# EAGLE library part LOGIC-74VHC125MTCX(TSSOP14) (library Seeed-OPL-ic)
310050042

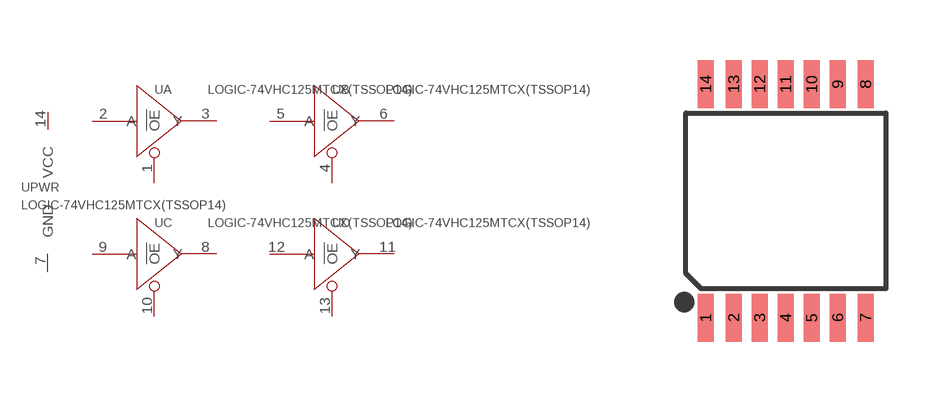
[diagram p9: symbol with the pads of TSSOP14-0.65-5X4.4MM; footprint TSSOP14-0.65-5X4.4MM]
Designator prefix U; gates A=BUFFER PWR=VCC-GND B=BUFFER C=BUFFER D=BUFFER

## LOGIC-74VHC125MTCX(TSSOP14) (MPN: 74VHC125MTCX; VALUE: 74VHC125MTCX-TSSOP14)  [TSSOP14-0.65-5X4.4MM]
1  A:!OE
2  A:A
3  A:Y
4  B:!OE
5  B:A
6  B:Y
7  PWR:GND  sup
8  C:Y
9  C:A
10  C:!OE
11  D:Y
12  D:A
13  D:!OE
14  PWR:VCC  sup

## Footprint TSSOP14-0.65-5X4.4MM (pad centres in mm)
smd 0.4 x 1.2: 1 -2,-2.925; 2 -1.3,-2.925; 3 -0.65,-2.925; 4 0,-2.925; 5 0.65,-2.925; 6 1.3,-2.925; 7 2,-2.925; 8 2,2.925; 9 1.3,2.925; 10 0.65,2.925; 11 0,2.925; 12 -0.65,2.925; 13 -1.3,2.925; 14 -2,2.925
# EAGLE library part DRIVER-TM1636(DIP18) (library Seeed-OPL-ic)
310040002

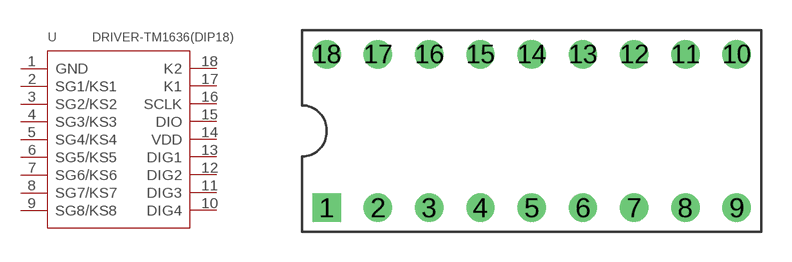
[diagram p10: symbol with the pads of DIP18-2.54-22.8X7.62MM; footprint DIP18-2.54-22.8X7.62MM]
Designator prefix U

## DRIVER-TM1636(DIP18) (MPN: TM1636; VALUE: TM1636-DIP18)  [DIP18-2.54-22.8X7.62MM]
1  GND
2  SG1/KS1
3  SG2/KS2
4  SG3/KS3
5  SG4/KS4
6  SG5/KS5
7  SG6/KS6
8  SG7/KS7
9  SG8/KS8
10  DIG4
11  DIG3
12  DIG2
13  DIG1
14  VDD
15  DIO
16  SCLK
17  K1
18  K2

## Footprint DIP18-2.54-22.8X7.62MM (pad centres in mm)
drill 0.9 pad 1.4 square: 1 -10.16,-3.81
drill 0.9 pad 1.4: 2 -7.62,-3.81; 3 -5.08,-3.81; 4 -2.54,-3.81; 5 0,-3.81; 6 2.54,-3.81; 7 5.08,-3.81; 8 7.62,-3.81; 9 10.16,-3.81; 10 10.16,3.81; 11 7.62,3.81; 12 5.08,3.81; 13 2.54,3.81; 14 0,3.81; 15 -2.54,3.81; 16 -5.08,3.81; 17 -7.62,3.81; 18 -10.16,3.81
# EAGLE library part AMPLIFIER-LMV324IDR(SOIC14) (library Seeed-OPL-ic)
310020019

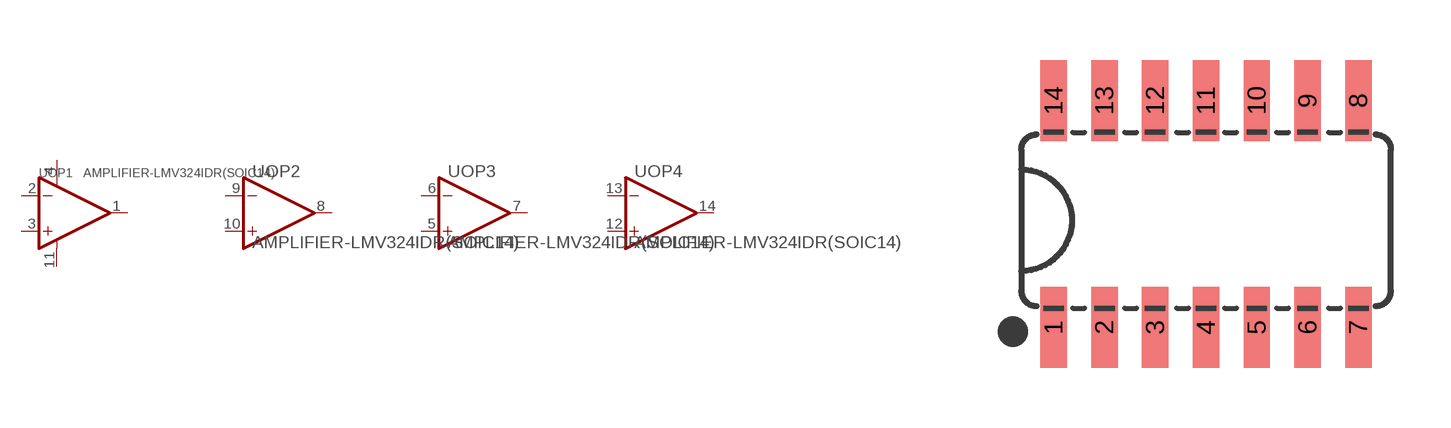
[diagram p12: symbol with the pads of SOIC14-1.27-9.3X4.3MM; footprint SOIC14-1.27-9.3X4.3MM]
Designator prefix U; gates OP1=AMPLIFIER-LM321MF OP2=OP-AMP OP3=OP-AMP OP4=OP-AMP

## AMPLIFIER-LMV324IDR(SOIC14) (MPN: LMV324IDR; VALUE: LMV324IDR-SOIC14)  [SOIC14-1.27-9.3X4.3MM]
1  OP1:OUT  out
2  OP1:IN-  in
3  OP1:IN+  in
4  OP1:V+  pwr
5  OP3:IN+  in
6  OP3:IN-  in
7  OP3:OUT  out
8  OP2:OUT  out
9  OP2:IN-  in
10  OP2:IN+  in
11  OP1:V-  pwr
12  OP4:IN+  in
13  OP4:IN-  in
14  OP4:OUT  out

## Footprint SOIC14-1.27-9.3X4.3MM (pad centres in mm)
smd 0.66 x 2.032: 1 -3.175,-2.68; 2 -1.905,-2.68; 3 -0.635,-2.68; 4 0.635,-2.68; 5 1.905,-2.68; 6 3.175,-2.68; 7 4.445,-2.68; 8 4.445,2.997; 9 3.175,2.997; 10 1.905,2.997; 11 0.635,2.997; 12 -0.635,2.997; 13 -1.905,2.997; 14 -3.175,2.997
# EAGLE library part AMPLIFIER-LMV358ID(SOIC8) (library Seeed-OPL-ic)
310020002

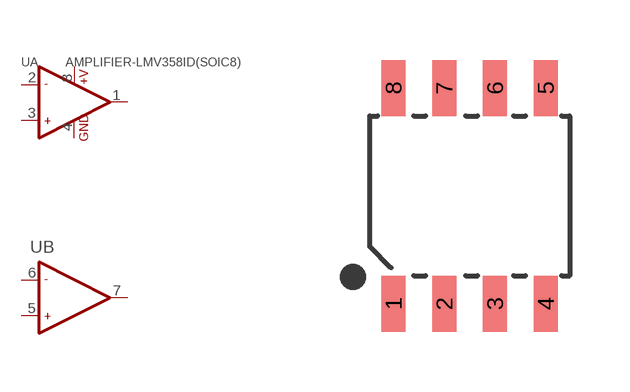
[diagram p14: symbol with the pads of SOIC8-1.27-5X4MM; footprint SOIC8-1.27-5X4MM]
Designator prefix U; gates A=OPAMP_2 B=OPAMP_2_1

## AMPLIFIER-LMV358ID(SOIC8) (MPN: LMV358ID; VALUE: LMV358ID-SOIC8)  [SOIC8-1.27-5X4MM]
1  A:OUT1  out
2  A:-IN1  in
3  A:+IN1  in
4  A:GND  pwr
5  B:+IN2  in
6  B:-IN2  in
7  B:OUT2  out
8  A:+V  pwr

## Footprint SOIC8-1.27-5X4MM (pad centres in mm)
smd 0.6 x 1.4: 1 -1.905,-2.7; 2 -0.635,-2.7; 3 0.635,-2.7; 4 1.905,-2.7; 5 1.905,2.7; 6 0.635,2.7; 7 -0.635,2.7; 8 -1.905,2.7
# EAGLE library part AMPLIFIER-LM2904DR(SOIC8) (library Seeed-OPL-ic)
310020015

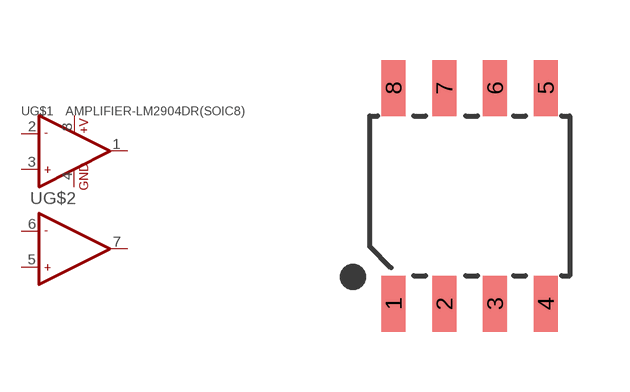
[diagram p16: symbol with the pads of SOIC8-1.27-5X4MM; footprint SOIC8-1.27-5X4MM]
Designator prefix U; gates G$1=OPAMP_2 G$2=OPAMP_2_1

## AMPLIFIER-LM2904DR(SOIC8) (MPN: LM2904DR; VALUE: LM2904DR-SOIC8)  [SOIC8-1.27-5X4MM]
1  G$1:OUT1  out
2  G$1:-IN1  in
3  G$1:+IN1  in
4  G$1:GND  pwr
5  G$2:+IN2  in
6  G$2:-IN2  in
7  G$2:OUT2  out
8  G$1:+V  pwr

## Footprint SOIC8-1.27-5X4MM (pad centres in mm)
smd 0.6 x 1.4: 1 -1.905,-2.7; 2 -0.635,-2.7; 3 0.635,-2.7; 4 1.905,-2.7; 5 1.905,2.7; 6 0.635,2.7; 7 -0.635,2.7; 8 -1.905,2.7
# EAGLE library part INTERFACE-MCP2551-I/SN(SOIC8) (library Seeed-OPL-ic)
310070024

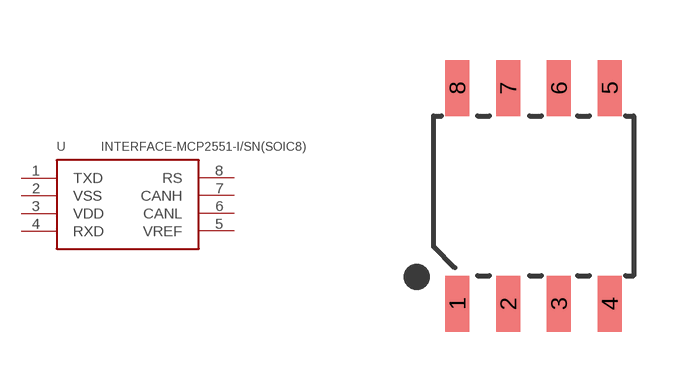
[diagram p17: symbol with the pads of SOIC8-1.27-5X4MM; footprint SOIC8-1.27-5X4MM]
Designator prefix U

## INTERFACE-MCP2551-I/SN(SOIC8) (MPN: MCP2551-I/SN; VALUE: MCP2551-I/SN-SOIC8)  [SOIC8-1.27-5X4MM]
1  TXD
2  VSS
3  VDD
4  RXD
5  VREF
6  CANL
7  CANH
8  RS

## Footprint SOIC8-1.27-5X4MM (pad centres in mm)
smd 0.6 x 1.4: 1 -1.905,-2.7; 2 -0.635,-2.7; 3 0.635,-2.7; 4 1.905,-2.7; 5 1.905,2.7; 6 0.635,2.7; 7 -0.635,2.7; 8 -1.905,2.7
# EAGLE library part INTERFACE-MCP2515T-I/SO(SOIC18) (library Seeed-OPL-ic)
310070025

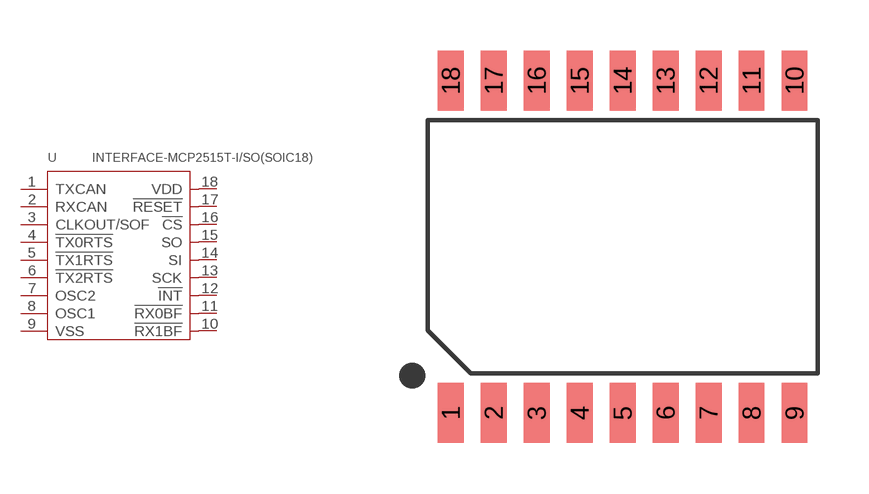
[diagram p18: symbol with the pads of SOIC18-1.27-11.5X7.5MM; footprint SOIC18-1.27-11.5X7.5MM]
Designator prefix U

## INTERFACE-MCP2515T-I/SO(SOIC18) (MPN: MCP2515T-I/SO; VALUE: MCP2515T-I/SO-SOIC18)  [SOIC18-1.27-11.5X7.5MM]
1  TXCAN  out
2  RXCAN  in
3  CLKOUT/SOF  out
4  !TX0RTS  in
5  !TX1RTS  in
6  !TX2RTS  in
7  OSC2  out
8  OSC1  in
9  VSS  sup
10  !RX1BF  out
11  !RX0BF  out
12  !INT  out
13  SCK  in
14  SI  in
15  SO  out
16  !CS  in
17  !RESET  in
18  VDD  sup

## Footprint SOIC18-1.27-11.5X7.5MM (pad centres in mm)
smd 0.762 x 1.778: 1 -5.08,-4.915; 2 -3.81,-4.915; 3 -2.54,-4.915; 4 -1.27,-4.915; 5 0,-4.915; 6 1.27,-4.915; 7 2.54,-4.915; 8 3.81,-4.915; 9 5.08,-4.915; 10 5.08,4.915; 11 3.81,4.915; 12 2.54,4.915; 13 1.27,4.915; 14 0,4.915; 15 -1.27,4.915; 16 -2.54,4.915; 17 -3.81,4.915; 18 -5.08,4.915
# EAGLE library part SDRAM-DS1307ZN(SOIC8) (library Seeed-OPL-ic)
310110010

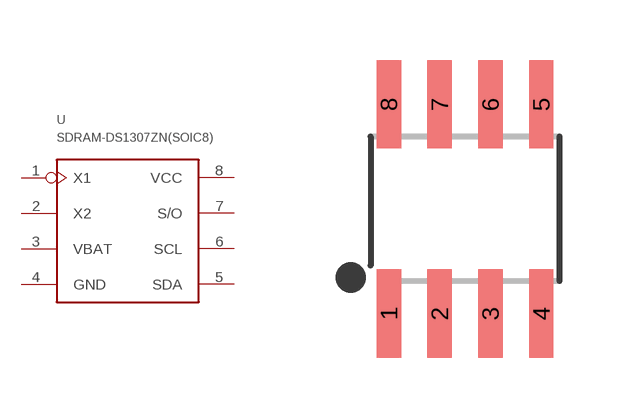
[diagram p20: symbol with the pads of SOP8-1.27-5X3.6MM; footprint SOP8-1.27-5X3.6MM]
Designator prefix U

## SDRAM-DS1307ZN(SOIC8) (MPN: DS1307ZN; VALUE: DS1307ZN-sop8)  [SOP8-1.27-5X3.6MM]
1  X1
2  X2
3  VBAT
4  GND
5  SDA
6  SCL
7  S/O
8  VCC

## Footprint SOP8-1.27-5X3.6MM (pad centres in mm)
Small Outline Package
smd 0.61 x 2.21: 1 -1.905,-2.616; 2 -0.635,-2.616; 3 0.635,-2.616; 4 1.905,-2.616; 5 1.905,2.616; 6 0.635,2.616; 7 -0.635,2.616; 8 -1.905,2.616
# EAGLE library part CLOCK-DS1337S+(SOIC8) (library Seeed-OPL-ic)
310110008

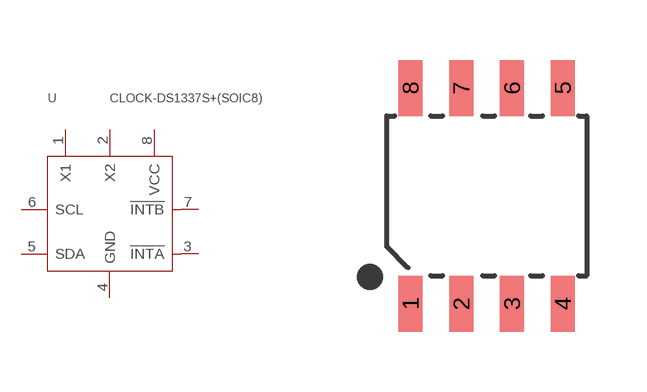
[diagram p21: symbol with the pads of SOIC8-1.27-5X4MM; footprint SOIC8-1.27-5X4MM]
Designator prefix U

## CLOCK-DS1337S+(SOIC8) (MPN: DS1337S+; VALUE: DS13337S+-SOIC8)  [SOIC8-1.27-5X4MM]
1  X1
2  X2
3  !INTA!
4  GND
5  SDA
6  SCL
7  !INTB!
8  VCC

## Footprint SOIC8-1.27-5X4MM (pad centres in mm)
smd 0.6 x 1.4: 1 -1.905,-2.7; 2 -0.635,-2.7; 3 0.635,-2.7; 4 1.905,-2.7; 5 1.905,2.7; 6 0.635,2.7; 7 -0.635,2.7; 8 -1.905,2.7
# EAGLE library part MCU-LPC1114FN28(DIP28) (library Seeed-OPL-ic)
310010024

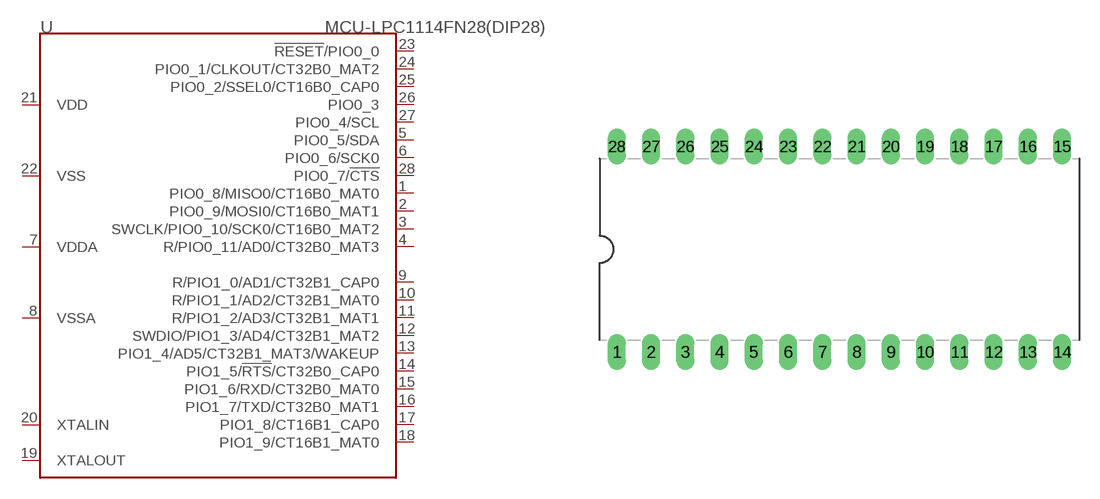
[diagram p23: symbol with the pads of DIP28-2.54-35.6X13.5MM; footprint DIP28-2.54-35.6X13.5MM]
Designator prefix U

## MCU-LPC1114FN28(DIP28) (MPN: LPC1114FN28; VALUE: LPC1114FN28-DIP28)  [DIP28-2.54-35.6X13.5MM]
1  PIO0_8/MISO0/CT16B0_MAT0
2  PIO0_9/MOSI0/CT16B0_MAT1
3  SWCLK/PIO0_10/SCK0/CT16B0_MAT2
4  R/PIO0_11/AD0/CT32B0_MAT3
5  PIO0_5/SDA
6  PIO0_6/SCK0
7  VDDA  pwr
8  VSSA  pwr
9  R/PIO1_0/AD1/CT32B1_CAP0
10  R/PIO1_1/AD2/CT32B1_MAT0
11  R/PIO1_2/AD3/CT32B1_MAT1
12  SWDIO/PIO1_3/AD4/CT32B1_MAT2
13  PIO1_4/AD5/CT32B1_MAT3/WAKEUP
14  PIO1_5/!RTS!/CT32B0_CAP0
15  PIO1_6/RXD/CT32B0_MAT0
16  PIO1_7/TXD/CT32B0_MAT1
17  PIO1_8/CT16B1_CAP0
18  PIO1_9/CT16B1_MAT0
19  XTALOUT  pas
20  XTALIN  pas
21  VDD  pwr
22  VSS  pwr
23  !RESET!/PIO0_0
24  PIO0_1/CLKOUT/CT32B0_MAT2
25  PIO0_2/SSEL0/CT16B0_CAP0
26  PIO0_3
27  PIO0_4/SCL
28  PIO0_7/!CTS!

## Footprint DIP28-2.54-35.6X13.5MM (pad centres in mm)
drill 0.813 long: 1 -16.51,-7.62; 2 -13.97,-7.62; 3 -11.43,-7.62; 4 -8.89,-7.62; 5 -6.35,-7.62; 6 -3.81,-7.62; 7 -1.27,-7.62; 8 1.27,-7.62; 9 3.81,-7.62; 10 6.35,-7.62; 11 8.89,-7.62; 12 11.43,-7.62; 13 13.97,-7.62; 14 16.51,-7.62; 15 16.51,7.62; 16 13.97,7.62; 17 11.43,7.62; 18 8.89,7.62; 19 6.35,7.62; 20 3.81,7.62; 21 1.27,7.62; 22 -1.27,7.62; 23 -3.81,7.62; 24 -6.35,7.62; 25 -8.89,7.62; 26 -11.43,7.62; 27 -13.97,7.62; 28 -16.51,7.62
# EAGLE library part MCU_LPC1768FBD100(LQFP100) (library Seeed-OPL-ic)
310010001

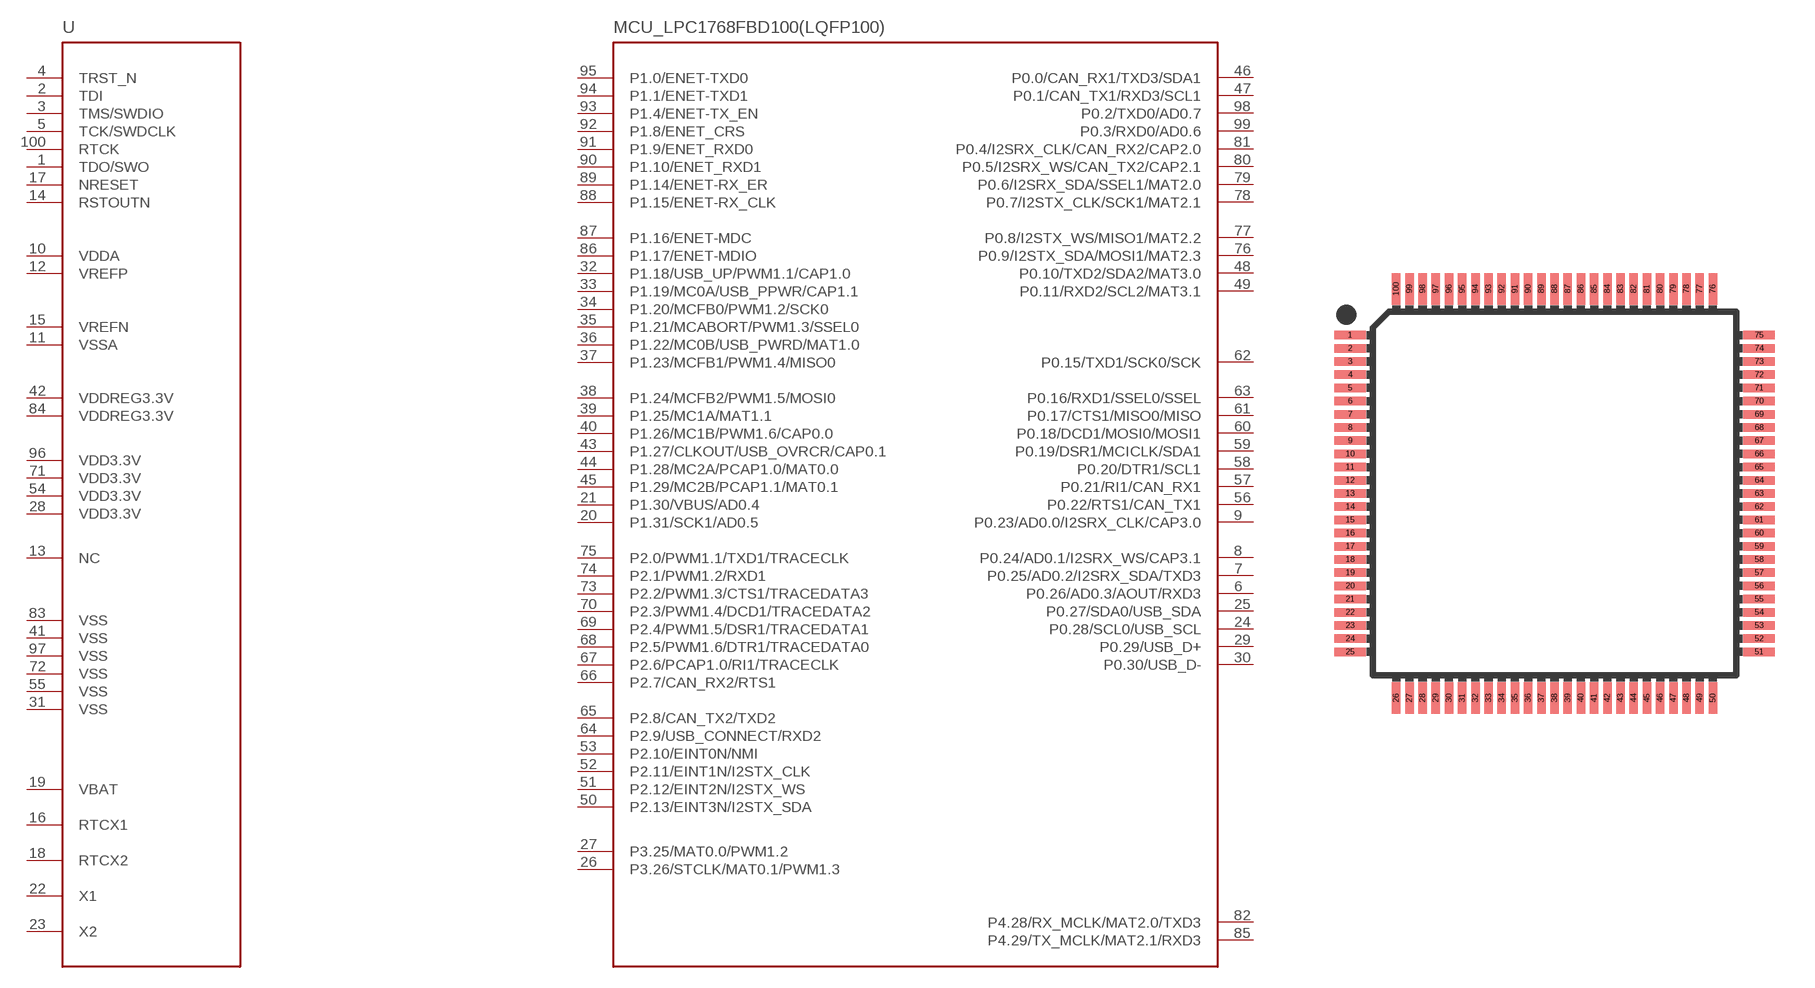
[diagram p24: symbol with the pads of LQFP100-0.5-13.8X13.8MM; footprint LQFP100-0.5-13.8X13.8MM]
Designator prefix U

## MCU_LPC1768FBD100(LQFP100) (MPN: LPC1768FBD100; VALUE: LPC1768FBD100-LQFP100)  [LQFP100-0.5-13.8X13.8MM]
1  TDO/SWO
2  TDI
3  TMS/SWDIO
4  TRST_N
5  TCK/SWDCLK
6  P0.26/AD0.3/AOUT/RXD3
7  P0.25/AD0.2/I2SRX_SDA/TXD3
8  P0.24/AD0.1/I2SRX_WS/CAP3.1
9  P0.23/AD0.0/I2SRX_CLK/CAP3.0
10  VDDA
11  VSSA
12  VREFP
13  NC
14  RSTOUTN
15  VREFN
16  RTCX1
17  NRESET
18  RTCX2
19  VBAT
20  P1.31/SCK1/AD0.5
21  P1.30/VBUS/AD0.4
22  X1
23  X2
24  P0.28/SCL0/USB_SCL
25  P0.27/SDA0/USB_SDA
26  P3.26/STCLK/MAT0.1/PWM1.3
27  P3.25/MAT0.0/PWM1.2
28  VDD3.3V
29  P0.29/USB_D+
30  P0.30/USB_D-
31  VSS
32  P1.18/USB_UP/PWM1.1/CAP1.0
33  P1.19/MC0A/USB_PPWR/CAP1.1
34  P1.20/MCFB0/PWM1.2/SCK0
35  P1.21/MCABORT/PWM1.3/SSEL0
36  P1.22/MC0B/USB_PWRD/MAT1.0
37  P1.23/MCFB1/PWM1.4/MISO0
38  P1.24/MCFB2/PWM1.5/MOSI0
39  P1.25/MC1A/MAT1.1
40  P1.26/MC1B/PWM1.6/CAP0.0
41  VSS
42  VDDREG3.3V
43  P1.27/CLKOUT/USB_OVRCR/CAP0.1
44  P1.28/MC2A/PCAP1.0/MAT0.0
45  P1.29/MC2B/PCAP1.1/MAT0.1
46  P0.0/CAN_RX1/TXD3/SDA1
47  P0.1/CAN_TX1/RXD3/SCL1
48  P0.10/TXD2/SDA2/MAT3.0
49  P0.11/RXD2/SCL2/MAT3.1
50  P2.13/EINT3N/I2STX_SDA
51  P2.12/EINT2N/I2STX_WS
52  P2.11/EINT1N/I2STX_CLK
53  P2.10/EINT0N/NMI
54  VDD3.3V
55  VSS
56  P0.22/RTS1/CAN_TX1
57  P0.21/RI1/CAN_RX1
58  P0.20/DTR1/SCL1
59  P0.19/DSR1/MCICLK/SDA1
60  P0.18/DCD1/MOSI0/MOSI1
61  P0.17/CTS1/MISO0/MISO
62  P0.15/TXD1/SCK0/SCK
63  P0.16/RXD1/SSEL0/SSEL
64  P2.9/USB_CONNECT/RXD2
65  P2.8/CAN_TX2/TXD2
66  P2.7/CAN_RX2/RTS1
67  P2.6/PCAP1.0/RI1/TRACECLK
68  P2.5/PWM1.6/DTR1/TRACEDATA0
69  P2.4/PWM1.5/DSR1/TRACEDATA1
70  P2.3/PWM1.4/DCD1/TRACEDATA2
71  VDD3.3V
72  VSS
73  P2.2/PWM1.3/CTS1/TRACEDATA3
74  P2.1/PWM1.2/RXD1
75  P2.0/PWM1.1/TXD1/TRACECLK
76  P0.9/I2STX_SDA/MOSI1/MAT2.3
77  P0.8/I2STX_WS/MISO1/MAT2.2
78  P0.7/I2STX_CLK/SCK1/MAT2.1
79  P0.6/I2SRX_SDA/SSEL1/MAT2.0
80  P0.5/I2SRX_WS/CAN_TX2/CAP2.1
81  P0.4/I2SRX_CLK/CAN_RX2/CAP2.0
82  P4.28/RX_MCLK/MAT2.0/TXD3
83  VSS
84  VDDREG3.3V
85  P4.29/TX_MCLK/MAT2.1/RXD3
86  P1.17/ENET-MDIO
87  P1.16/ENET-MDC
88  P1.15/ENET-RX_CLK
89  P1.14/ENET-RX_ER
90  P1.10/ENET_RXD1
91  P1.9/ENET_RXD0
92  P1.8/ENET_CRS
93  P1.4/ENET-TX_EN
94  P1.1/ENET-TXD1
95  P1.0/ENET-TXD0
96  VDD3.3V
97  VSS
98  P0.2/TXD0/AD0.7
99  P0.3/RXD0/AD0.6
100  RTCK

## Footprint LQFP100-0.5-13.8X13.8MM (pad centres in mm)
smd 1.2 x 0.32: 1 -7.75,6; 2 -7.75,5.5; 3 -7.75,5; 4 -7.75,4.5; 5 -7.75,4; 6 -7.75,3.5; 7 -7.75,3; 8 -7.75,2.5; 9 -7.75,2; 10 -7.75,1.5; 11 -7.75,1; 12 -7.75,0.5; 13 -7.75,0; 14 -7.75,-0.5; 15 -7.75,-1; 16 -7.75,-1.5; 17 -7.75,-2; 18 -7.75,-2.5; 19 -7.75,-3; 20 -7.75,-3.5; 21 -7.75,-4; 22 -7.75,-4.5; 23 -7.75,-5; 24 -7.75,-5.5; 25 -7.75,-6; 51 7.75,-6; 52 7.75,-5.5; 53 7.75,-5; 54 7.75,-4.5; 55 7.75,-4; 56 7.75,-3.5; 57 7.75,-3; 58 7.75,-2.5; 59 7.75,-2; 60 7.75,-1.5; 61 7.75,-1; 62 7.75,-0.5; 63 7.75,0; 64 7.75,0.5; 65 7.75,1; 66 7.75,1.5; 67 7.75,2; 68 7.75,2.5; 69 7.75,3; 70 7.75,3.5; 71 7.75,4; 72 7.75,4.5; 73 7.75,5; 74 7.75,5.5; 75 7.75,6
smd 0.32 x 1.2: 26 -6,-7.75; 27 -5.5,-7.75; 28 -5,-7.75; 29 -4.5,-7.75; 30 -4,-7.75; 31 -3.5,-7.75; 32 -3,-7.75; 33 -2.5,-7.75; 34 -2,-7.75; 35 -1.5,-7.75; 36 -1,-7.75; 37 -0.5,-7.75; 38 0,-7.75; 39 0.5,-7.75; 40 1,-7.75; 41 1.5,-7.75; 42 2,-7.75; 43 2.5,-7.75; 44 3,-7.75; 45 3.5,-7.75; 46 4,-7.75; 47 4.5,-7.75; 48 5,-7.75; 49 5.5,-7.75; 50 6,-7.75; 76 6,7.75; 77 5.5,7.75; 78 5,7.75; 79 4.5,7.75; 80 4,7.75; 81 3.5,7.75; 82 3,7.75; 83 2.5,7.75; 84 2,7.75; 85 1.5,7.75; 86 1,7.75; 87 0.5,7.75; 88 0,7.75; 89 -0.5,7.75; 90 -1,7.75; 91 -1.5,7.75; 92 -2,7.75; 93 -2.5,7.75; 94 -3,7.75; 95 -3.5,7.75; 96 -4,7.75; 97 -4.5,7.75; 98 -5,7.75; 99 -5.5,7.75; 100 -6,7.75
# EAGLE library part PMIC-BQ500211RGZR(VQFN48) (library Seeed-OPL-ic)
310030145

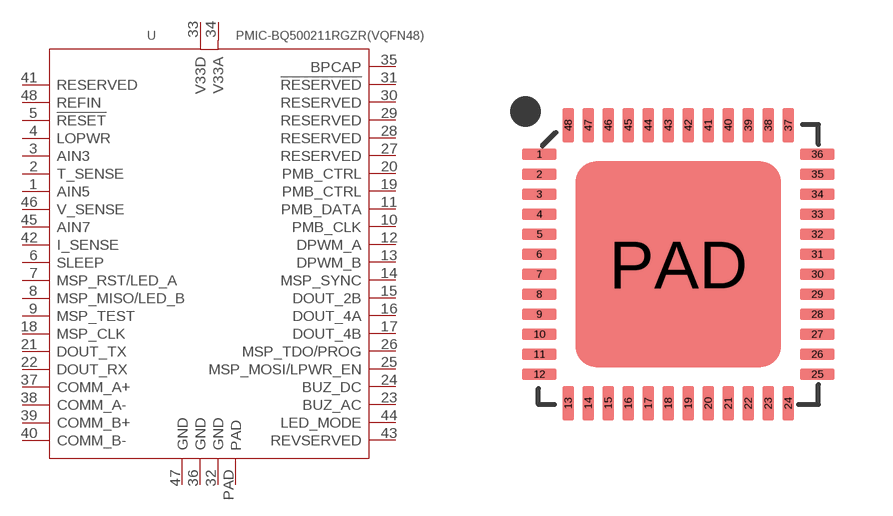
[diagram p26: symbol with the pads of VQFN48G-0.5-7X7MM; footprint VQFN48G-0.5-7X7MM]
Designator prefix U

## PMIC-BQ500211RGZR(VQFN48) (MPN: BQ500211RGZR; VALUE: BQ500211RGZR-VQFN48)  [VQFN48G-0.5-7X7MM]
1  AIN5
2  T_SENSE
3  AIN3
4  LOPWR
5  !RESET
6  SLEEP
7  MSP_RST/LED_A
8  MSP_MISO/LED_B
9  MSP_TEST
10  PMB_CLK
11  PMB_DATA
12  DPWM_A
13  DPWM_B
14  MSP_SYNC
15  DOUT_2B
16  DOUT_4A
17  DOUT_4B
18  MSP_CLK
19  PMB_CTRL
20  PMB_CTRL
21  DOUT_TX
22  DOUT_RX
23  BUZ_AC
24  BUZ_DC
25  MSP_MOSI/LPWR_EN
26  MSP_TDO/PROG
27  RESERVED
28  RESERVED
29  RESERVED
30  RESERVED
31  !RESERVED
32  GND
33  V33D
34  V33A
35  BPCAP
36  GND
37  COMM_A+
38  COMM_A-
39  COMM_B+
40  COMM_B-
41  RESERVED
42  I_SENSE
43  REVSERVED
44  LED_MODE
45  AIN7
46  V_SENSE
47  GND
48  REFIN
PAD  PAD

## Footprint VQFN48G-0.5-7X7MM (pad centres in mm)
smd 0.85 x 0.28: 1 -3.475,2.75; 2 -3.475,2.25; 3 -3.475,1.75; 4 -3.475,1.25; 5 -3.475,0.75; 6 -3.475,0.25; 7 -3.475,-0.25; 8 -3.475,-0.75; 9 -3.475,-1.25; 10 -3.475,-1.75; 11 -3.475,-2.25; 12 -3.475,-2.75; 25 3.475,-2.75; 26 3.475,-2.25; 27 3.475,-1.75; 28 3.475,-1.25; 29 3.475,-0.75; 30 3.475,-0.25; 31 3.475,0.25; 32 3.475,0.75; 33 3.475,1.25; 34 3.475,1.75; 35 3.475,2.25; 36 3.475,2.75
smd 0.28 x 0.85: 13 -2.75,-3.475; 14 -2.25,-3.475; 15 -1.75,-3.475; 16 -1.25,-3.475; 17 -0.75,-3.475; 18 -0.25,-3.475; 19 0.25,-3.475; 20 0.75,-3.475; 21 1.25,-3.475; 22 1.75,-3.475; 23 2.25,-3.475; 24 2.75,-3.475; 37 2.75,3.475; 38 2.25,3.475; 39 1.75,3.475; 40 1.25,3.475; 41 0.75,3.475; 42 0.25,3.475; 43 -0.25,3.475; 44 -0.75,3.475; 45 -1.25,3.475; 46 -1.75,3.475; 47 -2.25,3.475; 48 -2.75,3.475
smd 5.15 x 5.15: PAD 0,0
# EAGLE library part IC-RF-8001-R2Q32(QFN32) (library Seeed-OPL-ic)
310060013

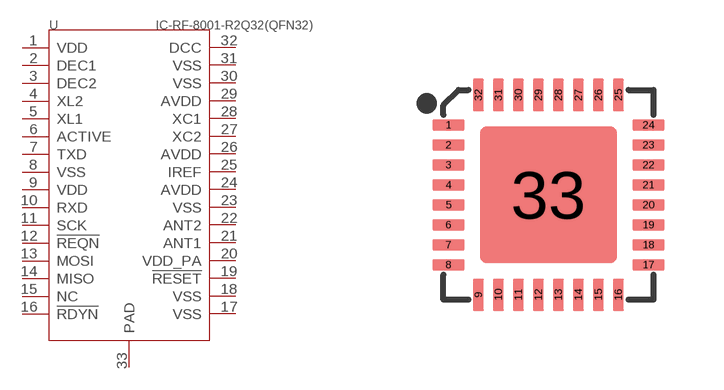
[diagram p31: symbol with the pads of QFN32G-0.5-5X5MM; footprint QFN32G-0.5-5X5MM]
Designator prefix U

## IC-RF-8001-R2Q32(QFN32) (MPN: 8001-R2Q32; VALUE: 8001-R2Q32-QFN32)  [QFN32G-0.5-5X5MM]
1  VDD
2  DEC1
3  DEC2
4  XL2
5  XL1
6  ACTIVE
7  TXD
8  VSS
9  VDD
10  RXD
11  SCK
12  !REQN
13  MOSI
14  MISO
15  NC
16  !RDYN
17  VSS
18  VSS
19  !RESET
20  VDD_PA
21  ANT1
22  ANT2
23  VSS
24  AVDD
25  IREF
26  AVDD
27  XC2
28  XC1
29  AVDD
30  VSS
31  VSS
32  DCC
33  PAD

## Footprint QFN32G-0.5-5X5MM (pad centres in mm)
smd 0.813 x 0.279: 1 -2.5,1.75; 2 -2.5,1.25; 3 -2.5,0.75; 4 -2.5,0.25; 5 -2.5,-0.25; 6 -2.5,-0.75; 7 -2.5,-1.25; 8 -2.5,-1.75; 17 2.5,-1.75; 18 2.5,-1.25; 19 2.5,-0.75; 20 2.5,-0.25; 21 2.5,0.25; 22 2.5,0.75; 23 2.5,1.25; 24 2.5,1.75
smd 0.279 x 0.813: 9 -1.75,-2.5; 10 -1.25,-2.5; 11 -0.75,-2.5; 12 -0.25,-2.5; 13 0.25,-2.5; 14 0.75,-2.5; 15 1.25,-2.5; 16 1.75,-2.5; 25 1.75,2.5; 26 1.25,2.5; 27 0.75,2.5; 28 0.25,2.5; 29 -0.25,2.5; 30 -0.75,2.5; 31 -1.25,2.5; 32 -1.75,2.5
smd 3.429 x 3.429: 33 0,0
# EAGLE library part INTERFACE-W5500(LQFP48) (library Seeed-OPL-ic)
310070032

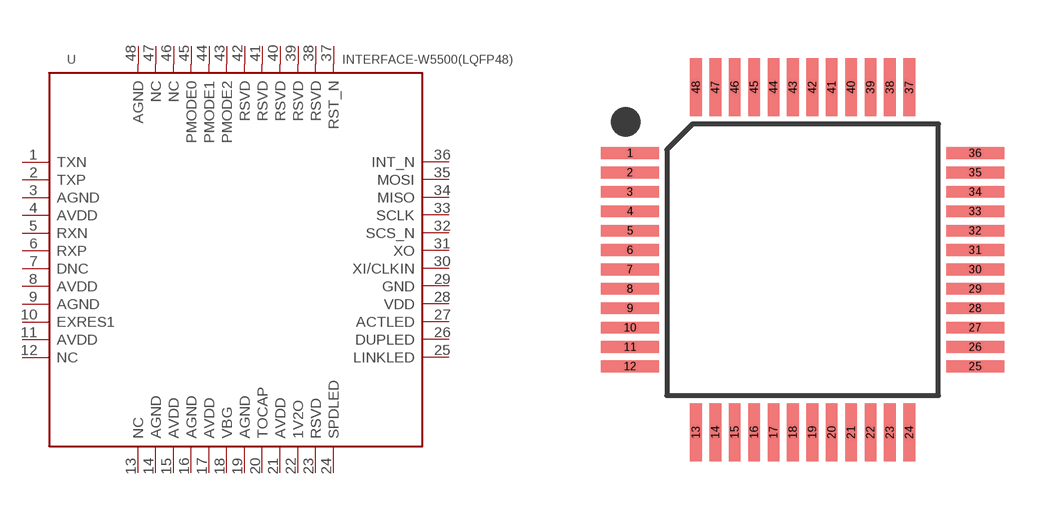
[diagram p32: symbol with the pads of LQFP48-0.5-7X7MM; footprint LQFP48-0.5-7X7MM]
Designator prefix U

## INTERFACE-W5500(LQFP48) (MPN: W5500; VALUE: W5500-LQFP48)  [LQFP48-0.5-7X7MM]
1  TXN  pas
2  TXP  pas
3  AGND  pas
4  AVDD  pas
5  RXN  pas
6  RXP  pas
7  DNC  pas
8  AVDD  pas
9  AGND  pas
10  EXRES1  pas
11  AVDD  pas
12  NC  pas
13  NC  pas
14  AGND  pas
15  AVDD  pas
16  AGND  pas
17  AVDD  pas
18  VBG  pas
19  AGND  pas
20  TOCAP  pas
21  AVDD  pas
22  1V2O  pas
23  RSVD  pas
24  SPDLED  pas
25  LINKLED  pas
26  DUPLED  pas
27  ACTLED  pas
28  VDD  pas
29  GND  pas
30  XI/CLKIN  pas
31  XO  pas
32  SCS_N  pas
33  SCLK  pas
34  MISO  pas
35  MOSI  pas
36  INT_N  pas
37  RST_N  pas
38  RSVD  pas
39  RSVD  pas
40  RSVD  pas
41  RSVD  pas
42  RSVD  pas
43  PMODE2  pas
44  PMODE1  pas
45  PMODE0  pas
46  NC  pas
47  NC  pas
48  AGND  pas

## Footprint LQFP48-0.5-7X7MM (pad centres in mm)
smd 1.5 x 0.3: 1 -4.45,2.75; 2 -4.45,2.25; 3 -4.45,1.75; 4 -4.45,1.25; 5 -4.45,0.75; 6 -4.45,0.25; 7 -4.45,-0.25; 8 -4.45,-0.75; 9 -4.45,-1.25; 10 -4.45,-1.75; 11 -4.45,-2.25; 12 -4.45,-2.75; 25 4.45,-2.75; 26 4.45,-2.25; 27 4.45,-1.75; 28 4.45,-1.25; 29 4.45,-0.75; 30 4.45,-0.25; 31 4.45,0.25; 32 4.45,0.75; 33 4.45,1.25; 34 4.45,1.75; 35 4.45,2.25; 36 4.45,2.75
smd 0.3 x 1.5: 13 -2.75,-4.45; 14 -2.25,-4.45; 15 -1.75,-4.45; 16 -1.25,-4.45; 17 -0.75,-4.45; 18 -0.25,-4.45; 19 0.25,-4.45; 20 0.75,-4.45; 21 1.25,-4.45; 22 1.75,-4.45; 23 2.25,-4.45; 24 2.75,-4.45; 37 2.75,4.45; 38 2.25,4.45; 39 1.75,4.45; 40 1.25,4.45; 41 0.75,4.45; 42 0.25,4.45; 43 -0.25,4.45; 44 -0.75,4.45; 45 -1.25,4.45; 46 -1.75,4.45; 47 -2.25,4.45; 48 -2.75,4.45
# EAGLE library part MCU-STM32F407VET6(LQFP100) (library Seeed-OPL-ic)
310010067

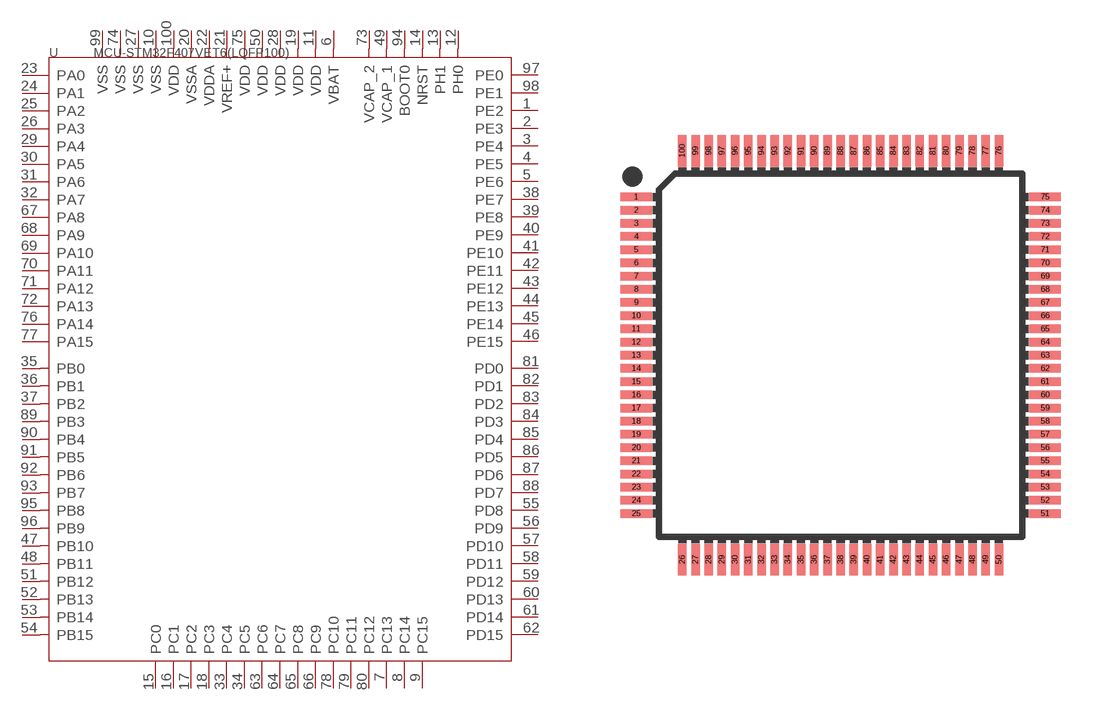
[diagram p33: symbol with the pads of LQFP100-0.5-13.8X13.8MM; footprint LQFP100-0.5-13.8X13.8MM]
Designator prefix U

## MCU-STM32F407VET6(LQFP100) (MPN: STM32F407VET6; VALUE: STM32F407VET6-LQFP100)  [LQFP100-0.5-13.8X13.8MM]
1  PE2
2  PE3
3  PE4
4  PE5
5  PE6
6  VBAT
7  PC13
8  PC14
9  PC15
10  VSS
11  VDD
12  PH0
13  PH1
14  NRST
15  PC0
16  PC1
17  PC2
18  PC3
19  VDD
20  VSSA
21  VREF+
22  VDDA
23  PA0
24  PA1
25  PA2
26  PA3
27  VSS
28  VDD
29  PA4
30  PA5
31  PA6
32  PA7
33  PC4
34  PC5
35  PB0
36  PB1
37  PB2
38  PE7
39  PE8
40  PE9
41  PE10
42  PE11
43  PE12
44  PE13
45  PE14
46  PE15
47  PB10
48  PB11
49  VCAP_1
50  VDD
51  PB12
52  PB13
53  PB14
54  PB15
55  PD8
56  PD9
57  PD10
58  PD11
59  PD12
60  PD13
61  PD14
62  PD15
63  PC6
64  PC7
65  PC8
66  PC9
67  PA8
68  PA9
69  PA10
70  PA11
71  PA12
72  PA13
73  VCAP_2
74  VSS
75  VDD
76  PA14
77  PA15
78  PC10
79  PC11
80  PC12
81  PD0
82  PD1
83  PD2
84  PD3
85  PD4
86  PD5
87  PD6
88  PD7
89  PB3
90  PB4
91  PB5
92  PB6
93  PB7
94  BOOT0
95  PB8
96  PB9
97  PE0
98  PE1
99  VSS
100  VDD

## Footprint LQFP100-0.5-13.8X13.8MM (pad centres in mm)
smd 1.2 x 0.32: 1 -7.75,6; 2 -7.75,5.5; 3 -7.75,5; 4 -7.75,4.5; 5 -7.75,4; 6 -7.75,3.5; 7 -7.75,3; 8 -7.75,2.5; 9 -7.75,2; 10 -7.75,1.5; 11 -7.75,1; 12 -7.75,0.5; 13 -7.75,0; 14 -7.75,-0.5; 15 -7.75,-1; 16 -7.75,-1.5; 17 -7.75,-2; 18 -7.75,-2.5; 19 -7.75,-3; 20 -7.75,-3.5; 21 -7.75,-4; 22 -7.75,-4.5; 23 -7.75,-5; 24 -7.75,-5.5; 25 -7.75,-6; 51 7.75,-6; 52 7.75,-5.5; 53 7.75,-5; 54 7.75,-4.5; 55 7.75,-4; 56 7.75,-3.5; 57 7.75,-3; 58 7.75,-2.5; 59 7.75,-2; 60 7.75,-1.5; 61 7.75,-1; 62 7.75,-0.5; 63 7.75,0; 64 7.75,0.5; 65 7.75,1; 66 7.75,1.5; 67 7.75,2; 68 7.75,2.5; 69 7.75,3; 70 7.75,3.5; 71 7.75,4; 72 7.75,4.5; 73 7.75,5; 74 7.75,5.5; 75 7.75,6
smd 0.32 x 1.2: 26 -6,-7.75; 27 -5.5,-7.75; 28 -5,-7.75; 29 -4.5,-7.75; 30 -4,-7.75; 31 -3.5,-7.75; 32 -3,-7.75; 33 -2.5,-7.75; 34 -2,-7.75; 35 -1.5,-7.75; 36 -1,-7.75; 37 -0.5,-7.75; 38 0,-7.75; 39 0.5,-7.75; 40 1,-7.75; 41 1.5,-7.75; 42 2,-7.75; 43 2.5,-7.75; 44 3,-7.75; 45 3.5,-7.75; 46 4,-7.75; 47 4.5,-7.75; 48 5,-7.75; 49 5.5,-7.75; 50 6,-7.75; 76 6,7.75; 77 5.5,7.75; 78 5,7.75; 79 4.5,7.75; 80 4,7.75; 81 3.5,7.75; 82 3,7.75; 83 2.5,7.75; 84 2,7.75; 85 1.5,7.75; 86 1,7.75; 87 0.5,7.75; 88 0,7.75; 89 -0.5,7.75; 90 -1,7.75; 91 -1.5,7.75; 92 -2,7.75; 93 -2.5,7.75; 94 -3,7.75; 95 -3.5,7.75; 96 -4,7.75; 97 -4.5,7.75; 98 -5,7.75; 99 -5.5,7.75; 100 -6,7.75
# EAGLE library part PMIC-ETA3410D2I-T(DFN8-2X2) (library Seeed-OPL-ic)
310030161

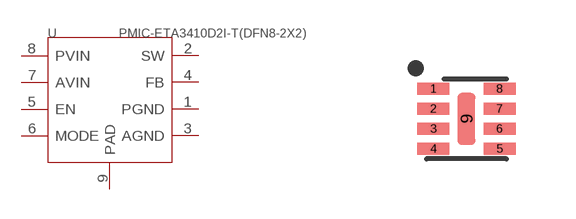
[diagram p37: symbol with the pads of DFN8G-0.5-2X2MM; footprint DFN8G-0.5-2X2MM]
Designator prefix U

## PMIC-ETA3410D2I-T(DFN8-2X2) (MPN: ETA3410D2I-T; VALUE: ETA3410D2I-T-DFN8)  [DFN8G-0.5-2X2MM]
1  PGND
2  SW
3  AGND
4  FB
5  EN
6  MODE
7  AVIN
8  PVIN
9  PAD

## Footprint DFN8G-0.5-2X2MM (pad centres in mm)
smd 0.8 x 0.3: 1 -0.827,0.75; 2 -0.827,0.25; 3 -0.827,-0.25; 4 -0.827,-0.75; 5 0.827,-0.75; 6 0.827,-0.25; 7 0.827,0.25; 8 0.827,0.75
smd 0.45 x 1.3: 9 0,0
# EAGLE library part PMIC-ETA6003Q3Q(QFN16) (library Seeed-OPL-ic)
310990023

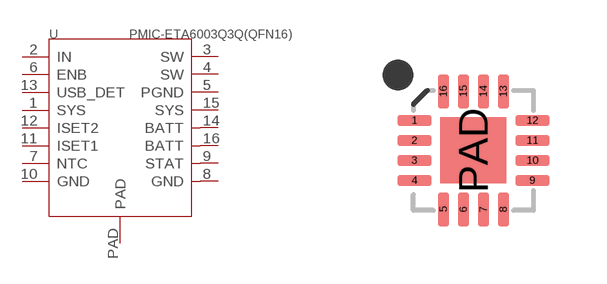
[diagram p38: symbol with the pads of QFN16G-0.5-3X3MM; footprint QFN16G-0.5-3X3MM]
Designator prefix U

## PMIC-ETA6003Q3Q(QFN16) (MPN: ETA6003Q3Q; VALUE: ETA6003Q3Q-QFN16)  [QFN16G-0.5-3X3MM]
1  SYS
2  IN
3  SW
4  SW
5  PGND
6  ENB
7  NTC
8  GND
9  STAT
10  GND
11  ISET1
12  ISET2
13  USB_DET
14  BATT
15  SYS
16  BATT
PAD  PAD

## Footprint QFN16G-0.5-3X3MM (pad centres in mm)
smd 0.85 x 0.28: 1 -1.475,0.75; 2 -1.475,0.25; 3 -1.475,-0.25; 4 -1.475,-0.75; 9 1.475,-0.75; 10 1.475,-0.25; 11 1.475,0.25; 12 1.475,0.75
smd 0.28 x 0.85: 5 -0.75,-1.475; 6 -0.25,-1.475; 7 0.25,-1.475; 8 0.75,-1.475; 13 0.75,1.475; 14 0.25,1.475; 15 -0.25,1.475; 16 -0.75,1.475
smd 1.65 x 1.65: PAD 0,0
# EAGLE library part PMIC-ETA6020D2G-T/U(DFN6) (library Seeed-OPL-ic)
310990024

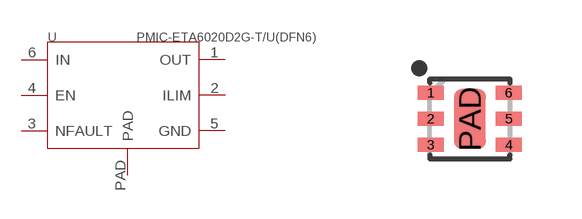
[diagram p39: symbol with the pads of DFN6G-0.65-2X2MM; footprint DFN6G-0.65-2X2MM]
Designator prefix U

## PMIC-ETA6020D2G-T/U(DFN6) (MPN: ETA6020D2G-T/U; VALUE: ETA6020D2G-T/U-DFN6)  [DFN6G-0.65-2X2MM]
1  OUT
2  ILIM
3  NFAULT
4  EN
5  GND
6  IN
PAD  PAD

## Footprint DFN6G-0.65-2X2MM (pad centres in mm)
smd 0.65 x 0.35: 1 -0.975,0.65; 2 -0.975,0; 3 -0.975,-0.65; 4 0.975,-0.65; 5 0.975,0; 6 0.975,0.65
smd 0.8 x 1.5: PAD 0,0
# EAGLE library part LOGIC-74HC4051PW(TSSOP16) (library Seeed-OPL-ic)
310070017

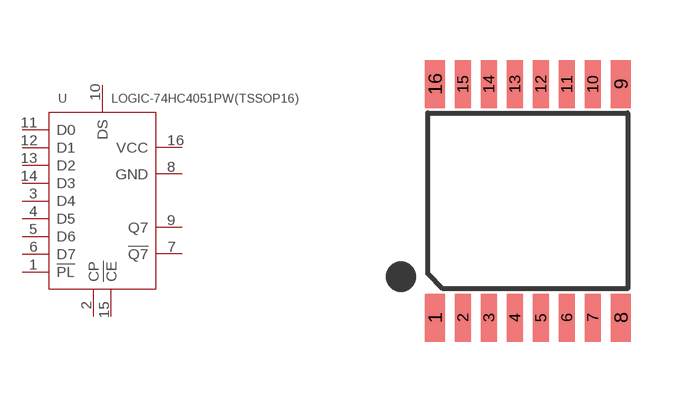
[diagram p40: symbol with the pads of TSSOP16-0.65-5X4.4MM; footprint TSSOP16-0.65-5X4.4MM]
Designator prefix U

## LOGIC-74HC4051PW(TSSOP16) (MPN: 74HC4051PW; VALUE: 74HC4051PW-TSSOP16)  [TSSOP16-0.65-5X4.4MM]
1  !PL  in
2  CP  in
3  D4
4  D5
5  D6
6  D7
7  !Q7
8  GND  sup
9  Q7
10  DS  in
11  D0
12  D1
13  D2
14  D3
15  !CE  in
16  VCC  sup

## Footprint TSSOP16-0.65-5X4.4MM (pad centres in mm)
TSOP16 thin small outline package
smd 0.5 x 1.2: 1 -2.325,-2.925; 8 2.325,-2.925; 9 2.325,2.925; 16 -2.325,2.925
smd 0.4 x 1.2: 2 -1.625,-2.925; 3 -0.975,-2.925; 4 -0.325,-2.925; 5 0.325,-2.925; 6 0.975,-2.925; 7 1.625,-2.925; 10 1.625,2.925; 11 0.975,2.925; 12 0.325,2.925; 13 -0.325,2.925; 14 -0.975,2.925; 15 -1.625,2.925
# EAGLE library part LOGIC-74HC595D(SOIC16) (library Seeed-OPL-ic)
310050009

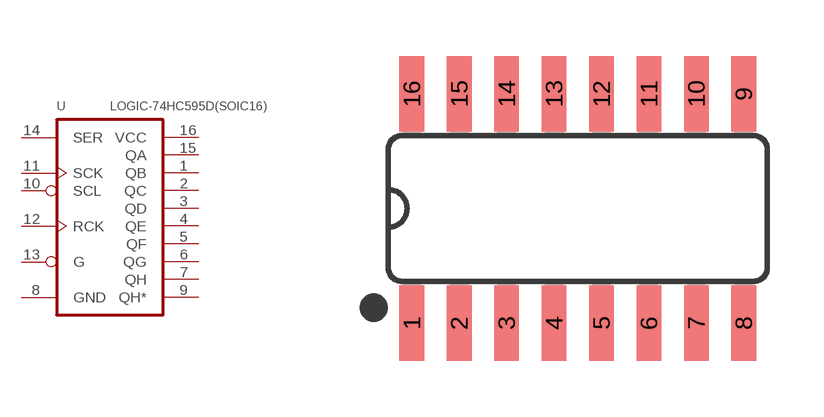
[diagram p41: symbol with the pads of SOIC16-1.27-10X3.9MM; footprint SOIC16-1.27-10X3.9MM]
Designator prefix U

## LOGIC-74HC595D(SOIC16) (MPN: 74HC595D; VALUE: 74HC595D-SOIC16)  [SOIC16-1.27-10X3.9MM]
1  QB  hiz
2  QC  hiz
3  QD  hiz
4  QE  hiz
5  QF  hiz
6  QG  hiz
7  QH  hiz
8  GND  pwr
9  QH*  hiz
10  SCL  in
11  SCK  in
12  RCK  in
13  G  in
14  SER  in
15  QA  hiz
16  VCC  pwr

## Footprint SOIC16-1.27-10X3.9MM (pad centres in mm)
Small Outline package 150 mil
smd 0.66 x 2.032: 1 -4.445,-3.073; 2 -3.175,-3.073; 3 -1.905,-3.073; 4 -0.635,-3.073; 5 0.635,-3.073; 6 1.905,-3.073; 7 3.175,-3.073; 8 4.445,-3.073; 9 4.445,3.073; 10 3.175,3.073; 11 1.905,3.073; 12 0.635,3.073; 13 -0.635,3.073; 14 -1.905,3.073; 15 -3.175,3.073; 16 -4.445,3.073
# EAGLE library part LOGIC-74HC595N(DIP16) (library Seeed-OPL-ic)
310050012

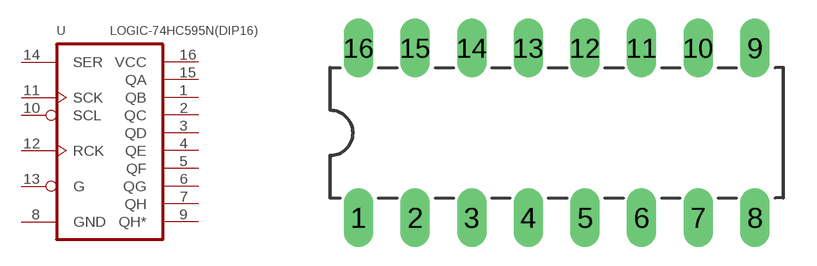
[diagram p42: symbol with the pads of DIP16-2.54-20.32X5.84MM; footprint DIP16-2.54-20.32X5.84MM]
Designator prefix U

## LOGIC-74HC595N(DIP16) (MPN: 74HC595N; VALUE: 74HC595N-DIP16)  [DIP16-2.54-20.32X5.84MM]
1  QB  hiz
2  QC  hiz
3  QD  hiz
4  QE  hiz
5  QF  hiz
6  QG  hiz
7  QH  hiz
8  GND  pwr
9  QH*  hiz
10  SCL  in
11  SCK  in
12  RCK  in
13  G  in
14  SER  in
15  QA  hiz
16  VCC  pwr

## Footprint DIP16-2.54-20.32X5.84MM (pad centres in mm)
Dual In Line Package
drill 0.813 long: 1 -8.89,-3.81; 2 -6.35,-3.81; 3 -3.81,-3.81; 4 -1.27,-3.81; 5 1.27,-3.81; 6 3.81,-3.81; 7 6.35,-3.81; 8 8.89,-3.81; 9 8.89,3.81; 10 6.35,3.81; 11 3.81,3.81; 12 1.27,3.81; 13 -1.27,3.81; 14 -3.81,3.81; 15 -6.35,3.81; 16 -8.89,3.81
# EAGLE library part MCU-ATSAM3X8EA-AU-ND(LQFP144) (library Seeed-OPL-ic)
310010111

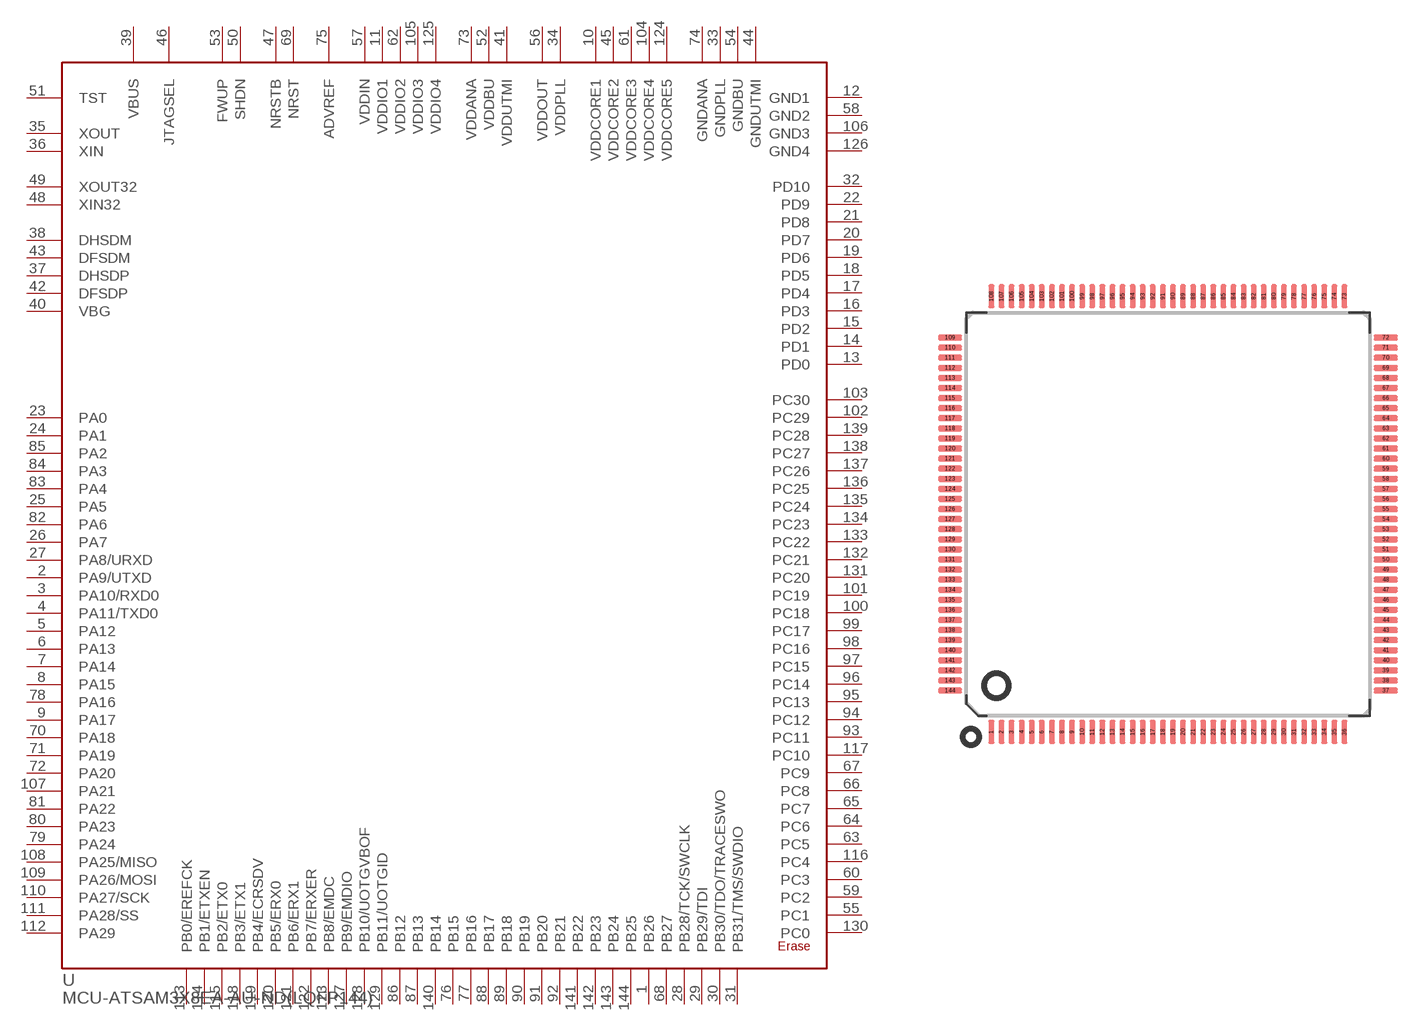
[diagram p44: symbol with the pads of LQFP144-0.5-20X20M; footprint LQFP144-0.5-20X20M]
Designator prefix U

## MCU-ATSAM3X8EA-AU-ND(LQFP144) (MPN: ATSAM3X8EA-AU-ND; VALUE: ATSAM3X8EA-AU-ND-LQFP144)  [LQFP144-0.5-20X20M]
1  PB26
2  PA9/UTXD
3  PA10/RXD0
4  PA11/TXD0
5  PA12
6  PA13
7  PA14
8  PA15
9  PA17
10  VDDCORE1  in
11  VDDIO1  pwr
12  GND1  pwr
13  PD0
14  PD1
15  PD2
16  PD3
17  PD4
18  PD5
19  PD6
20  PD7
21  PD8
22  PD9
23  PA0
24  PA1
25  PA5
26  PA7
27  PA8/URXD
28  PB28/TCK/SWCLK
29  PB29/TDI
30  PB30/TDO/TRACESWO
31  PB31/TMS/SWDIO
32  PD10
33  GNDPLL  pwr
34  VDDPLL  in
35  XOUT  out
36  XIN  in
37  DHSDP
38  DHSDM
39  VBUS  pwr
40  VBG  pas
41  VDDUTMI  in
42  DFSDP  in
43  DFSDM  in
44  GNDUTMI  pwr
45  VDDCORE2  in
46  JTAGSEL  in
47  NRSTB  in
48  XIN32  out
49  XOUT32  out
50  SHDN  out
51  TST  in
52  VDDBU  pwr
53  FWUP  in
54  GNDBU  pwr
55  PC1
56  VDDOUT  out
57  VDDIN  pwr
58  GND2  pwr
59  PC2
60  PC3
61  VDDCORE3  in
62  VDDIO2  pwr
63  PC5
64  PC6
65  PC7
66  PC8
67  PC9
68  PB27
69  NRST
70  PA18
71  PA19
72  PA20
73  VDDANA  pwr
74  GNDANA  pwr
75  ADVREF  pwr
76  PB15
77  PB16
78  PA16
79  PA24
80  PA23
81  PA22
82  PA6
83  PA4
84  PA3
85  PA2
86  PB12
87  PB13
88  PB17
89  PB18
90  PB19
91  PB20
92  PB21
93  PC11
94  PC12
95  PC13
96  PC14
97  PC15
98  PC16
99  PC17
100  PC18
101  PC19
102  PC29
103  PC30
104  VDDCORE4  in
105  VDDIO3  pwr
106  GND3  pwr
107  PA21
108  PA25/MISO
109  PA26/MOSI
110  PA27/SCK
111  PA28/SS
112  PA29
113  PB0/EREFCK
114  PB1/ETXEN
115  PB2/ETX0
116  PC4
117  PC10
118  PB3/ETX1
119  PB4/ECRSDV
120  PB5/ERX0
121  PB6/ERX1
122  PB7/ERXER
123  PB8/EMDC
124  VDDCORE5  in
125  VDDIO4  pwr
126  GND4  pwr
127  PB9/EMDIO
128  PB10/UOTGVBOF
129  PB11/UOTGID
130  PC0
131  PC20
132  PC21
133  PC22
134  PC23
135  PC24
136  PC25
137  PC26
138  PC27
139  PC28
140  PB14
141  PB22
142  PB23
143  PB24
144  PB25

## Footprint LQFP144-0.5-20X20M (pad centres in mm)
QFP144 shrink quad flat pack, square (smd-ipc)
smd 0.3 x 1.2: 1 -8.75,-10.8; 2 -8.25,-10.8; 3 -7.75,-10.8; 4 -7.25,-10.8; 5 -6.75,-10.8; 6 -6.25,-10.8; 7 -5.75,-10.8; 8 -5.25,-10.8; 9 -4.75,-10.8; 10 -4.25,-10.8; 11 -3.75,-10.8; 12 -3.25,-10.8; 13 -2.75,-10.8; 14 -2.25,-10.8; 15 -1.75,-10.8; 16 -1.25,-10.8; 17 -0.75,-10.8; 18 -0.25,-10.8; 19 0.25,-10.8; 20 0.75,-10.8; 21 1.25,-10.8; 22 1.75,-10.8; 23 2.25,-10.8; 24 2.75,-10.8; 25 3.25,-10.8; 26 3.75,-10.8; 27 4.25,-10.8; 28 4.75,-10.8; 29 5.25,-10.8; 30 5.75,-10.8; 31 6.25,-10.8; 32 6.75,-10.8; 33 7.25,-10.8; 34 7.75,-10.8; 35 8.25,-10.8; 36 8.75,-10.8; 73 8.75,10.8; 74 8.25,10.8; 75 7.75,10.8; 76 7.25,10.8; 77 6.75,10.8; 78 6.25,10.8; 79 5.75,10.8; 80 5.25,10.8; 81 4.75,10.8; 82 4.25,10.8; 83 3.75,10.8; 84 3.25,10.8; 85 2.75,10.8; 86 2.25,10.8; 87 1.75,10.8; 88 1.25,10.8; 89 0.75,10.8; 90 0.25,10.8; 91 -0.25,10.8; 92 -0.75,10.8; 93 -1.25,10.8; 94 -1.75,10.8; 95 -2.25,10.8; 96 -2.75,10.8; 97 -3.25,10.8; 98 -3.75,10.8; 99 -4.25,10.8; 100 -4.75,10.8; 101 -5.25,10.8; 102 -5.75,10.8; 103 -6.25,10.8; 104 -6.75,10.8; 105 -7.25,10.8; 106 -7.75,10.8; 107 -8.25,10.8; 108 -8.75,10.8
smd 1.2 x 0.3: 37 10.8,-8.75; 38 10.8,-8.25; 39 10.8,-7.75; 40 10.8,-7.25; 41 10.8,-6.75; 42 10.8,-6.25; 43 10.8,-5.75; 44 10.8,-5.25; 45 10.8,-4.75; 46 10.8,-4.25; 47 10.8,-3.75; 48 10.8,-3.25; 49 10.8,-2.75; 50 10.8,-2.25; 51 10.8,-1.75; 52 10.8,-1.25; 53 10.8,-0.75; 54 10.8,-0.25; 55 10.8,0.25; 56 10.8,0.75; 57 10.8,1.25; 58 10.8,1.75; 59 10.8,2.25; 60 10.8,2.75; 61 10.8,3.25; 62 10.8,3.75; 63 10.8,4.25; 64 10.8,4.75; 65 10.8,5.25; 66 10.8,5.75; 67 10.8,6.25; 68 10.8,6.75; 69 10.8,7.25; 70 10.8,7.75; 71 10.8,8.25; 72 10.8,8.75; 109 -10.8,8.75; 110 -10.8,8.25; 111 -10.8,7.75; 112 -10.8,7.25; 113 -10.8,6.75; 114 -10.8,6.25; 115 -10.8,5.75; 116 -10.8,5.25; 117 -10.8,4.75; 118 -10.8,4.25; 119 -10.8,3.75; 120 -10.8,3.25; 121 -10.8,2.75; 122 -10.8,2.25; 123 -10.8,1.75; 124 -10.8,1.25; 125 -10.8,0.75; 126 -10.8,0.25; 127 -10.8,-0.25; 128 -10.8,-0.75; 129 -10.8,-1.25; 130 -10.8,-1.75; 131 -10.8,-2.25; 132 -10.8,-2.75; 133 -10.8,-3.25; 134 -10.8,-3.75; 135 -10.8,-4.25; 136 -10.8,-4.75; 137 -10.8,-5.25; 138 -10.8,-5.75; 139 -10.8,-6.25; 140 -10.8,-6.75; 141 -10.8,-7.25; 142 -10.8,-7.75; 143 -10.8,-8.25; 144 -10.8,-8.75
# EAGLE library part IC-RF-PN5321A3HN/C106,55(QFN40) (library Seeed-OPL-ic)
310060004

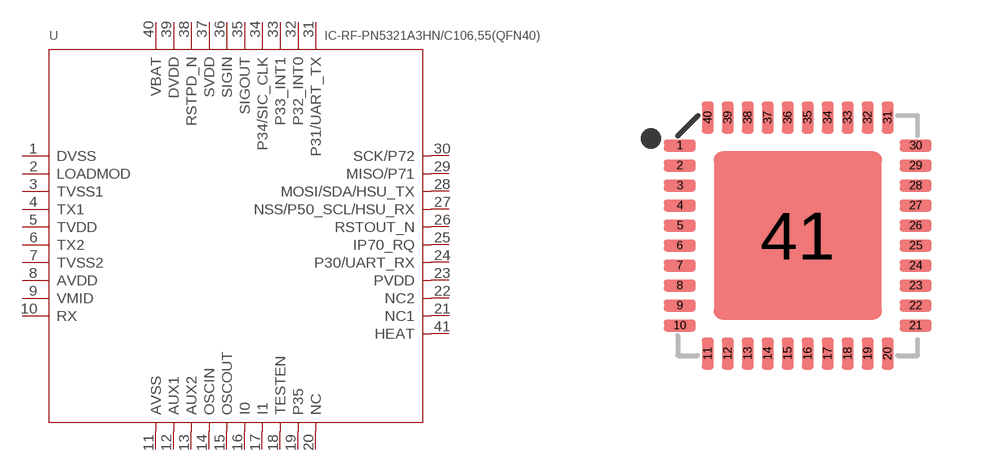
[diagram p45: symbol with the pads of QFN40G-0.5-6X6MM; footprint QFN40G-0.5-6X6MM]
Designator prefix U

## IC-RF-PN5321A3HN/C106,55(QFN40) (MPN: RF-PN5321A3HN/C106,55; VALUE: RF-PN5321A3HN/C106,55-QFN40)  [QFN40G-0.5-6X6MM]
1  DVSS  sup
2  LOADMOD  out
3  TVSS1  sup
4  TX1  out
5  TVDD  sup
6  TX2  out
7  TVSS2  sup
8  AVDD  sup
9  VMID  out
10  RX  in
11  AVSS  sup
12  AUX1  out
13  AUX2  out
14  OSCIN  in
15  OSCOUT  out
16  I0  in
17  I1  in
18  TESTEN  in
19  P35
20  NC  nc
21  NC1  nc
22  NC2  nc
23  PVDD  sup
24  P30/UART_RX
25  IP70_RQ  out
26  RSTOUT_N
27  NSS/P50_SCL/HSU_RX
28  MOSI/SDA/HSU_TX
29  MISO/P71
30  SCK/P72
31  P31/UART_TX
32  P32_INT0
33  P33_INT1
34  P34/SIC_CLK
35  SIGOUT  out
36  SIGIN  in
37  SVDD  sup
38  RSTPD_N  in
39  DVDD  sup
40  VBAT  sup
41  HEAT

## Footprint QFN40G-0.5-6X6MM (pad centres in mm)
smd 0.8 x 0.3: 1 -2.95,2.25; 2 -2.95,1.75; 3 -2.95,1.25; 4 -2.95,0.75; 5 -2.95,0.25; 6 -2.95,-0.25; 7 -2.95,-0.75; 8 -2.95,-1.25; 9 -2.95,-1.75; 10 -2.95,-2.25; 21 2.95,-2.25; 22 2.95,-1.75; 23 2.95,-1.25; 24 2.95,-0.75; 25 2.95,-0.25; 26 2.95,0.25; 27 2.95,0.75; 28 2.95,1.25; 29 2.95,1.75; 30 2.95,2.25
smd 0.3 x 0.8: 11 -2.25,-2.95; 12 -1.75,-2.95; 13 -1.25,-2.95; 14 -0.75,-2.95; 15 -0.25,-2.95; 16 0.25,-2.95; 17 0.75,-2.95; 18 1.25,-2.95; 19 1.75,-2.95; 20 2.25,-2.95; 31 2.25,2.95; 32 1.75,2.95; 33 1.25,2.95; 34 0.75,2.95; 35 0.25,2.95; 36 -0.25,2.95; 37 -0.75,2.95; 38 -1.25,2.95; 39 -1.75,2.95; 40 -2.25,2.95
smd 4.2 x 4.2: 41 0,0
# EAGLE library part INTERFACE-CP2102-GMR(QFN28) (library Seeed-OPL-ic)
310070003

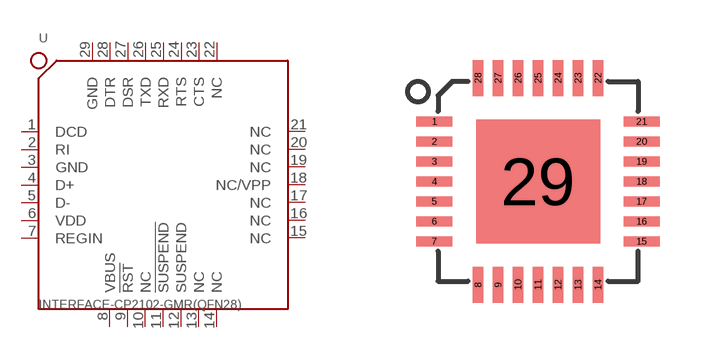
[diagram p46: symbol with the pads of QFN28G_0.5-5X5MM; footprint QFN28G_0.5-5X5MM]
Designator prefix U

## INTERFACE-CP2102-GMR(QFN28) (MPN: CP2102-GMR; VALUE: CP2102-GMR-QFN28)  [QFN28G_0.5-5X5MM]
1  DCD
2  RI
3  GND
4  D+
5  D-
6  VDD
7  REGIN
8  VBUS
9  !RST
10  NC
11  !SUSPEND
12  SUSPEND
13  NC
14  NC
15  NC
16  NC
17  NC
18  NC/VPP
19  NC
20  NC
21  NC
22  NC
23  CTS
24  RTS
25  RXD
26  TXD
27  DSR
28  DTR
29  GND

## Footprint QFN28G_0.5-5X5MM (pad centres in mm)
smd 0.9 x 0.254: 1 -2.59,1.5; 2 -2.59,1; 3 -2.59,0.5; 4 -2.59,0; 5 -2.59,-0.5; 6 -2.59,-1; 7 -2.59,-1.5; 15 2.59,-1.5; 16 2.59,-1; 17 2.59,-0.5; 18 2.59,0; 19 2.59,0.5; 20 2.59,1; 21 2.59,1.5
smd 0.254 x 0.9: 8 -1.5,-2.59; 9 -1,-2.59; 10 -0.5,-2.59; 11 0,-2.59; 12 0.5,-2.59; 13 1,-2.59; 14 1.5,-2.59; 22 1.5,2.59; 23 1,2.59; 24 0.5,2.59; 25 0,2.59; 26 -0.5,2.59; 27 -1,2.59; 28 -1.5,2.59
smd 3.1 x 3.1: 29 0,0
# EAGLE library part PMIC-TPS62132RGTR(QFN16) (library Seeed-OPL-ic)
310030129

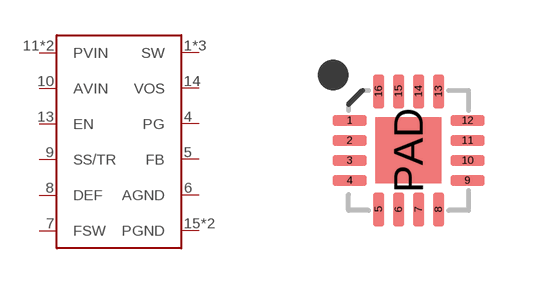
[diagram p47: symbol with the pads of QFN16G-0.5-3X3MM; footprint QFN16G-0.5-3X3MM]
Designator prefix U

## PMIC-TPS62132RGTR(QFN16) (MPN: TPS62132RGTR; VALUE: TPS62132RGTR-QFN16)  [QFN16G-0.5-3X3MM]
1  SW
2  SW
3  SW
4  PG
5  FB
6  AGND
7  FSW
8  DEF
9  SS/TR
10  AVIN
11  PVIN
12  PVIN
13  EN
14  VOS
15  PGND
16  PGND

## Footprint QFN16G-0.5-3X3MM (pad centres in mm)
smd 0.85 x 0.28: 1 -1.475,0.75; 2 -1.475,0.25; 3 -1.475,-0.25; 4 -1.475,-0.75; 9 1.475,-0.75; 10 1.475,-0.25; 11 1.475,0.25; 12 1.475,0.75
smd 0.28 x 0.85: 5 -0.75,-1.475; 6 -0.25,-1.475; 7 0.25,-1.475; 8 0.75,-1.475; 13 0.75,1.475; 14 0.25,1.475; 15 -0.25,1.475; 16 -0.75,1.475
smd 1.65 x 1.65: PAD 0,0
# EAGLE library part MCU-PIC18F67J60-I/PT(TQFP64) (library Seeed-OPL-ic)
310010030

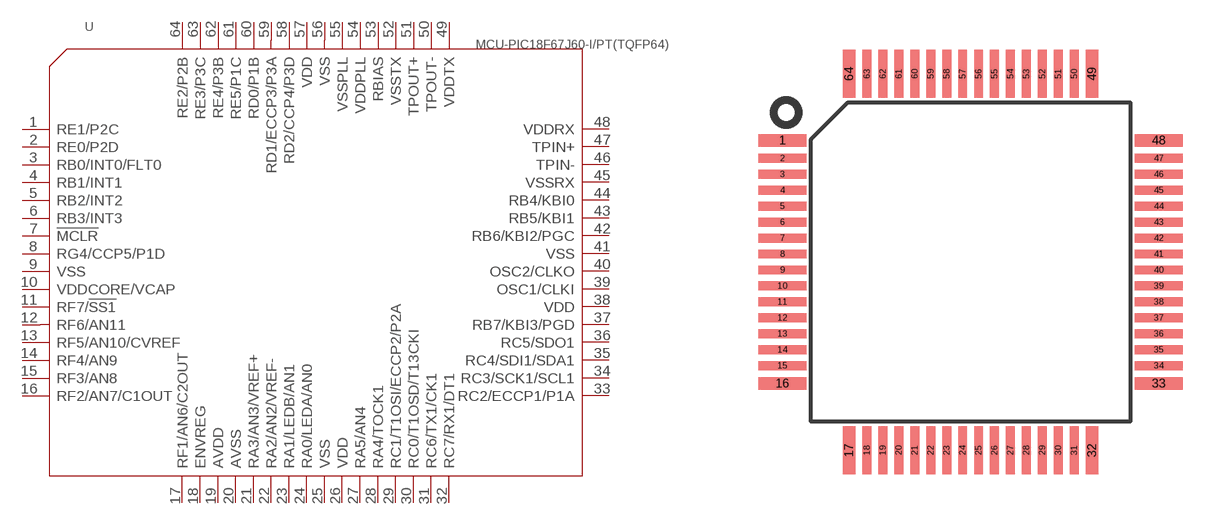
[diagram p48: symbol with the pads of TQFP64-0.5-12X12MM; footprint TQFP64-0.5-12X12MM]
Designator prefix U

## MCU-PIC18F67J60-I/PT(TQFP64) (MPN: PIC18F67J60-I/PT; VALUE: PIC18F67J60-I/PT-TQFP64)  [TQFP64-0.5-12X12MM]
1  RE1/P2C
2  RE0/P2D
3  RB0/INT0/FLT0
4  RB1/INT1
5  RB2/INT2
6  RB3/INT3
7  !MCLR
8  RG4/CCP5/P1D
9  VSS
10  VDDCORE/VCAP
11  RF7/!SS1
12  RF6/AN11
13  RF5/AN10/CVREF
14  RF4/AN9
15  RF3/AN8
16  RF2/AN7/C1OUT
17  RF1/AN6/C2OUT
18  ENVREG
19  AVDD
20  AVSS
21  RA3/AN3/VREF+
22  RA2/AN2/VREF-
23  RA1/LEDB/AN1
24  RA0/LEDA/AN0
25  VSS
26  VDD
27  RA5/AN4
28  RA4/TOCK1
29  RC1/T1OSI/ECCP2/P2A
30  RC0/T1OSD/T13CKI
31  RC6/TX1/CK1
32  RC7/RX1/DT1
33  RC2/ECCP1/P1A
34  RC3/SCK1/SCL1
35  RC4/SDI1/SDA1
36  RC5/SDO1
37  RB7/KBI3/PGD
38  VDD
39  OSC1/CLKI
40  OSC2/CLKO
41  VSS
42  RB6/KBI2/PGC
43  RB5/KBI1
44  RB4/KBI0
45  VSSRX
46  TPIN-
47  TPIN+
48  VDDRX
49  VDDTX
50  TPOUT-
51  TPOUT+
52  VSSTX
53  RBIAS
54  VDDPLL
55  VSSPLL
56  VSS
57  VDD
58  RD2/CCP4/P3D
59  RD1/ECCP3/P3A
60  RD0/P1B
61  RE5/P1C
62  RE4/P3B
63  RE3/P3C
64  RE2/P2B

## Footprint TQFP64-0.5-12X12MM (pad centres in mm)
smd 1.5 x 0.4: 1 -5.9,3.81; 16 -5.9,-3.81; 33 5.9,-3.81; 48 5.9,3.81
smd 1.5 x 0.28: 2 -5.9,3.25; 3 -5.9,2.75; 4 -5.9,2.25; 5 -5.9,1.75; 6 -5.9,1.25; 7 -5.9,0.75; 8 -5.9,0.25; 9 -5.9,-0.25; 10 -5.9,-0.75; 11 -5.9,-1.25; 12 -5.9,-1.75; 13 -5.9,-2.25; 14 -5.9,-2.75; 15 -5.9,-3.25; 34 5.9,-3.25; 35 5.9,-2.75; 36 5.9,-2.25; 37 5.9,-1.75; 38 5.9,-1.25; 39 5.9,-0.75; 40 5.9,-0.25; 41 5.9,0.25; 42 5.9,0.75; 43 5.9,1.25; 44 5.9,1.75; 45 5.9,2.25; 46 5.9,2.75; 47 5.9,3.25
smd 0.4 x 1.5: 17 -3.81,-5.9; 32 3.81,-5.9; 49 3.81,5.9; 64 -3.81,5.9
smd 0.28 x 1.5: 18 -3.25,-5.9; 19 -2.75,-5.9; 20 -2.25,-5.9; 21 -1.75,-5.9; 22 -1.25,-5.9; 23 -0.75,-5.9; 24 -0.25,-5.9; 25 0.25,-5.9; 26 0.75,-5.9; 27 1.25,-5.9; 28 1.75,-5.9; 29 2.25,-5.9; 30 2.75,-5.9; 31 3.25,-5.9; 50 3.25,5.9; 51 2.75,5.9; 52 2.25,5.9; 53 1.75,5.9; 54 1.25,5.9; 55 0.75,5.9; 56 0.25,5.9; 57 -0.25,5.9; 58 -0.75,5.9; 59 -1.25,5.9; 60 -1.75,5.9; 61 -2.25,5.9; 62 -2.75,5.9; 63 -3.25,5.9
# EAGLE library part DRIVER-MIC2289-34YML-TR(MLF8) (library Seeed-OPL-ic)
310040006

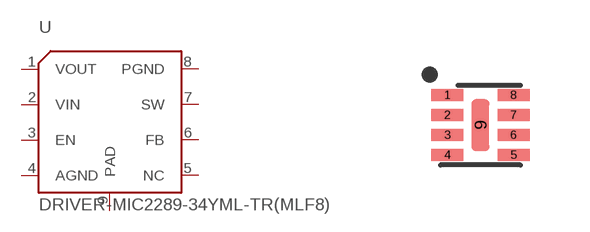
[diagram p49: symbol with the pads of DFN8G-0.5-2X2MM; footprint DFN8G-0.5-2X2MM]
Designator prefix U

## DRIVER-MIC2289-34YML-TR(MLF8) (MPN: MIC2289-34YML-TR; VALUE: MIC2289-34YML-TR-MLF8)  [DFN8G-0.5-2X2MM]
1  VOUT
2  VIN
3  EN
4  AGND
5  NC
6  FB
7  SW
8  PGND
9  PAD

## Footprint DFN8G-0.5-2X2MM (pad centres in mm)
smd 0.8 x 0.3: 1 -0.827,0.75; 2 -0.827,0.25; 3 -0.827,-0.25; 4 -0.827,-0.75; 5 0.827,-0.75; 6 0.827,-0.25; 7 0.827,0.25; 8 0.827,0.75
smd 0.45 x 1.3: 9 0,0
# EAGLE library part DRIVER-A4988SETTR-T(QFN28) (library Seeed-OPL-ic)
310040028

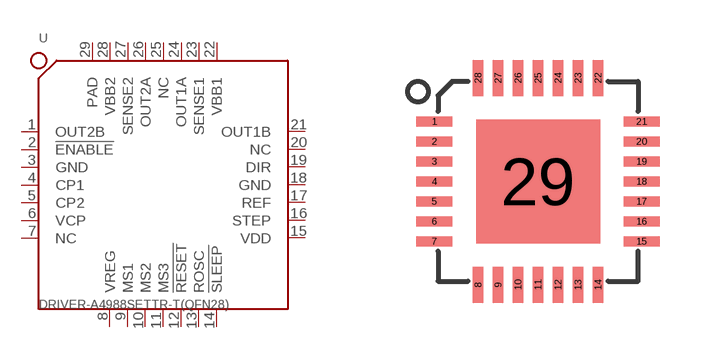
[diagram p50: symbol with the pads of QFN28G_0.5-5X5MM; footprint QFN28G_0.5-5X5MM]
Designator prefix U

## DRIVER-A4988SETTR-T(QFN28) (MPN: A4988SETTR-T; VALUE: A4988SETTR-QFN28)  [QFN28G_0.5-5X5MM]
1  OUT2B
2  !ENABLE
3  GND
4  CP1
5  CP2
6  VCP
7  NC
8  VREG
9  MS1
10  MS2
11  MS3
12  !RESET
13  ROSC
14  !SLEEP
15  VDD
16  STEP
17  REF
18  GND
19  DIR
20  NC
21  OUT1B
22  VBB1
23  SENSE1
24  OUT1A
25  NC
26  OUT2A
27  SENSE2
28  VBB2
29  PAD

## Footprint QFN28G_0.5-5X5MM (pad centres in mm)
smd 0.9 x 0.254: 1 -2.59,1.5; 2 -2.59,1; 3 -2.59,0.5; 4 -2.59,0; 5 -2.59,-0.5; 6 -2.59,-1; 7 -2.59,-1.5; 15 2.59,-1.5; 16 2.59,-1; 17 2.59,-0.5; 18 2.59,0; 19 2.59,0.5; 20 2.59,1; 21 2.59,1.5
smd 0.254 x 0.9: 8 -1.5,-2.59; 9 -1,-2.59; 10 -0.5,-2.59; 11 0,-2.59; 12 0.5,-2.59; 13 1,-2.59; 14 1.5,-2.59; 22 1.5,2.59; 23 1,2.59; 24 0.5,2.59; 25 0,2.59; 26 -0.5,2.59; 27 -1,2.59; 28 -1.5,2.59
smd 3.1 x 3.1: 29 0,0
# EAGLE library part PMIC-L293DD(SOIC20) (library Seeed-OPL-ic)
310030087

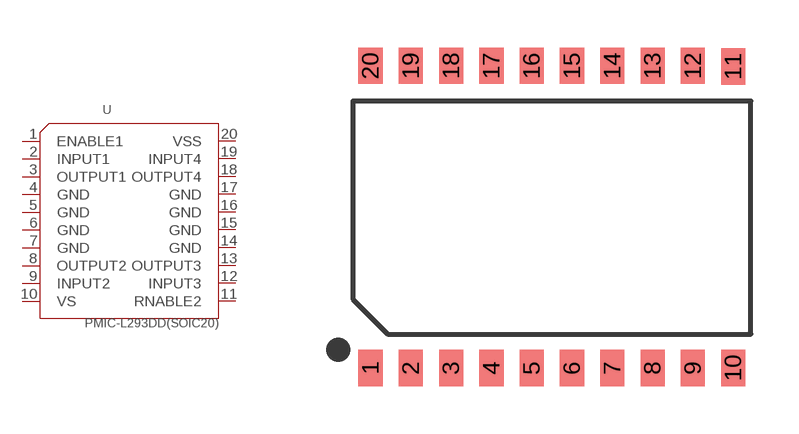
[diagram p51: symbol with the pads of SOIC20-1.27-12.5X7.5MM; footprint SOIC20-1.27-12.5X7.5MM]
Designator prefix U

## PMIC-L293DD(SOIC20) (MPN: L293DD; VALUE: L293D-SOIC20)  [SOIC20-1.27-12.5X7.5MM]
1  ENABLE1
2  INPUT1
3  OUTPUT1
4  GND
5  GND
6  GND
7  GND
8  OUTPUT2
9  INPUT2
10  VS
11  RNABLE2
12  INPUT3
13  OUTPUT3
14  GND
15  GND
16  GND
17  GND
18  OUTPUT4
19  INPUT4
20  VSS

## Footprint SOIC20-1.27-12.5X7.5MM (pad centres in mm)
Small Outline Package
smd 0.762 x 1.143: 1 -5.715,-4.75; 2 -4.445,-4.75; 3 -3.175,-4.75; 4 -1.905,-4.75; 5 -0.635,-4.75; 6 0.635,-4.75; 7 1.905,-4.75; 8 3.175,-4.75; 9 4.445,-4.75; 10 5.715,-4.75; 11 5.715,4.75; 12 4.445,4.775; 13 3.175,4.775; 14 1.905,4.775; 15 0.635,4.775; 16 -0.635,4.775; 17 -1.905,4.775; 18 -3.175,4.775; 19 -4.445,4.775; 20 -5.715,4.775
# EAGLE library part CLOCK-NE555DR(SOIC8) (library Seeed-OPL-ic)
310110013

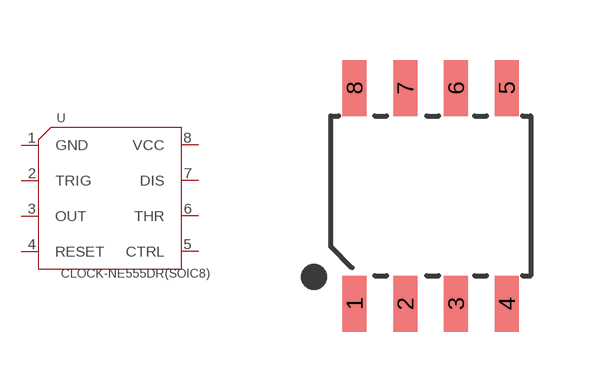
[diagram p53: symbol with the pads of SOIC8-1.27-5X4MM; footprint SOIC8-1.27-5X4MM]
Designator prefix U

## CLOCK-NE555DR(SOIC8) (MPN: NE555DR; VALUE: NE555DR-SOIC8)  [SOIC8-1.27-5X4MM]
1  GND
2  TRIG
3  OUT
4  RESET
5  CTRL
6  THR
7  DIS
8  VCC

## Footprint SOIC8-1.27-5X4MM (pad centres in mm)
smd 0.6 x 1.4: 1 -1.905,-2.7; 2 -0.635,-2.7; 3 0.635,-2.7; 4 1.905,-2.7; 5 1.905,2.7; 6 0.635,2.7; 7 -0.635,2.7; 8 -1.905,2.7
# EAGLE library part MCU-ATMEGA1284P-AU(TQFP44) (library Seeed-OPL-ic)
310010020

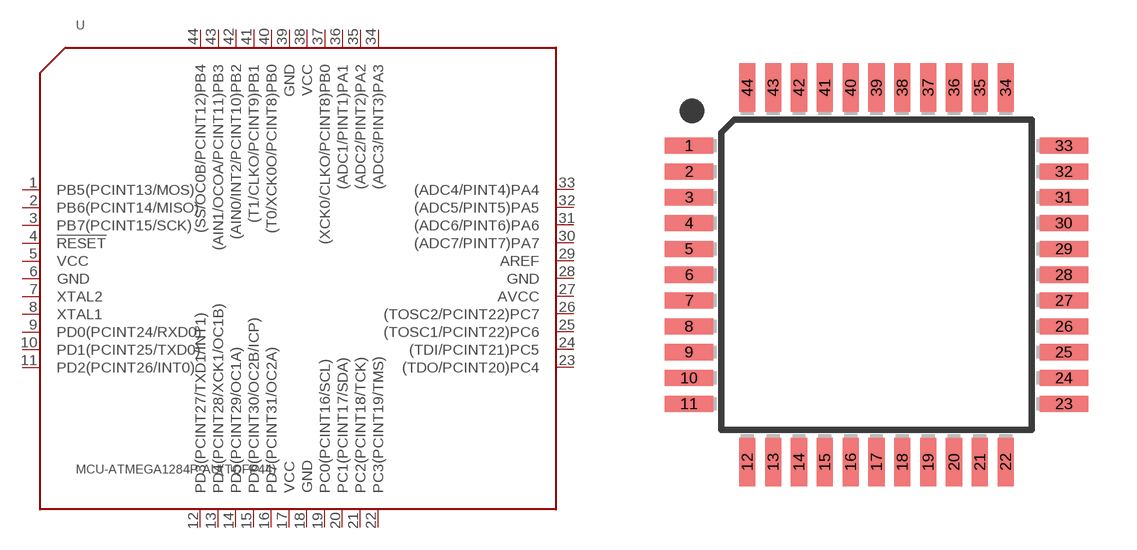
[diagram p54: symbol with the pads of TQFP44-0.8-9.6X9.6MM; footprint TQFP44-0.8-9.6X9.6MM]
Designator prefix U

## MCU-ATMEGA1284P-AU(TQFP44) (MPN: ATMEGA1284P-AU; VALUE: ATMEGA1284P-AU-TQFP44)  [TQFP44-0.8-9.6X9.6MM]
1  PB5(PCINT13/MOS)
2  PB6(PCINT14/MISO)
3  PB7(PCINT15/SCK)
4  !RESET
5  VCC
6  GND
7  XTAL2
8  XTAL1
9  PD0(PCINT24/RXD0)
10  PD1(PCINT25/TXD0)
11  PD2(PCINT26/INT0)
12  PD3(PCINT27/TXD1/INT1)
13  PD4(PCINT28/XCK1/OC1B)
14  PD5(PCINT29/OC1A)
15  PD6(PCINT30/OC2B/ICP)
16  PD7(PCINT31/OC2A)
17  VCC
18  GND
19  PC0(PCINT16/SCL)
20  PC1(PCINT17/SDA)
21  PC2(PCINT18/TCK)
22  PC3(PCINT19/TMS)
23  (TDO/PCINT20)PC4
24  (TDI/PCINT21)PC5
25  (TOSC1/PCINT22)PC6
26  (TOSC2/PCINT22)PC7
27  AVCC
28  GND
29  AREF
30  (ADC7/PINT7)PA7
31  (ADC6/PINT6)PA6
32  (ADC5/PINT5)PA5
33  (ADC4/PINT4)PA4
34  (ADC3/PINT3)PA3
35  (ADC2/PINT2)PA2
36  (ADC1/PINT1)PA1
37  (XCK0/CLKO/PCINT8)PB0
38  VCC
39  GND
40  (T0/XCK0O/PCINT8)PB0
41  (T1/CLKO/PCINT9)PB1
42  (AIN0/INT2/PCINT10)PB2
43  (AIN1/OCOA/PCINT11)PB3
44  (SS/OC0B/PCINT12)PB4

## Footprint TQFP44-0.8-9.6X9.6MM (pad centres in mm)
Thin Plasic Quad Flat Package
smd 1.5 x 0.5: 1 -5.8,4; 2 -5.8,3.2; 3 -5.8,2.4; 4 -5.8,1.6; 5 -5.8,0.8; 6 -5.8,0; 7 -5.8,-0.8; 8 -5.8,-1.6; 9 -5.8,-2.4; 10 -5.8,-3.2; 11 -5.8,-4; 23 5.8,-4; 24 5.8,-3.2; 25 5.8,-2.4; 26 5.8,-1.6; 27 5.8,-0.8; 28 5.8,0; 29 5.8,0.8; 30 5.8,1.6; 31 5.8,2.4; 32 5.8,3.2; 33 5.8,4
smd 0.5 x 1.5: 12 -4,-5.8; 13 -3.2,-5.8; 14 -2.4,-5.8; 15 -1.6,-5.8; 16 -0.8,-5.8; 17 0,-5.8; 18 0.8,-5.8; 19 1.6,-5.8; 20 2.4,-5.8; 21 3.2,-5.8; 22 4,-5.8; 34 4,5.8; 35 3.2,5.8; 36 2.4,5.8; 37 1.6,5.8; 38 0.8,5.8; 39 0,5.8; 40 -0.8,5.8; 41 -1.6,5.8; 42 -2.4,5.8; 43 -3.2,5.8; 44 -4,5.8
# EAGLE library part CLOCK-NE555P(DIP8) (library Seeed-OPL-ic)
310110001

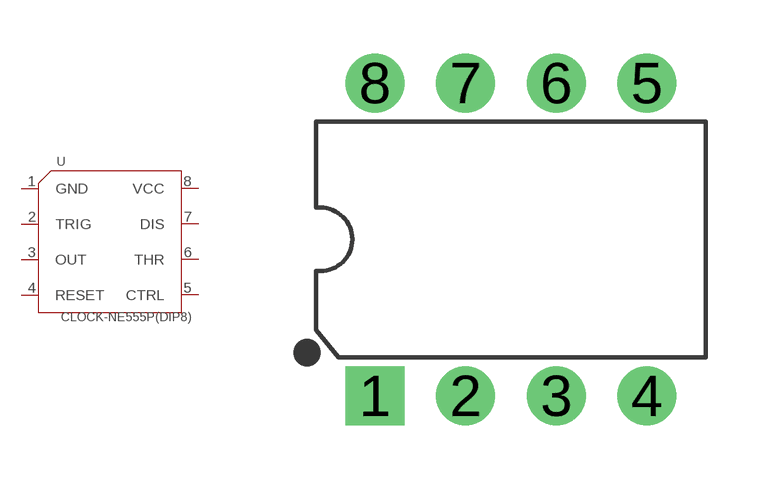
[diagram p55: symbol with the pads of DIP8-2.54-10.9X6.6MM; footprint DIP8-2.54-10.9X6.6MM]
Designator prefix U

## CLOCK-NE555P(DIP8) (MPN: NE555P; VALUE: NE555P-DIP8)  [DIP8-2.54-10.9X6.6MM]
1  GND
2  TRIG
3  OUT
4  RESET
5  CTRL
6  THR
7  DIS
8  VCC

## Footprint DIP8-2.54-10.9X6.6MM (pad centres in mm)
drill 0.889 pad 1.651 square: 1 -3.81,-4.381
drill 0.889 pad 1.651: 2 -1.27,-4.381; 3 1.27,-4.381; 4 3.81,-4.381; 5 3.81,4.381; 6 1.27,4.381; 7 -1.27,4.381; 8 -3.81,4.381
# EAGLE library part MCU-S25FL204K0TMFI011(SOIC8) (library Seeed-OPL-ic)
310090064

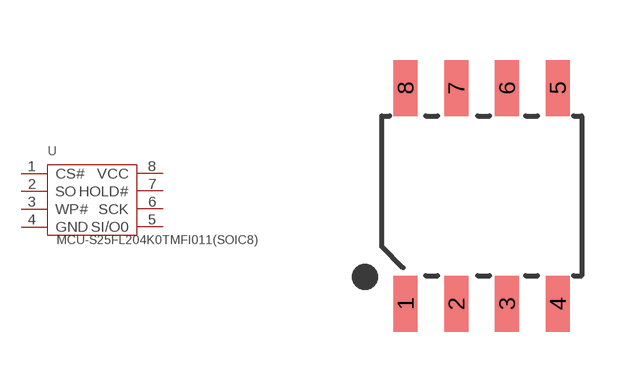
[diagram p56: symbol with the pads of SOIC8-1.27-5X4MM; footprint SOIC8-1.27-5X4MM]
Designator prefix U

## MCU-S25FL204K0TMFI011(SOIC8) (MPN: S25FL204K0TMFI011; VALUE: S25FL204K0TMFI011-SOIC8)  [SOIC8-1.27-5X4MM]
1  CS#
2  SO
3  WP#
4  GND
5  SI/O0
6  SCK
7  HOLD#
8  VCC

## Footprint SOIC8-1.27-5X4MM (pad centres in mm)
smd 0.6 x 1.4: 1 -1.905,-2.7; 2 -0.635,-2.7; 3 0.635,-2.7; 4 1.905,-2.7; 5 1.905,2.7; 6 0.635,2.7; 7 -0.635,2.7; 8 -1.905,2.7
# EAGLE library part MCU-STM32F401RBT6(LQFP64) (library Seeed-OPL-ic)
310010113

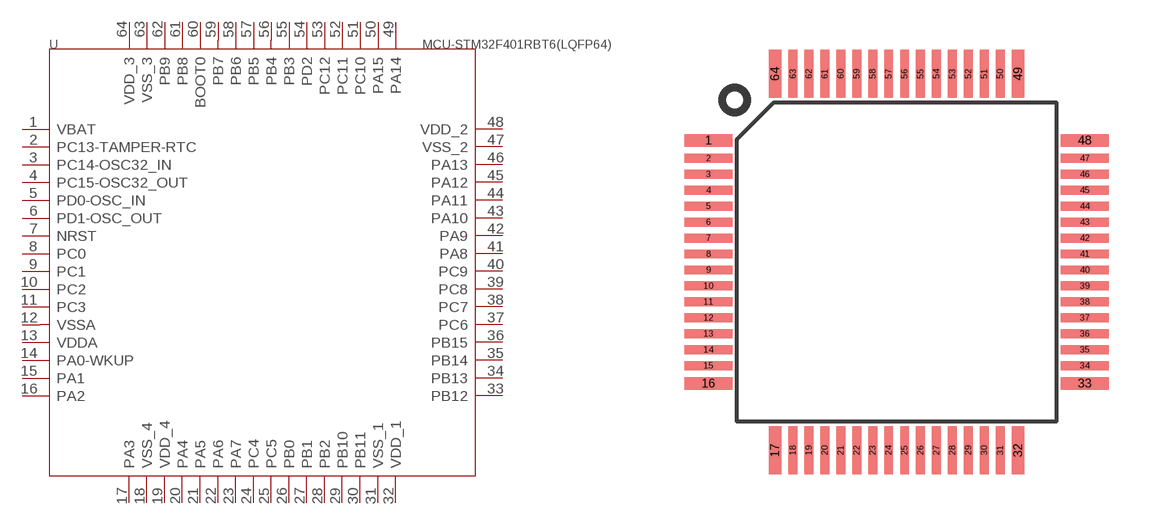
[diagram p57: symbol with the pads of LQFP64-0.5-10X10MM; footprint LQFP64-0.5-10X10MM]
Designator prefix -

## MCU-STM32F401RBT6(LQFP64) (MPN: STM32F401RBT6; VALUE: STM32F401RBT6-LQFP64)  [LQFP64-0.5-10X10MM]
1  VBAT
2  PC13-TAMPER-RTC
3  PC14-OSC32_IN
4  PC15-OSC32_OUT
5  PD0-OSC_IN
6  PD1-OSC_OUT
7  NRST
8  PC0
9  PC1
10  PC2
11  PC3
12  VSSA
13  VDDA
14  PA0-WKUP
15  PA1
16  PA2
17  PA3
18  VSS_4
19  VDD_4
20  PA4
21  PA5
22  PA6
23  PA7
24  PC4
25  PC5
26  PB0
27  PB1
28  PB2
29  PB10
30  PB11
31  VSS_1
32  VDD_1
33  PB12
34  PB13
35  PB14
36  PB15
37  PC6
38  PC7
39  PC8
40  PC9
41  PA8
42  PA9
43  PA10
44  PA11
45  PA12
46  PA13
47  VSS_2
48  VDD_2
49  PA14
50  PA15
51  PC10
52  PC11
53  PC12
54  PD2
55  PB3
56  PB4
57  PB5
58  PB6
59  PB7
60  BOOT0
61  PB8
62  PB9
63  VSS_3
64  VDD_3

## Footprint LQFP64-0.5-10X10MM (pad centres in mm)
smd 1.5 x 0.4: 1 -5.9,3.81; 16 -5.9,-3.81; 33 5.9,-3.81; 48 5.9,3.81
smd 1.5 x 0.28: 2 -5.9,3.25; 3 -5.9,2.75; 4 -5.9,2.25; 5 -5.9,1.75; 6 -5.9,1.25; 7 -5.9,0.75; 8 -5.9,0.25; 9 -5.9,-0.25; 10 -5.9,-0.75; 11 -5.9,-1.25; 12 -5.9,-1.75; 13 -5.9,-2.25; 14 -5.9,-2.75; 15 -5.9,-3.25; 34 5.9,-3.25; 35 5.9,-2.75; 36 5.9,-2.25; 37 5.9,-1.75; 38 5.9,-1.25; 39 5.9,-0.75; 40 5.9,-0.25; 41 5.9,0.25; 42 5.9,0.75; 43 5.9,1.25; 44 5.9,1.75; 45 5.9,2.25; 46 5.9,2.75; 47 5.9,3.25
smd 0.4 x 1.5: 17 -3.81,-5.9; 32 3.81,-5.9; 49 3.81,5.9; 64 -3.81,5.9
smd 0.28 x 1.5: 18 -3.25,-5.9; 19 -2.75,-5.9; 20 -2.25,-5.9; 21 -1.75,-5.9; 22 -1.25,-5.9; 23 -0.75,-5.9; 24 -0.25,-5.9; 25 0.25,-5.9; 26 0.75,-5.9; 27 1.25,-5.9; 28 1.75,-5.9; 29 2.25,-5.9; 30 2.75,-5.9; 31 3.25,-5.9; 50 3.25,5.9; 51 2.75,5.9; 52 2.25,5.9; 53 1.75,5.9; 54 1.25,5.9; 55 0.75,5.9; 56 0.25,5.9; 57 -0.25,5.9; 58 -0.75,5.9; 59 -1.25,5.9; 60 -1.75,5.9; 61 -2.25,5.9; 62 -2.75,5.9; 63 -3.25,5.9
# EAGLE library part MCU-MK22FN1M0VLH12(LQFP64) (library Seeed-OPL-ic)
310010114

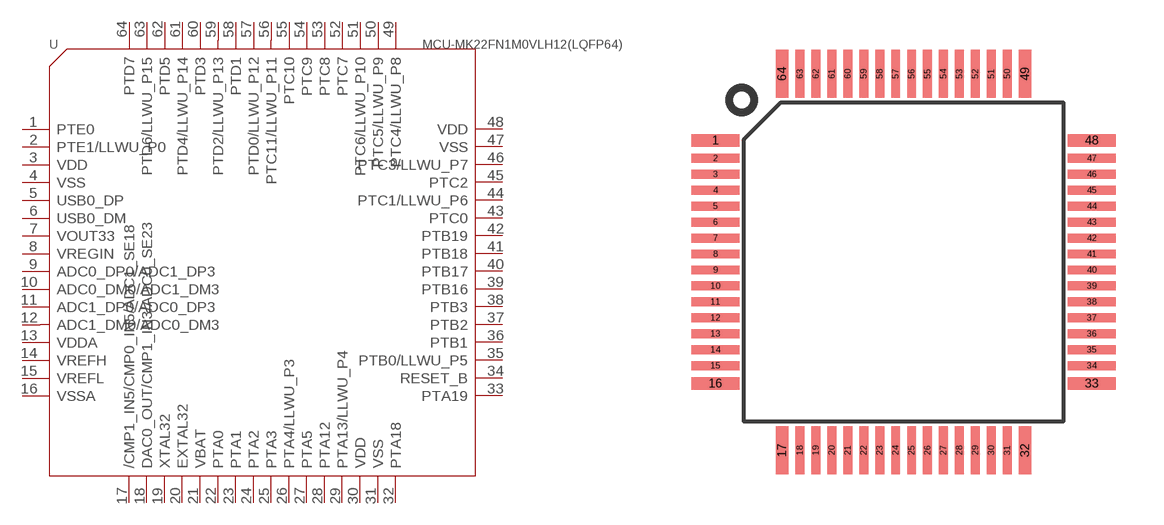
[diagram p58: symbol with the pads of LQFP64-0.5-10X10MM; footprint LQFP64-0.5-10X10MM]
Designator prefix U

## MCU-MK22FN1M0VLH12(LQFP64) (MPN: MK22FN1M0VLH12; VALUE: MK22FN1M0VLH12-LQFP64)  [LQFP64-0.5-10X10MM]
1  PTE0
2  PTE1/LLWU_P0
3  VDD
4  VSS
5  USB0_DP
6  USB0_DM
7  VOUT33
8  VREGIN
9  ADC0_DP0/ADC1_DP3
10  ADC0_DM0/ADC1_DM3
11  ADC1_DP0/ADC0_DP3
12  ADC1_DM0/ADC0_DM3
13  VDDA
14  VREFH
15  VREFL
16  VSSA
17  /CMP1_IN5/CMP0_IN5/ADC1_SE18
18  DAC0_OUT/CMP1_IN3/ADC0_SE23
19  XTAL32
20  EXTAL32
21  VBAT
22  PTA0
23  PTA1
24  PTA2
25  PTA3
26  PTA4/LLWU_P3
27  PTA5
28  PTA12
29  PTA13/LLWU_P4
30  VDD
31  VSS
32  PTA18
33  PTA19
34  RESET_B
35  PTB0/LLWU_P5
36  PTB1
37  PTB2
38  PTB3
39  PTB16
40  PTB17
41  PTB18
42  PTB19
43  PTC0
44  PTC1/LLWU_P6
45  PTC2
46  PTC3/LLWU_P7
47  VSS
48  VDD
49  PTC4/LLWU_P8
50  PTC5/LLWU_P9
51  PTC6/LLWU_P10
52  PTC7
53  PTC8
54  PTC9
55  PTC10
56  PTC11/LLWU_P11
57  PTD0/LLWU_P12
58  PTD1
59  PTD2/LLWU_P13
60  PTD3
61  PTD4/LLWU_P14
62  PTD5
63  PTD6/LLWU_P15
64  PTD7

## Footprint LQFP64-0.5-10X10MM (pad centres in mm)
smd 1.5 x 0.4: 1 -5.9,3.81; 16 -5.9,-3.81; 33 5.9,-3.81; 48 5.9,3.81
smd 1.5 x 0.28: 2 -5.9,3.25; 3 -5.9,2.75; 4 -5.9,2.25; 5 -5.9,1.75; 6 -5.9,1.25; 7 -5.9,0.75; 8 -5.9,0.25; 9 -5.9,-0.25; 10 -5.9,-0.75; 11 -5.9,-1.25; 12 -5.9,-1.75; 13 -5.9,-2.25; 14 -5.9,-2.75; 15 -5.9,-3.25; 34 5.9,-3.25; 35 5.9,-2.75; 36 5.9,-2.25; 37 5.9,-1.75; 38 5.9,-1.25; 39 5.9,-0.75; 40 5.9,-0.25; 41 5.9,0.25; 42 5.9,0.75; 43 5.9,1.25; 44 5.9,1.75; 45 5.9,2.25; 46 5.9,2.75; 47 5.9,3.25
smd 0.4 x 1.5: 17 -3.81,-5.9; 32 3.81,-5.9; 49 3.81,5.9; 64 -3.81,5.9
smd 0.28 x 1.5: 18 -3.25,-5.9; 19 -2.75,-5.9; 20 -2.25,-5.9; 21 -1.75,-5.9; 22 -1.25,-5.9; 23 -0.75,-5.9; 24 -0.25,-5.9; 25 0.25,-5.9; 26 0.75,-5.9; 27 1.25,-5.9; 28 1.75,-5.9; 29 2.25,-5.9; 30 2.75,-5.9; 31 3.25,-5.9; 50 3.25,5.9; 51 2.75,5.9; 52 2.25,5.9; 53 1.75,5.9; 54 1.25,5.9; 55 0.75,5.9; 56 0.25,5.9; 57 -0.25,5.9; 58 -0.75,5.9; 59 -1.25,5.9; 60 -1.75,5.9; 61 -2.25,5.9; 62 -2.75,5.9; 63 -3.25,5.9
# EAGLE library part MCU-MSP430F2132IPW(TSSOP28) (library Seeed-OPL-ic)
310010115

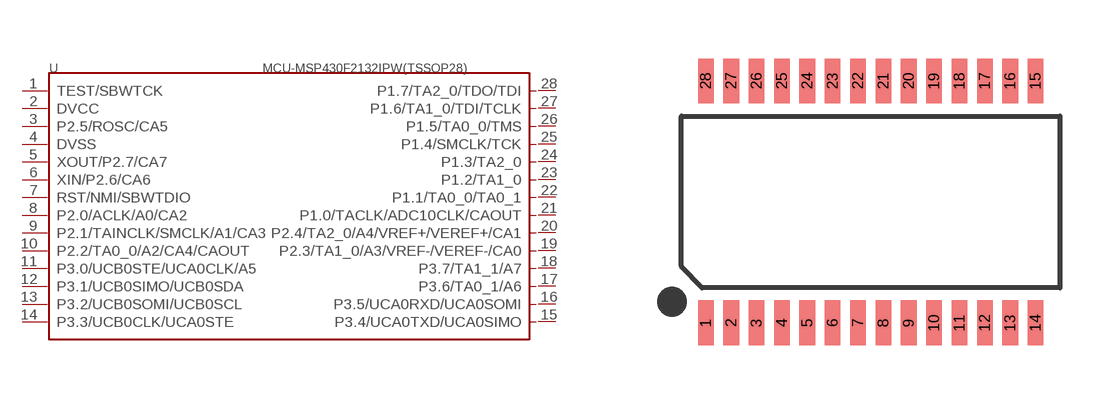
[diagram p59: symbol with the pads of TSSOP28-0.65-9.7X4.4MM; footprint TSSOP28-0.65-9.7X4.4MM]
Designator prefix U

## MCU-MSP430F2132IPW(TSSOP28) (MPN: MSP430F2132IPW; VALUE: MSP430F2132IPW-TSSOP28)  [TSSOP28-0.65-9.7X4.4MM]
1  TEST/SBWTCK
2  DVCC
3  P2.5/ROSC/CA5
4  DVSS
5  XOUT/P2.7/CA7
6  XIN/P2.6/CA6
7  RST/NMI/SBWTDIO
8  P2.0/ACLK/A0/CA2
9  P2.1/TAINCLK/SMCLK/A1/CA3
10  P2.2/TA0_0/A2/CA4/CAOUT
11  P3.0/UCB0STE/UCA0CLK/A5
12  P3.1/UCB0SIMO/UCB0SDA
13  P3.2/UCB0SOMI/UCB0SCL
14  P3.3/UCB0CLK/UCA0STE
15  P3.4/UCA0TXD/UCA0SIMO
16  P3.5/UCA0RXD/UCA0SOMI
17  P3.6/TA0_1/A6
18  P3.7/TA1_1/A7
19  P2.3/TA1_0/A3/VREF-/VEREF-/CA0
20  P2.4/TA2_0/A4/VREF+/VEREF+/CA1
21  P1.0/TACLK/ADC10CLK/CAOUT
22  P1.1/TA0_0/TA0_1
23  P1.2/TA1_0
24  P1.3/TA2_0
25  P1.4/SMCLK/TCK
26  P1.5/TA0_0/TMS
27  P1.6/TA1_0/TDI/TCLK
28  P1.7/TA2_0/TDO/TDI

## Footprint TSSOP28-0.65-9.7X4.4MM (pad centres in mm)
smd 0.4 x 1.15: 1 -4.225,-3.1; 2 -3.575,-3.1; 3 -2.925,-3.1; 4 -2.275,-3.1; 5 -1.625,-3.1; 6 -0.975,-3.1; 7 -0.325,-3.1; 8 0.325,-3.1; 9 0.975,-3.1; 10 1.625,-3.1; 11 2.275,-3.1; 12 2.925,-3.1; 13 3.575,-3.1; 14 4.225,-3.1; 15 4.225,3.1; 16 3.575,3.1; 17 2.925,3.1; 18 2.275,3.1; 19 1.625,3.1; 20 0.975,3.1; 21 0.325,3.1; 22 -0.325,3.1; 23 -0.975,3.1; 24 -1.625,3.1; 25 -2.275,3.1; 26 -2.925,3.1; 27 -3.575,3.1; 28 -4.225,3.1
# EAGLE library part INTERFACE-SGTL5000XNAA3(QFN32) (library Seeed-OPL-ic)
310080005

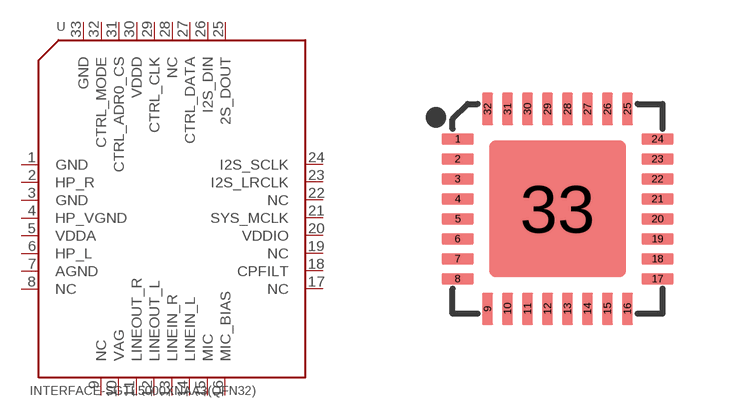
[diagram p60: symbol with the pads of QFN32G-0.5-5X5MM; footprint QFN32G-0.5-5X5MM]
Designator prefix U

## INTERFACE-SGTL5000XNAA3(QFN32) (MPN: SGTL5000XNAA3; VALUE: SGTL5000XNAA3-QFN32)  [QFN32G-0.5-5X5MM]
1  GND
2  HP_R
3  GND
4  HP_VGND
5  VDDA
6  HP_L
7  AGND
8  NC
9  NC
10  VAG
11  LINEOUT_R
12  LINEOUT_L
13  LINEIN_R
14  LINEIN_L
15  MIC
16  MIC_BIAS
17  NC
18  CPFILT
19  NC
20  VDDIO
21  SYS_MCLK
22  NC
23  I2S_LRCLK
24  I2S_SCLK
25  2S_DOUT
26  I2S_DIN
27  CTRL_DATA
28  NC
29  CTRL_CLK
30  VDDD
31  CTRL_ADR0_CS
32  CTRL_MODE
33  GND

## Footprint QFN32G-0.5-5X5MM (pad centres in mm)
smd 0.813 x 0.279: 1 -2.5,1.75; 2 -2.5,1.25; 3 -2.5,0.75; 4 -2.5,0.25; 5 -2.5,-0.25; 6 -2.5,-0.75; 7 -2.5,-1.25; 8 -2.5,-1.75; 17 2.5,-1.75; 18 2.5,-1.25; 19 2.5,-0.75; 20 2.5,-0.25; 21 2.5,0.25; 22 2.5,0.75; 23 2.5,1.25; 24 2.5,1.75
smd 0.279 x 0.813: 9 -1.75,-2.5; 10 -1.25,-2.5; 11 -0.75,-2.5; 12 -0.25,-2.5; 13 0.25,-2.5; 14 0.75,-2.5; 15 1.25,-2.5; 16 1.75,-2.5; 25 1.75,2.5; 26 1.25,2.5; 27 0.75,2.5; 28 0.25,2.5; 29 -0.25,2.5; 30 -0.75,2.5; 31 -1.25,2.5; 32 -1.75,2.5
smd 3.429 x 3.429: 33 0,0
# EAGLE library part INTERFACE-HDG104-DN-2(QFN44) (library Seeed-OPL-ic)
317070014

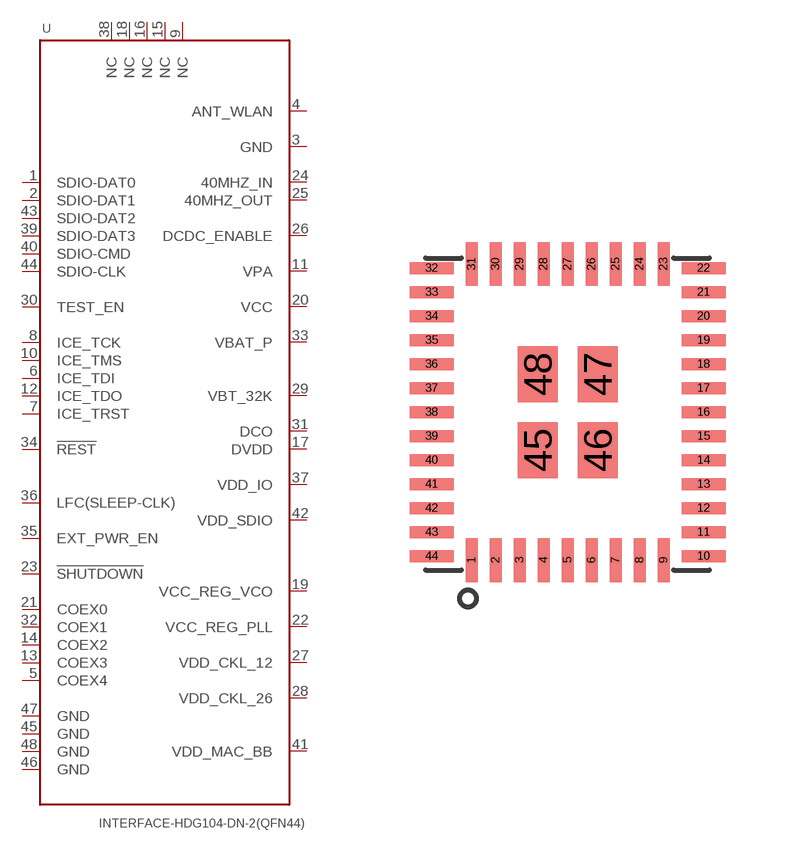
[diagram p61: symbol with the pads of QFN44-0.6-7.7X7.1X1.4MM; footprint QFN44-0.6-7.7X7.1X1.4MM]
Designator prefix U

## INTERFACE-HDG104-DN-2(QFN44) (MPN: HDG104-DN-2; VALUE: HDG104-DN-2-QFN44)  [QFN44-0.6-7.7X7.1X1.4MM]
1  SDIO-DAT0
2  SDIO-DAT1
3  GND
4  ANT_WLAN
5  COEX4
6  ICE_TDI
7  ICE_TRST
8  ICE_TCK
9  NC
10  ICE_TMS
11  VPA
12  ICE_TDO
13  COEX3
14  COEX2
15  NC
16  NC
17  DVDD
18  NC
19  VCC_REG_VCO
20  VCC
21  COEX0
22  VCC_REG_PLL
23  !SHUTDOWN
24  40MHZ_IN
25  40MHZ_OUT
26  DCDC_ENABLE
27  VDD_CKL_12
28  VDD_CKL_26
29  VBT_32K
30  TEST_EN
31  DCO
32  COEX1
33  VBAT_P
34  !REST
35  EXT_PWR_EN
36  LFC(SLEEP-CLK)
37  VDD_IO
38  NC
39  SDIO-DAT3
40  SDIO-CMD
41  VDD_MAC_BB
42  VDD_SDIO
43  SDIO-DAT2
44  SDIO-CLK
45  GND
46  GND
47  GND
48  GND

## Footprint QFN44-0.6-7.7X7.1X1.4MM (pad centres in mm)
smd 0.3 x 1.1: 1 -2.4,-3.7; 2 -1.8,-3.7; 3 -1.2,-3.7; 4 -0.6,-3.7; 5 0,-3.7; 6 0.6,-3.7; 7 1.2,-3.7; 8 1.8,-3.7; 9 2.4,-3.7; 23 2.4,3.7; 24 1.8,3.7; 25 1.2,3.7; 26 0.6,3.7; 27 0,3.7; 28 -0.6,3.7; 29 -1.2,3.7; 30 -1.8,3.7; 31 -2.4,3.7
smd 1.1 x 0.3: 10 3.4,-3.6; 11 3.4,-3; 12 3.4,-2.4; 13 3.4,-1.8; 14 3.4,-1.2; 15 3.4,-0.6; 16 3.4,0; 17 3.4,0.6; 18 3.4,1.2; 19 3.4,1.8; 20 3.4,2.4; 21 3.4,3; 22 3.4,3.6; 32 -3.4,3.6; 33 -3.4,3; 34 -3.4,2.4; 35 -3.4,1.8; 36 -3.4,1.2; 37 -3.4,0.6; 38 -3.4,0; 39 -3.4,-0.6; 40 -3.4,-1.2; 41 -3.4,-1.8; 42 -3.4,-2.4; 43 -3.4,-3; 44 -3.4,-3.6
smd 1 x 1.4: 45 -0.75,-0.95; 46 0.75,-0.95; 47 0.75,0.95; 48 -0.75,0.95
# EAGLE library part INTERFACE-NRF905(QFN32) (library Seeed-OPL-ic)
317070016

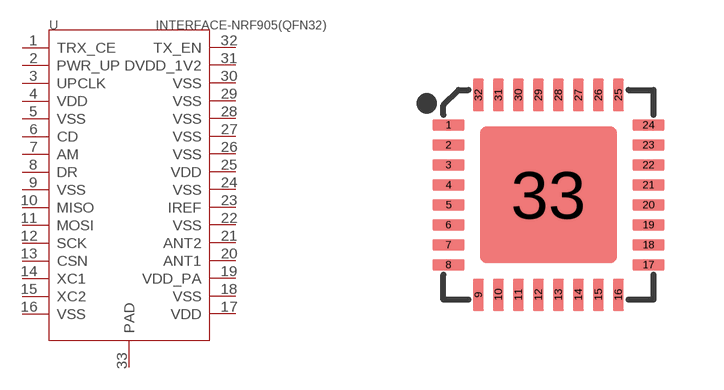
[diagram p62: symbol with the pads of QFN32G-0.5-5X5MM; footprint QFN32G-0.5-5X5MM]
Designator prefix U

## INTERFACE-NRF905(QFN32) (MPN: NRF905; VALUE: NRF905-QFN32)  [QFN32G-0.5-5X5MM]
1  TRX_CE
2  PWR_UP
3  UPCLK
4  VDD
5  VSS
6  CD
7  AM
8  DR
9  VSS
10  MISO
11  MOSI
12  SCK
13  CSN
14  XC1
15  XC2
16  VSS
17  VDD
18  VSS
19  VDD_PA
20  ANT1
21  ANT2
22  VSS
23  IREF
24  VSS
25  VDD
26  VSS
27  VSS
28  VSS
29  VSS
30  VSS
31  DVDD_1V2
32  TX_EN
33  PAD

## Footprint QFN32G-0.5-5X5MM (pad centres in mm)
smd 0.813 x 0.279: 1 -2.5,1.75; 2 -2.5,1.25; 3 -2.5,0.75; 4 -2.5,0.25; 5 -2.5,-0.25; 6 -2.5,-0.75; 7 -2.5,-1.25; 8 -2.5,-1.75; 17 2.5,-1.75; 18 2.5,-1.25; 19 2.5,-0.75; 20 2.5,-0.25; 21 2.5,0.25; 22 2.5,0.75; 23 2.5,1.25; 24 2.5,1.75
smd 0.279 x 0.813: 9 -1.75,-2.5; 10 -1.25,-2.5; 11 -0.75,-2.5; 12 -0.25,-2.5; 13 0.25,-2.5; 14 0.75,-2.5; 15 1.25,-2.5; 16 1.75,-2.5; 25 1.75,2.5; 26 1.25,2.5; 27 0.75,2.5; 28 0.25,2.5; 29 -0.25,2.5; 30 -0.75,2.5; 31 -1.25,2.5; 32 -1.75,2.5
smd 3.429 x 3.429: 33 0,0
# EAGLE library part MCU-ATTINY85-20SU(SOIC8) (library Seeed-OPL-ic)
310010108

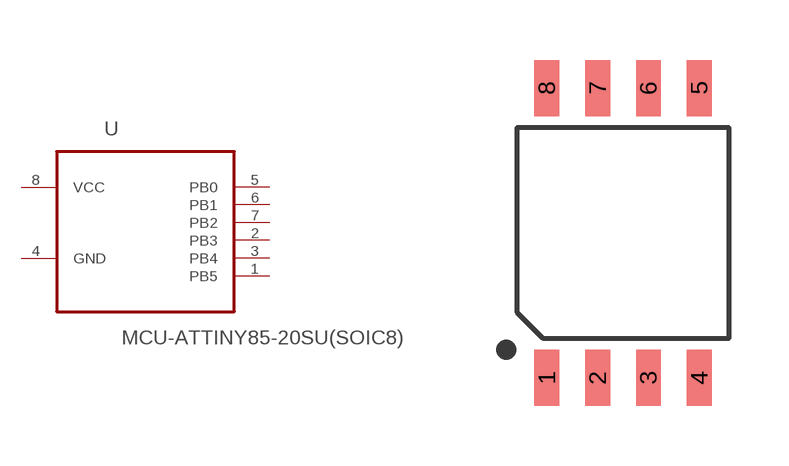
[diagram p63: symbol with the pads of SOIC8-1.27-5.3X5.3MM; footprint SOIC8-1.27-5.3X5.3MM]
Designator prefix U

## MCU-ATTINY85-20SU(SOIC8) (MPN: ATTINY85-20SU; VALUE: ATTINY85-20SU-SOIC8)  [SOIC8-1.27-5.3X5.3MM]
1  PB5
2  PB3
3  PB4
4  GND  pas
5  PB0
6  PB1
7  PB2
8  VCC  pwr

## Footprint SOIC8-1.27-5.3X5.3MM (pad centres in mm)
smd 0.62 x 1.4: 1 -1.905,-3.623; 2 -0.635,-3.623; 3 0.635,-3.623; 4 1.905,-3.623; 5 1.905,3.623; 6 0.635,3.623; 7 -0.635,3.623; 8 -1.905,3.623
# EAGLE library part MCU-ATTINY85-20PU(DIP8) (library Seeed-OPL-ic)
310010112

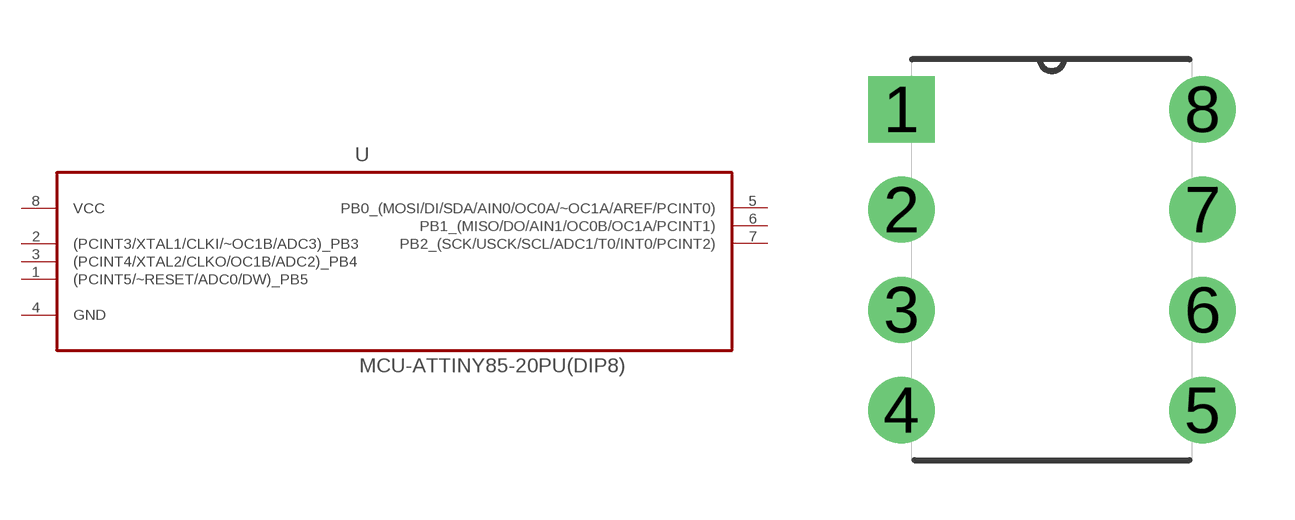
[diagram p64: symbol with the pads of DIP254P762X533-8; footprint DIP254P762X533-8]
Designator prefix U

## MCU-ATTINY85-20PU(DIP8)1 (MPN: ATTINY85-20PU; VALUE: ATTINY85-20PU-DIP8)  [DIP254P762X533-8]
1  (PCINT5/~RESET/ADC0/DW)_PB5
2  (PCINT3/XTAL1/CLKI/~OC1B/ADC3)_PB3
3  (PCINT4/XTAL2/CLKO/OC1B/ADC2)_PB4
4  GND  pas
5  PB0_(MOSI/DI/SDA/AIN0/OC0A/~OC1A/AREF/PCINT0)
6  PB1_(MISO/DO/AIN1/OC0B/OC1A/PCINT1)
7  PB2_(SCK/USCK/SCL/ADC1/T0/INT0/PCINT2)
8  VCC  pwr

## Footprint DIP254P762X533-8 (pad centres in mm)
drill 1.118 square: 1 -7.62,7.62
drill 1.118: 2 -7.62,5.08; 3 -7.62,2.54; 4 -7.62,0; 5 0,0; 6 0,2.54; 7 0,5.08; 8 0,7.62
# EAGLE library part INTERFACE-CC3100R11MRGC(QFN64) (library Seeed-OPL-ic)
317070015

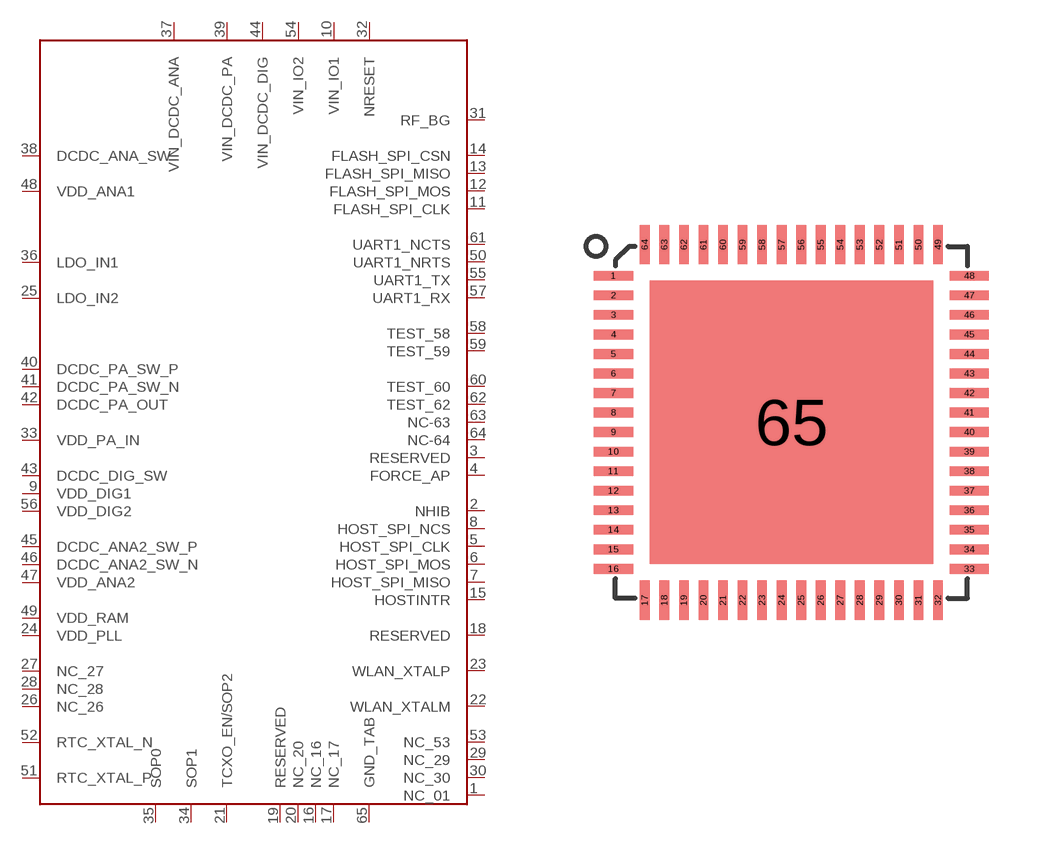
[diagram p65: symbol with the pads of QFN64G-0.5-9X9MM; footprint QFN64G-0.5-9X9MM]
Designator prefix U

## INTERFACE-CC3100R11MRGC(QFN64) (MPN: CC3100R11MRGC; VALUE: CC3100R11MRGC-QFN64)  [QFN64G-0.5-9X9MM]
1  NC_01
2  NHIB
3  RESERVED
4  FORCE_AP
5  HOST_SPI_CLK
6  HOST_SPI_MOS
7  HOST_SPI_MISO
8  HOST_SPI_NCS
9  VDD_DIG1
10  VIN_IO1
11  FLASH_SPI_CLK
12  FLASH_SPI_MOS
13  FLASH_SPI_MISO
14  FLASH_SPI_CSN
15  HOSTINTR
16  NC_16
17  NC_17
18  RESERVED
19  RESERVED
20  NC_20
21  TCXO_EN/SOP2
22  WLAN_XTALM
23  WLAN_XTALP
24  VDD_PLL
25  LDO_IN2
26  NC_26
27  NC_27
28  NC_28
29  NC_29
30  NC_30
31  RF_BG
32  NRESET
33  VDD_PA_IN
34  SOP1
35  SOP0
36  LDO_IN1
37  VIN_DCDC_ANA
38  DCDC_ANA_SW
39  VIN_DCDC_PA
40  DCDC_PA_SW_P
41  DCDC_PA_SW_N
42  DCDC_PA_OUT
43  DCDC_DIG_SW
44  VIN_DCDC_DIG
45  DCDC_ANA2_SW_P
46  DCDC_ANA2_SW_N
47  VDD_ANA2
48  VDD_ANA1
49  VDD_RAM
50  UART1_NRTS
51  RTC_XTAL_P
52  RTC_XTAL_N
53  NC_53
54  VIN_IO2
55  UART1_TX
56  VDD_DIG2
57  UART1_RX
58  TEST_58
59  TEST_59
60  TEST_60
61  UART1_NCTS
62  TEST_62
63  NC-63
64  NC-64
65  GND_TAB

## Footprint QFN64G-0.5-9X9MM (pad centres in mm)
smd 1 x 0.25: 1 -4.55,3.75; 2 -4.55,3.25; 3 -4.55,2.75; 4 -4.55,2.25; 5 -4.55,1.75; 6 -4.55,1.25; 7 -4.55,0.75; 8 -4.55,0.25; 9 -4.55,-0.25; 10 -4.55,-0.75; 11 -4.55,-1.25; 12 -4.55,-1.75; 13 -4.55,-2.25; 14 -4.55,-2.75; 15 -4.55,-3.25; 16 -4.55,-3.75; 33 4.55,-3.75; 34 4.55,-3.25; 35 4.55,-2.75; 36 4.55,-2.25; 37 4.55,-1.75; 38 4.55,-1.25; 39 4.55,-0.75; 40 4.55,-0.25; 41 4.55,0.25; 42 4.55,0.75; 43 4.55,1.25; 44 4.55,1.75; 45 4.55,2.25; 46 4.55,2.75; 47 4.55,3.25; 48 4.55,3.75
smd 0.25 x 1: 17 -3.75,-4.55; 18 -3.25,-4.55; 19 -2.75,-4.55; 20 -2.25,-4.55; 21 -1.75,-4.55; 22 -1.25,-4.55; 23 -0.75,-4.55; 24 -0.25,-4.55; 25 0.25,-4.55; 26 0.75,-4.55; 27 1.25,-4.55; 28 1.75,-4.55; 29 2.25,-4.55; 30 2.75,-4.55; 31 3.25,-4.55; 32 3.75,-4.55; 49 3.75,4.55; 50 3.25,4.55; 51 2.75,4.55; 52 2.25,4.55; 53 1.75,4.55; 54 1.25,4.55; 55 0.75,4.55; 56 0.25,4.55; 57 -0.25,4.55; 58 -0.75,4.55; 59 -1.25,4.55; 60 -1.75,4.55; 61 -2.25,4.55; 62 -2.75,4.55; 63 -3.25,4.55; 64 -3.75,4.55
smd 7.25 x 7.25: 65 0,0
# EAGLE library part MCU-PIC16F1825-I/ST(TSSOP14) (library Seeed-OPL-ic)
310010120

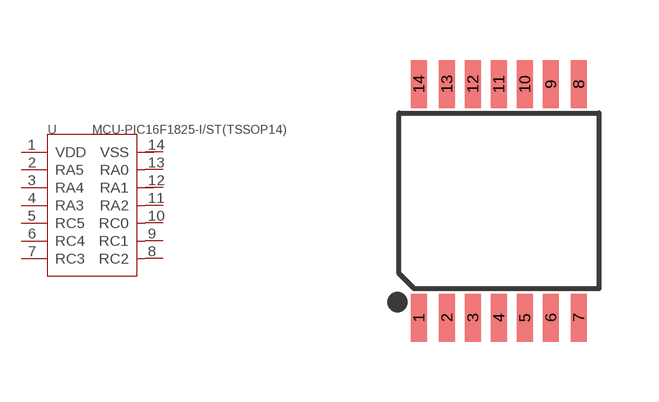
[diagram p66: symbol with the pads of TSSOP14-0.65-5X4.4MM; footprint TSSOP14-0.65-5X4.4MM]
Designator prefix U

## MCU-PIC16F1825-I/ST(TSSOP14) (MPN: PIC16F1825-I/ST; VALUE: PIC16F1825-I/ST-TSSOP14)  [TSSOP14-0.65-5X4.4MM]
1  VDD
2  RA5
3  RA4
4  RA3
5  RC5
6  RC4
7  RC3
8  RC2
9  RC1
10  RC0
11  RA2
12  RA1
13  RA0
14  VSS

## Footprint TSSOP14-0.65-5X4.4MM (pad centres in mm)
smd 0.4 x 1.2: 1 -2,-2.925; 2 -1.3,-2.925; 3 -0.65,-2.925; 4 0,-2.925; 5 0.65,-2.925; 6 1.3,-2.925; 7 2,-2.925; 8 2,2.925; 9 1.3,2.925; 10 0.65,2.925; 11 0,2.925; 12 -0.65,2.925; 13 -1.3,2.925; 14 -2,2.925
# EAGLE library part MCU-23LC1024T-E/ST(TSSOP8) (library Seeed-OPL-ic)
310090068

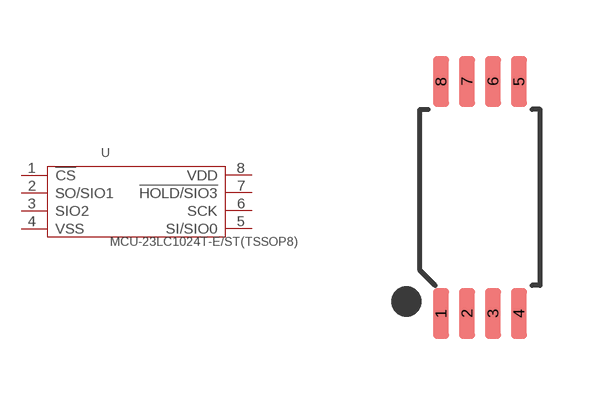
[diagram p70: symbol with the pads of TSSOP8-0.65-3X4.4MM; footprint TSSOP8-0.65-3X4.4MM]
Designator prefix U

## MCU-23LC1024T-E/ST(TSSOP8) (MPN: 23LC1024T-E/ST; VALUE: 23LC1024T-E/ST-TSSOP8)  [TSSOP8-0.65-3X4.4MM]
1  !CS
2  SO/SIO1
3  SIO2
4  VSS
5  SI/SIO0
6  SCK
7  !HOLD/SIO3
8  VDD

## Footprint TSSOP8-0.65-3X4.4MM (pad centres in mm)
smd 0.4 x 1.27: 1 -0.975,-2.9; 2 -0.325,-2.9; 3 0.325,-2.9; 4 0.975,-2.9; 5 0.975,2.9; 6 0.325,2.9; 7 -0.325,2.9; 8 -0.975,2.9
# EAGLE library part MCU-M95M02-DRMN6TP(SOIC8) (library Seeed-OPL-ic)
310090069

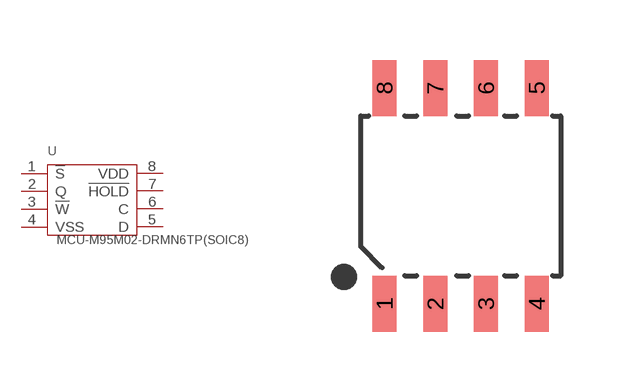
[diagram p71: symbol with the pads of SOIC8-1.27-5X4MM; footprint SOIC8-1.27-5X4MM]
Designator prefix U

## MCU-M95M02-DRMN6TP(SOIC8) (MPN: M95M02-DRMN6TP; VALUE: M95M02-DRMN6TP-SOIC8)  [SOIC8-1.27-5X4MM]
1  !S
2  Q
3  !W
4  VSS
5  D
6  C
7  !HOLD
8  VDD

## Footprint SOIC8-1.27-5X4MM (pad centres in mm)
smd 0.6 x 1.4: 1 -1.905,-2.7; 2 -0.635,-2.7; 3 0.635,-2.7; 4 1.905,-2.7; 5 1.905,2.7; 6 0.635,2.7; 7 -0.635,2.7; 8 -1.905,2.7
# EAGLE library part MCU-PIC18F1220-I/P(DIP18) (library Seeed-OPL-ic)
310010118

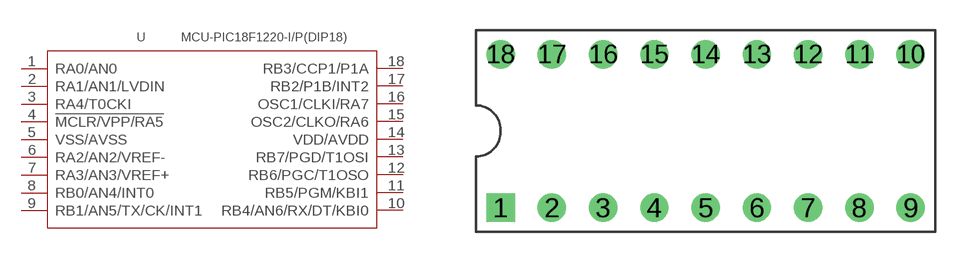
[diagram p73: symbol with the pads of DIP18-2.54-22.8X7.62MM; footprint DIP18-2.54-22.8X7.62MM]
Designator prefix U

## MCU-PIC18F1220-I/P(DIP18) (MPN: PIC18F1220-I/P; VALUE: PIC18F1220-I/P-DIP18)  [DIP18-2.54-22.8X7.62MM]
1  RA0/AN0
2  RA1/AN1/LVDIN
3  RA4/T0CKI
4  !MCLR/VPP/RA5
5  VSS/AVSS
6  RA2/AN2/VREF-
7  RA3/AN3/VREF+
8  RB0/AN4/INT0
9  RB1/AN5/TX/CK/INT1
10  RB4/AN6/RX/DT/KBI0
11  RB5/PGM/KBI1
12  RB6/PGC/T1OSO
13  RB7/PGD/T1OSI
14  VDD/AVDD
15  OSC2/CLKO/RA6
16  OSC1/CLKI/RA7
17  RB2/P1B/INT2
18  RB3/CCP1/P1A

## Footprint DIP18-2.54-22.8X7.62MM (pad centres in mm)
drill 0.9 pad 1.4 square: 1 -10.16,-3.81
drill 0.9 pad 1.4: 2 -7.62,-3.81; 3 -5.08,-3.81; 4 -2.54,-3.81; 5 0,-3.81; 6 2.54,-3.81; 7 5.08,-3.81; 8 7.62,-3.81; 9 10.16,-3.81; 10 10.16,3.81; 11 7.62,3.81; 12 5.08,3.81; 13 2.54,3.81; 14 0,3.81; 15 -2.54,3.81; 16 -5.08,3.81; 17 -7.62,3.81; 18 -10.16,3.81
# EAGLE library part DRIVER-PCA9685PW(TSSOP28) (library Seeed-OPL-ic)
310030252

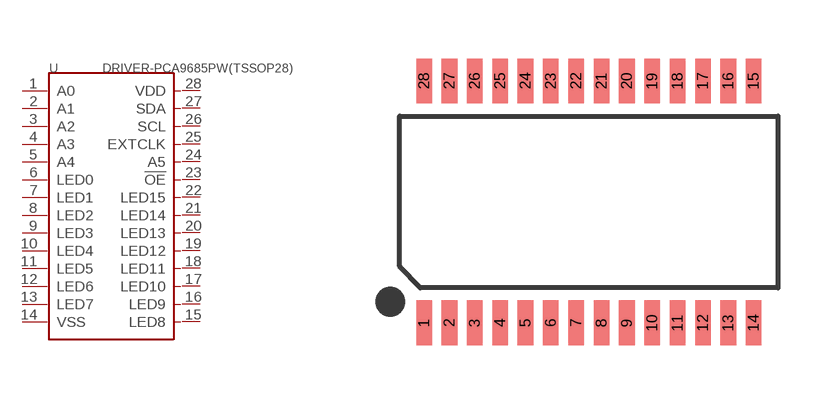
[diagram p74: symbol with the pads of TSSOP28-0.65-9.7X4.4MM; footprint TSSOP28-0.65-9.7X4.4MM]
Designator prefix U

## DRIVER-PCA9685PW(TSSOP28) (MPN: PCA9685PW; VALUE: PCA9685PW-TSSOP28)  [TSSOP28-0.65-9.7X4.4MM]
1  A0
2  A1
3  A2
4  A3
5  A4
6  LED0
7  LED1
8  LED2
9  LED3
10  LED4
11  LED5
12  LED6
13  LED7
14  VSS
15  LED8
16  LED9
17  LED10
18  LED11
19  LED12
20  LED13
21  LED14
22  LED15
23  !OE
24  A5
25  EXTCLK
26  SCL
27  SDA
28  VDD

## Footprint TSSOP28-0.65-9.7X4.4MM (pad centres in mm)
smd 0.4 x 1.15: 1 -4.225,-3.1; 2 -3.575,-3.1; 3 -2.925,-3.1; 4 -2.275,-3.1; 5 -1.625,-3.1; 6 -0.975,-3.1; 7 -0.325,-3.1; 8 0.325,-3.1; 9 0.975,-3.1; 10 1.625,-3.1; 11 2.275,-3.1; 12 2.925,-3.1; 13 3.575,-3.1; 14 4.225,-3.1; 15 4.225,3.1; 16 3.575,3.1; 17 2.925,3.1; 18 2.275,3.1; 19 1.625,3.1; 20 0.975,3.1; 21 0.325,3.1; 22 -0.325,3.1; 23 -0.975,3.1; 24 -1.625,3.1; 25 -2.275,3.1; 26 -2.925,3.1; 27 -3.575,3.1; 28 -4.225,3.1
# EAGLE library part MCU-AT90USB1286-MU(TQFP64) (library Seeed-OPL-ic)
310010119

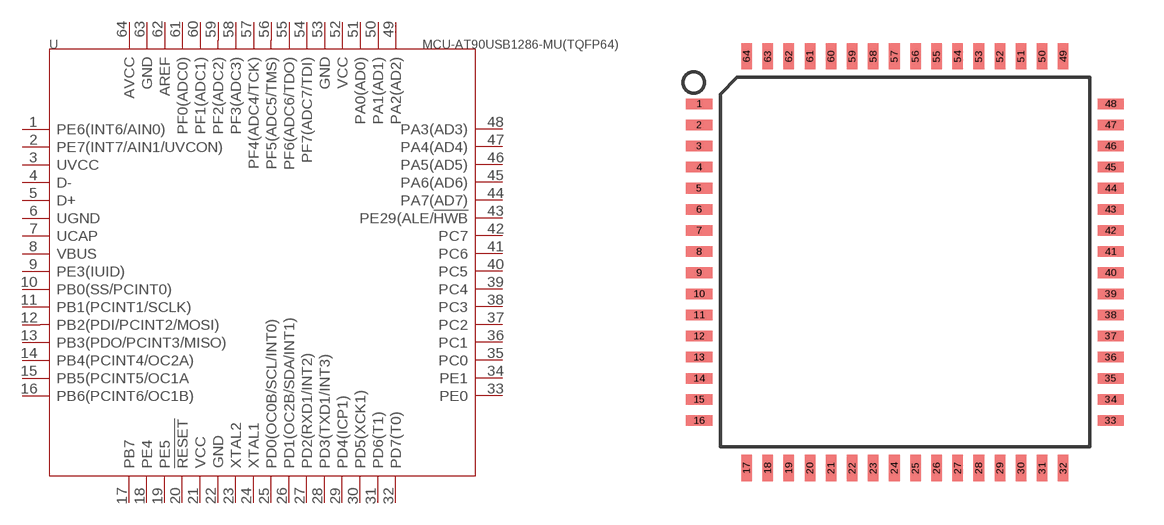
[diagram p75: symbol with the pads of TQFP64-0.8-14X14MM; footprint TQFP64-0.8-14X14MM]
Designator prefix U

## MCU-AT90USB1286-MU(TQFP64) (MPN: AT90USB1286-MU; VALUE: AT90USB1286-MU-TQFP64)  [TQFP64-0.8-14X14MM]
1  PE6(INT6/AIN0)
2  PE7(INT7/AIN1/UVCON)
3  UVCC
4  D-
5  D+
6  UGND
7  UCAP
8  VBUS
9  PE3(IUID)
10  PB0(SS/PCINT0)
11  PB1(PCINT1/SCLK)
12  PB2(PDI/PCINT2/MOSI)
13  PB3(PDO/PCINT3/MISO)
14  PB4(PCINT4/OC2A)
15  PB5(PCINT5/OC1A
16  PB6(PCINT6/OC1B)
17  PB7
18  PE4
19  PE5
20  !RESET
21  VCC
22  GND
23  XTAL2
24  XTAL1
25  PD0(OC0B/SCL/INT0)
26  PD1(OC2B/SDA/INT1)
27  PD2(RXD1/INT2)
28  PD3(TXD1/INT3)
29  PD4(ICP1)
30  PD5(XCK1)
31  PD6(T1)
32  PD7(T0)
33  PE0
34  PE1
35  PC0
36  PC1
37  PC2
38  PC3
39  PC4
40  PC5
41  PC6
42  PC7
43  PE29(ALE/!HWB
44  PA7(AD7)
45  PA6(AD6)
46  PA5(AD5)
47  PA4(AD4)
48  PA3(AD3)
49  PA2(AD2)
50  PA1(AD1)
51  PA0(AD0)
52  VCC
53  GND
54  PF7(ADC7/TDI)
55  PF6(ADC6/TDO)
56  PF5(ADC5/TMS)
57  PF4(ADC4/TCK)
58  PF3(ADC3)
59  PF2(ADC2)
60  PF1(ADC1)
61  PF0(ADC0)
62  AREF
63  GND
64  AVCC

## Footprint TQFP64-0.8-14X14MM (pad centres in mm)
smd 1 x 0.4: 1 -7.8,6; 2 -7.8,5.2; 3 -7.8,4.4; 4 -7.8,3.6; 5 -7.8,2.8; 6 -7.8,2; 7 -7.8,1.2; 8 -7.8,0.4; 9 -7.8,-0.4; 10 -7.8,-1.2; 11 -7.8,-2; 12 -7.8,-2.8; 13 -7.8,-3.6; 14 -7.8,-4.4; 15 -7.8,-5.2; 16 -7.8,-6; 33 7.8,-6; 34 7.8,-5.2; 35 7.8,-4.4; 36 7.8,-3.6; 37 7.8,-2.8; 38 7.8,-2; 39 7.8,-1.2; 40 7.8,-0.4; 41 7.8,0.4; 42 7.8,1.2; 43 7.8,2; 44 7.8,2.8; 45 7.8,3.6; 46 7.8,4.4; 47 7.8,5.2; 48 7.8,6
smd 0.4 x 1: 17 -6,-7.8; 18 -5.2,-7.8; 19 -4.4,-7.8; 20 -3.6,-7.8; 21 -2.8,-7.8; 22 -2,-7.8; 23 -1.2,-7.8; 24 -0.4,-7.8; 25 0.4,-7.8; 26 1.2,-7.8; 27 2,-7.8; 28 2.8,-7.8; 29 3.6,-7.8; 30 4.4,-7.8; 31 5.2,-7.8; 32 6,-7.8; 49 6,7.8; 50 5.2,7.8; 51 4.4,7.8; 52 3.6,7.8; 53 2.8,7.8; 54 2,7.8; 55 1.2,7.8; 56 0.4,7.8; 57 -0.4,7.8; 58 -1.2,7.8; 59 -2,7.8; 60 -2.8,7.8; 61 -3.6,7.8; 62 -4.4,7.8; 63 -5.2,7.8; 64 -6,7.8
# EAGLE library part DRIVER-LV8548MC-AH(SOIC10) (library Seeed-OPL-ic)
310030259

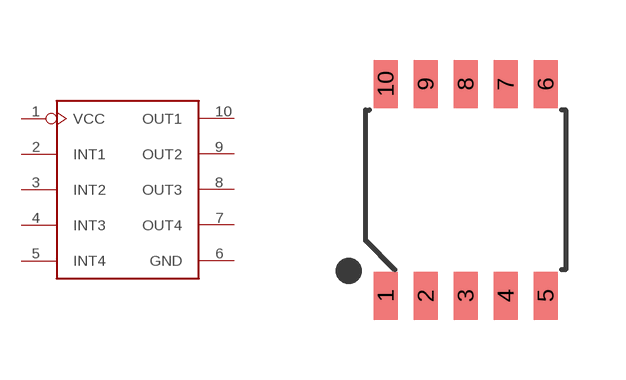
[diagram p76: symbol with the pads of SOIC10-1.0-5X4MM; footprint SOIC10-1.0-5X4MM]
Designator prefix U

## DRIVER-LV8548MC-AH(SOIC10) (MPN: LV8548MC-AH; VALUE: LV8548MC-AH)  [SOIC10-1.0-5X4MM]
1  VCC
2  INT1
3  INT2
4  INT3
5  INT4
6  GND
7  OUT4
8  OUT3
9  OUT2
10  OUT1

## Footprint SOIC10-1.0-5X4MM (pad centres in mm)
smd 0.6 x 1.2: 1 -2,-2.65; 2 -1,-2.65; 3 0,-2.65; 4 1,-2.65; 5 2,-2.65; 6 2,2.65; 7 1,2.65; 8 0,2.65; 9 -1,2.65; 10 -2,2.65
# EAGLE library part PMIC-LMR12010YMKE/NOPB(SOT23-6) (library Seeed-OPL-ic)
310030255

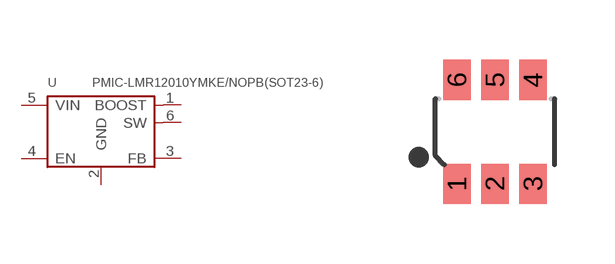
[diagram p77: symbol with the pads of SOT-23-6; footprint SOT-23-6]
Designator prefix U

## PMIC-LMR12010YMKE/NOPB(SOT23-6) (MPN: LMR12010YMKE/NOPB; VALUE: LMR12010YMKE/NOPB-SOT23-6)  [SOT-23-6]
1  BOOST  out
2  GND  pwr
3  FB  in
4  EN  in
5  VIN  in
6  SW  in

## Footprint SOT-23-6 (pad centres in mm)
smd 0.69 x 1: 1 -0.95,-1.3; 2 0,-1.3; 3 0.95,-1.3; 4 0.95,1.3; 5 0,1.3; 6 -0.95,1.3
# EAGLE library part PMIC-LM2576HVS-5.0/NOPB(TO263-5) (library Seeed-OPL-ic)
310030257

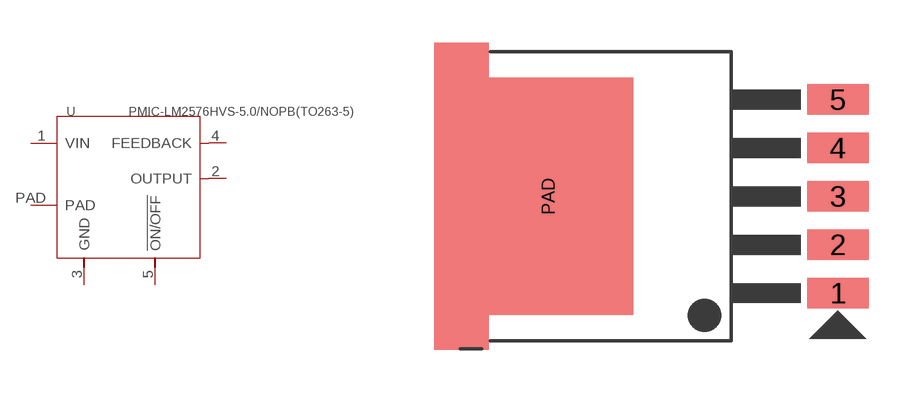
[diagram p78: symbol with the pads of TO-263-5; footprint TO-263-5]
Designator prefix U

## PMIC-LM2576HVS-5.0/NOPB(TO263-5) (MPN: LM2576HVS-5.0/NOPB; VALUE: LM2576HVS-5.0/NOPB-TO263-5)  [TO-263-5]
1  VIN
2  OUTPUT
3  GND
4  FEEDBACK
5  !ON/OFF
PAD  PAD

## Footprint TO-263-5 (pad centres in mm)
smd 2.16 x 1.07: 1 0,-3.4; 2 0,-1.7; 3 0,0; 4 0,1.7; 5 0,3.4
smd 0.635 x 1.27: PAD -10.16,0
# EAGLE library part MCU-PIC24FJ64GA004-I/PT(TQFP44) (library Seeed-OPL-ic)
310010050

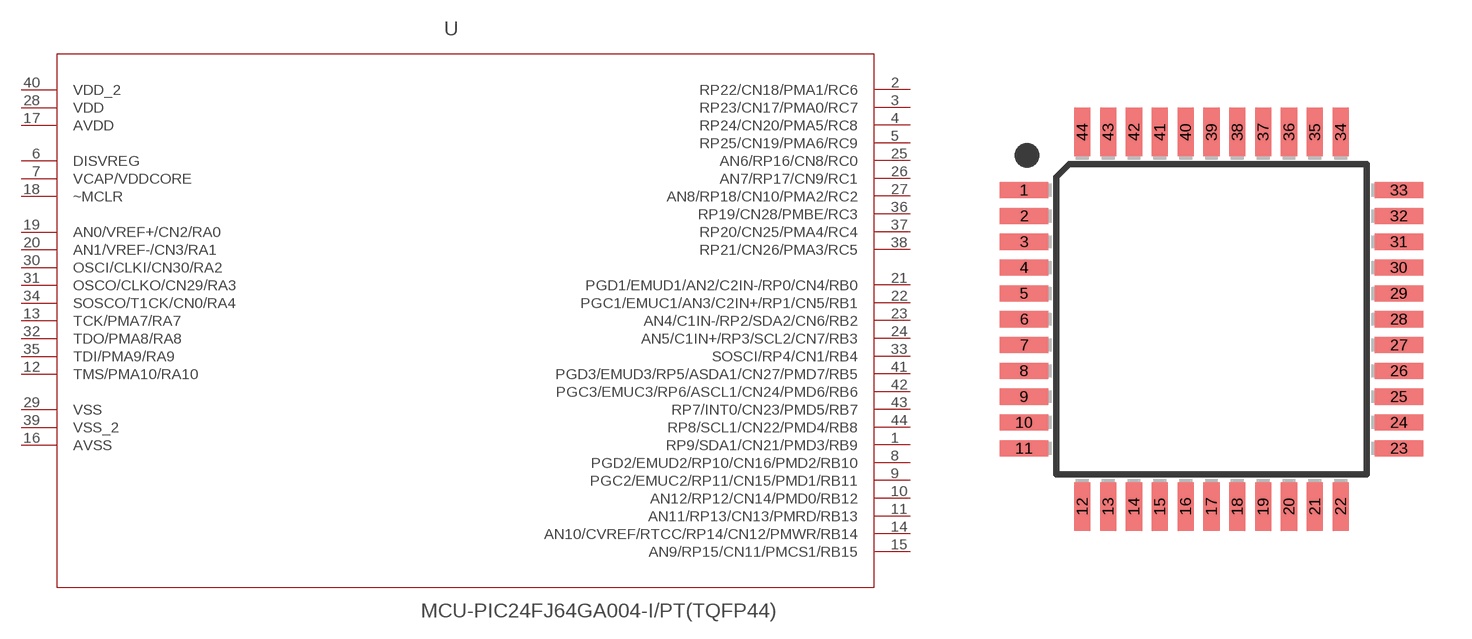
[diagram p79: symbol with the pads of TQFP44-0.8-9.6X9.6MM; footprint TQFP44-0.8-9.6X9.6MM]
Designator prefix U

## MCU-PIC24FJ64GA004-I/PT(TQFP44) (MPN: PIC24FJ64GA004-I/PT; VALUE: PIC24FJ64GA004-I/P-TQFP44)  [TQFP44-0.8-9.6X9.6MM]
1  RP9/SDA1/CN21/PMD3/RB9
2  RP22/CN18/PMA1/RC6
3  RP23/CN17/PMA0/RC7
4  RP24/CN20/PMA5/RC8
5  RP25/CN19/PMA6/RC9
6  DISVREG  pas
7  VCAP/VDDCORE  pwr
8  PGD2/EMUD2/RP10/CN16/PMD2/RB10
9  PGC2/EMUC2/RP11/CN15/PMD1/RB11
10  AN12/RP12/CN14/PMD0/RB12
11  AN11/RP13/CN13/PMRD/RB13
12  TMS/PMA10/RA10
13  TCK/PMA7/RA7
14  AN10/CVREF/RTCC/RP14/CN12/PMWR/RB14
15  AN9/RP15/CN11/PMCS1/RB15
16  AVSS  pwr
17  AVDD  pwr
18  ~MCLR
19  AN0/VREF+/CN2/RA0
20  AN1/VREF-/CN3/RA1
21  PGD1/EMUD1/AN2/C2IN-/RP0/CN4/RB0
22  PGC1/EMUC1/AN3/C2IN+/RP1/CN5/RB1
23  AN4/C1IN-/RP2/SDA2/CN6/RB2
24  AN5/C1IN+/RP3/SCL2/CN7/RB3
25  AN6/RP16/CN8/RC0
26  AN7/RP17/CN9/RC1
27  AN8/RP18/CN10/PMA2/RC2
28  VDD  pwr
29  VSS  pwr
30  OSCI/CLKI/CN30/RA2
31  OSCO/CLKO/CN29/RA3
32  TDO/PMA8/RA8
33  SOSCI/RP4/CN1/RB4
34  SOSCO/T1CK/CN0/RA4
35  TDI/PMA9/RA9
36  RP19/CN28/PMBE/RC3
37  RP20/CN25/PMA4/RC4
38  RP21/CN26/PMA3/RC5
39  VSS_2  pwr
40  VDD_2  pwr
41  PGD3/EMUD3/RP5/ASDA1/CN27/PMD7/RB5
42  PGC3/EMUC3/RP6/ASCL1/CN24/PMD6/RB6
43  RP7/INT0/CN23/PMD5/RB7
44  RP8/SCL1/CN22/PMD4/RB8

## Footprint TQFP44-0.8-9.6X9.6MM (pad centres in mm)
Thin Plasic Quad Flat Package
smd 1.5 x 0.5: 1 -5.8,4; 2 -5.8,3.2; 3 -5.8,2.4; 4 -5.8,1.6; 5 -5.8,0.8; 6 -5.8,0; 7 -5.8,-0.8; 8 -5.8,-1.6; 9 -5.8,-2.4; 10 -5.8,-3.2; 11 -5.8,-4; 23 5.8,-4; 24 5.8,-3.2; 25 5.8,-2.4; 26 5.8,-1.6; 27 5.8,-0.8; 28 5.8,0; 29 5.8,0.8; 30 5.8,1.6; 31 5.8,2.4; 32 5.8,3.2; 33 5.8,4
smd 0.5 x 1.5: 12 -4,-5.8; 13 -3.2,-5.8; 14 -2.4,-5.8; 15 -1.6,-5.8; 16 -0.8,-5.8; 17 0,-5.8; 18 0.8,-5.8; 19 1.6,-5.8; 20 2.4,-5.8; 21 3.2,-5.8; 22 4,-5.8; 34 4,5.8; 35 3.2,5.8; 36 2.4,5.8; 37 1.6,5.8; 38 0.8,5.8; 39 0,5.8; 40 -0.8,5.8; 41 -1.6,5.8; 42 -2.4,5.8; 43 -3.2,5.8; 44 -4,5.8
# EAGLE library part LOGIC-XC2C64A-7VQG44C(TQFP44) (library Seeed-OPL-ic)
310050000

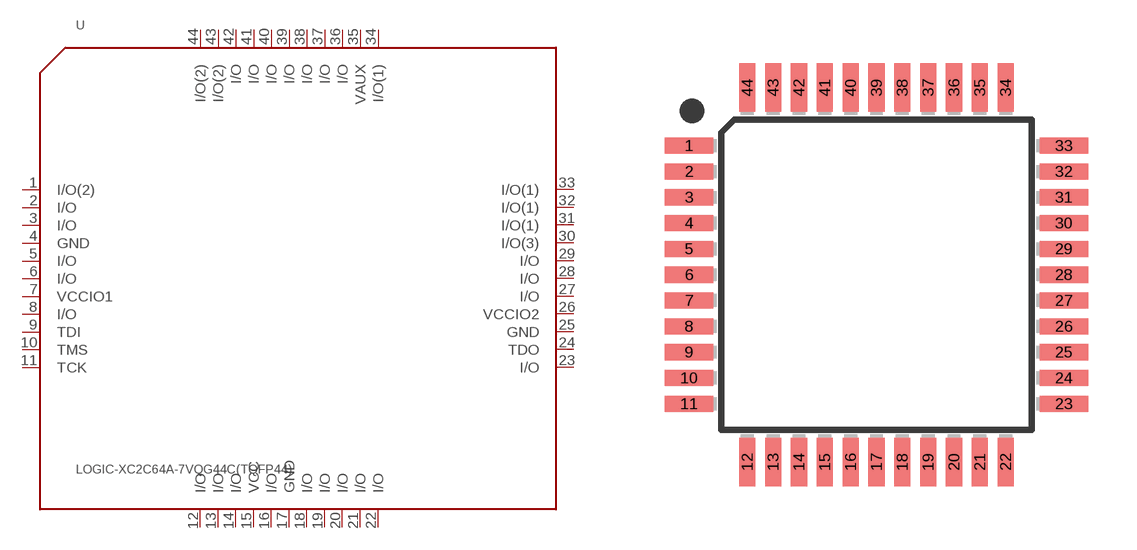
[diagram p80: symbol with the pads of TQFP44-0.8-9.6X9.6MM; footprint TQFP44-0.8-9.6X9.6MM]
Designator prefix U

## LOGIC-XC2C64A-7VQG44C(TQFP44) (MPN: XC2C64A-7VQG44C; VALUE: XC2C64A-7VQG44C-TQFP44)  [TQFP44-0.8-9.6X9.6MM]
1  I/O(2)
2  I/O
3  I/O
4  GND
5  I/O
6  I/O
7  VCCIO1
8  I/O
9  TDI
10  TMS
11  TCK
12  I/O
13  I/O
14  I/O
15  VCC
16  I/O
17  GND
18  I/O
19  I/O
20  I/O
21  I/O
22  I/O
23  I/O
24  TDO
25  GND
26  VCCIO2
27  I/O
28  I/O
29  I/O
30  I/O(3)
31  I/O(1)
32  I/O(1)
33  I/O(1)
34  I/O(1)
35  VAUX
36  I/O
37  I/O
38  I/O
39  I/O
40  I/O
41  I/O
42  I/O
43  I/O(2)
44  I/O(2)

## Footprint TQFP44-0.8-9.6X9.6MM (pad centres in mm)
Thin Plasic Quad Flat Package
smd 1.5 x 0.5: 1 -5.8,4; 2 -5.8,3.2; 3 -5.8,2.4; 4 -5.8,1.6; 5 -5.8,0.8; 6 -5.8,0; 7 -5.8,-0.8; 8 -5.8,-1.6; 9 -5.8,-2.4; 10 -5.8,-3.2; 11 -5.8,-4; 23 5.8,-4; 24 5.8,-3.2; 25 5.8,-2.4; 26 5.8,-1.6; 27 5.8,-0.8; 28 5.8,0; 29 5.8,0.8; 30 5.8,1.6; 31 5.8,2.4; 32 5.8,3.2; 33 5.8,4
smd 0.5 x 1.5: 12 -4,-5.8; 13 -3.2,-5.8; 14 -2.4,-5.8; 15 -1.6,-5.8; 16 -0.8,-5.8; 17 0,-5.8; 18 0.8,-5.8; 19 1.6,-5.8; 20 2.4,-5.8; 21 3.2,-5.8; 22 4,-5.8; 34 4,5.8; 35 3.2,5.8; 36 2.4,5.8; 37 1.6,5.8; 38 0.8,5.8; 39 0,5.8; 40 -0.8,5.8; 41 -1.6,5.8; 42 -2.4,5.8; 43 -3.2,5.8; 44 -4,5.8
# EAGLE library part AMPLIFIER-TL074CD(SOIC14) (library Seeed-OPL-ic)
310020047

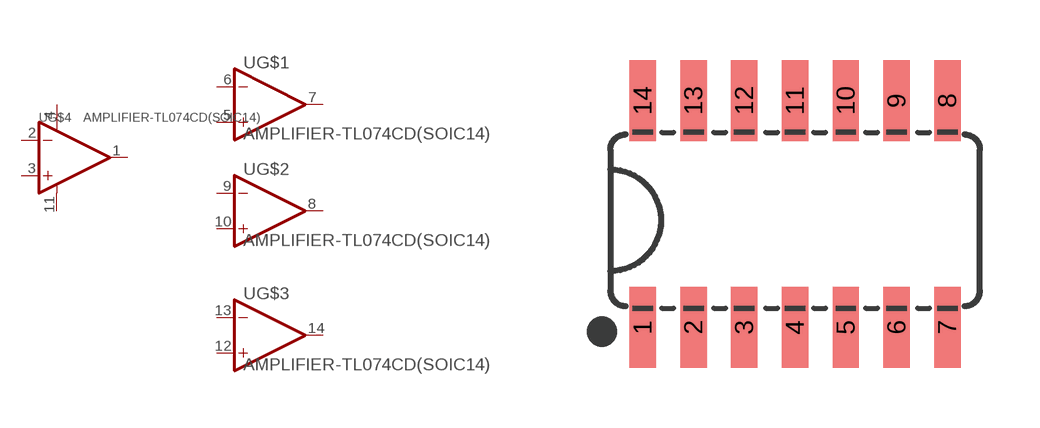
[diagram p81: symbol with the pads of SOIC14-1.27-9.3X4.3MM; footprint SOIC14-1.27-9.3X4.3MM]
Designator prefix U; gates G$1=OP-AMP G$2=OP-AMP G$3=OP-AMP G$4=AMPLIFIER-LM321MF

## AMPLIFIER-TL074CD(SOIC14) (MPN: TL074CD; VALUE: TL074CD-SOIC14)  [SOIC14-1.27-9.3X4.3MM]
1  G$4:OUT  out
2  G$4:IN-  in
3  G$4:IN+  in
4  G$4:V+  pwr
5  G$1:IN+  in
6  G$1:IN-  in
7  G$1:OUT  out
8  G$2:OUT  out
9  G$2:IN-  in
10  G$2:IN+  in
11  G$4:V-  pwr
12  G$3:IN+  in
13  G$3:IN-  in
14  G$3:OUT  out

## Footprint SOIC14-1.27-9.3X4.3MM (pad centres in mm)
smd 0.66 x 2.032: 1 -3.175,-2.68; 2 -1.905,-2.68; 3 -0.635,-2.68; 4 0.635,-2.68; 5 1.905,-2.68; 6 3.175,-2.68; 7 4.445,-2.68; 8 4.445,2.997; 9 3.175,2.997; 10 1.905,2.997; 11 0.635,2.997; 12 -0.635,2.997; 13 -1.905,2.997; 14 -3.175,2.997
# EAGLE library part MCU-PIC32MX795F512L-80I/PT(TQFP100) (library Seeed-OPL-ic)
310010122

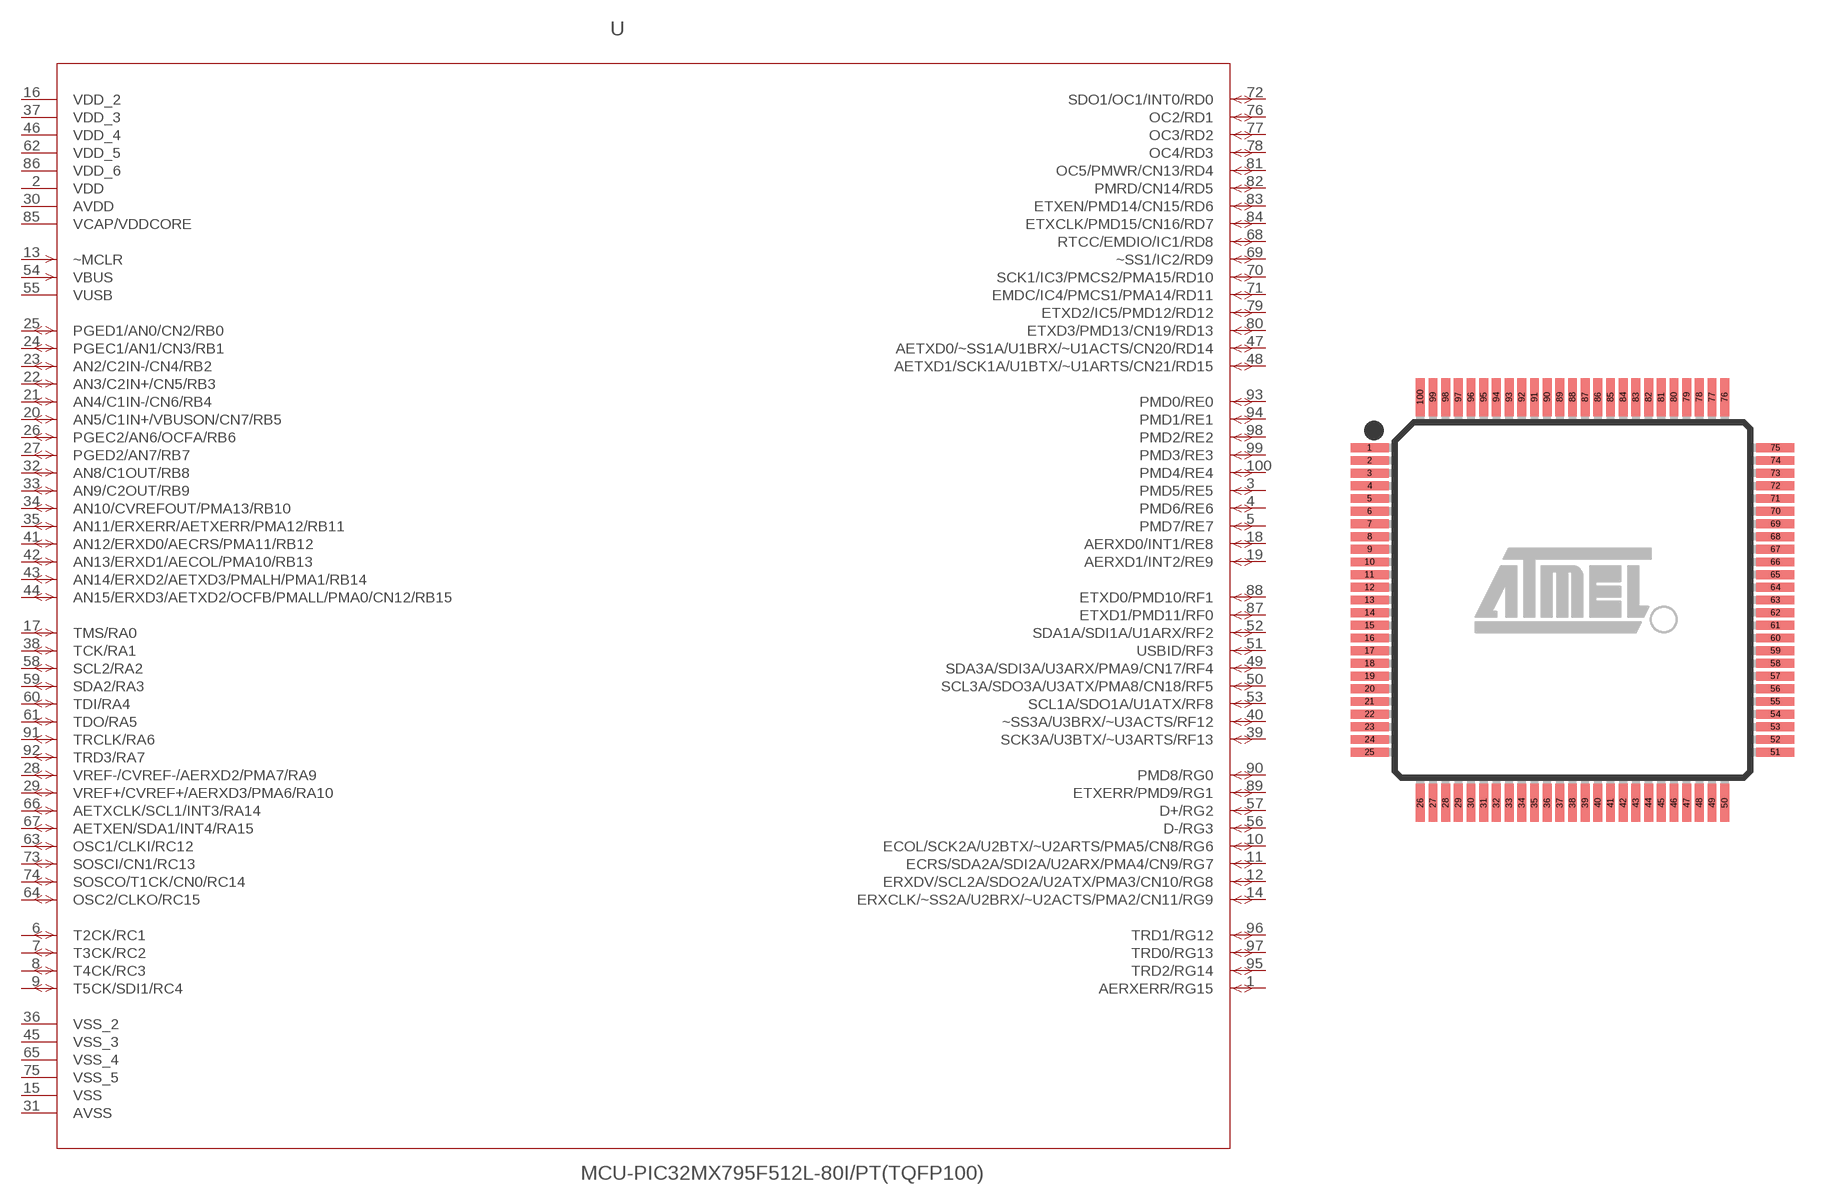
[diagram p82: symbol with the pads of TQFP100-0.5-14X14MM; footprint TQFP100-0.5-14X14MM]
Designator prefix U

## MCU-PIC32MX795F512L-80I/PT(TQFP100) (MPN: PIC32MX795F512L-80I/PT; VALUE: PIC32MX795F512L-80I/PT-TQFP100)  [TQFP100-0.5-14X14MM]
1  AERXERR/RG15
2  VDD  pwr
3  PMD5/RE5
4  PMD6/RE6
5  PMD7/RE7
6  T2CK/RC1
7  T3CK/RC2
8  T4CK/RC3
9  T5CK/SDI1/RC4
10  ECOL/SCK2A/U2BTX/~U2ARTS/PMA5/CN8/RG6
11  ECRS/SDA2A/SDI2A/U2ARX/PMA4/CN9/RG7
12  ERXDV/SCL2A/SDO2A/U2ATX/PMA3/CN10/RG8
13  ~MCLR  in
14  ERXCLK/~SS2A/U2BRX/~U2ACTS/PMA2/CN11/RG9
15  VSS  pwr
16  VDD_2  pwr
17  TMS/RA0
18  AERXD0/INT1/RE8
19  AERXD1/INT2/RE9
20  AN5/C1IN+/VBUSON/CN7/RB5
21  AN4/C1IN-/CN6/RB4
22  AN3/C2IN+/CN5/RB3
23  AN2/C2IN-/CN4/RB2
24  PGEC1/AN1/CN3/RB1
25  PGED1/AN0/CN2/RB0
26  PGEC2/AN6/OCFA/RB6
27  PGED2/AN7/RB7
28  VREF-/CVREF-/AERXD2/PMA7/RA9
29  VREF+/CVREF+/AERXD3/PMA6/RA10
30  AVDD  pwr
31  AVSS  pwr
32  AN8/C1OUT/RB8
33  AN9/C2OUT/RB9
34  AN10/CVREFOUT/PMA13/RB10
35  AN11/ERXERR/AETXERR/PMA12/RB11
36  VSS_2  pwr
37  VDD_3  pwr
38  TCK/RA1
39  SCK3A/U3BTX/~U3ARTS/RF13
40  ~SS3A/U3BRX/~U3ACTS/RF12
41  AN12/ERXD0/AECRS/PMA11/RB12
42  AN13/ERXD1/AECOL/PMA10/RB13
43  AN14/ERXD2/AETXD3/PMALH/PMA1/RB14
44  AN15/ERXD3/AETXD2/OCFB/PMALL/PMA0/CN12/RB15
45  VSS_3  pwr
46  VDD_4  pwr
47  AETXD0/~SS1A/U1BRX/~U1ACTS/CN20/RD14
48  AETXD1/SCK1A/U1BTX/~U1ARTS/CN21/RD15
49  SDA3A/SDI3A/U3ARX/PMA9/CN17/RF4
50  SCL3A/SDO3A/U3ATX/PMA8/CN18/RF5
51  USBID/RF3
52  SDA1A/SDI1A/U1ARX/RF2
53  SCL1A/SDO1A/U1ATX/RF8
54  VBUS  in
55  VUSB  pwr
56  D-/RG3
57  D+/RG2
58  SCL2/RA2
59  SDA2/RA3
60  TDI/RA4
61  TDO/RA5
62  VDD_5  pwr
63  OSC1/CLKI/RC12
64  OSC2/CLKO/RC15
65  VSS_4  pwr
66  AETXCLK/SCL1/INT3/RA14
67  AETXEN/SDA1/INT4/RA15
68  RTCC/EMDIO/IC1/RD8
69  ~SS1/IC2/RD9
70  SCK1/IC3/PMCS2/PMA15/RD10
71  EMDC/IC4/PMCS1/PMA14/RD11
72  SDO1/OC1/INT0/RD0
73  SOSCI/CN1/RC13
74  SOSCO/T1CK/CN0/RC14
75  VSS_5  pwr
76  OC2/RD1
77  OC3/RD2
78  OC4/RD3
79  ETXD2/IC5/PMD12/RD12
80  ETXD3/PMD13/CN19/RD13
81  OC5/PMWR/CN13/RD4
82  PMRD/CN14/RD5
83  ETXEN/PMD14/CN15/RD6
84  ETXCLK/PMD15/CN16/RD7
85  VCAP/VDDCORE  pwr
86  VDD_6  pwr
87  ETXD1/PMD11/RF0
88  ETXD0/PMD10/RF1
89  ETXERR/PMD9/RG1
90  PMD8/RG0
91  TRCLK/RA6
92  TRD3/RA7
93  PMD0/RE0
94  PMD1/RE1
95  TRD2/RG14
96  TRD1/RG12
97  TRD0/RG13
98  PMD2/RE2
99  PMD3/RE3
100  PMD4/RE4

## Footprint TQFP100-0.5-14X14MM (pad centres in mm)
100-lead Thin Quad Flat Pack Package Outline
smd 1.5 x 0.35: 1 -8,6; 2 -8,5.5; 3 -8,5; 4 -8,4.5; 5 -8,4; 6 -8,3.5; 7 -8,3; 8 -8,2.5; 9 -8,2; 10 -8,1.5; 11 -8,1; 12 -8,0.5; 13 -8,0; 14 -8,-0.5; 15 -8,-1; 16 -8,-1.5; 17 -8,-2; 18 -8,-2.5; 19 -8,-3; 20 -8,-3.5; 21 -8,-4; 22 -8,-4.5; 23 -8,-5; 24 -8,-5.5; 25 -8,-6; 51 8,-6; 52 8,-5.5; 53 8,-5; 54 8,-4.5; 55 8,-4; 56 8,-3.5; 57 8,-3; 58 8,-2.5; 59 8,-2; 60 8,-1.5; 61 8,-1; 62 8,-0.5; 63 8,0; 64 8,0.5; 65 8,1; 66 8,1.5; 67 8,2; 68 8,2.5; 69 8,3; 70 8,3.5; 71 8,4; 72 8,4.5; 73 8,5; 74 8,5.5; 75 8,6
smd 0.35 x 1.5: 26 -6,-8; 27 -5.5,-8; 28 -5,-8; 29 -4.5,-8; 30 -4,-8; 31 -3.5,-8; 32 -3,-8; 33 -2.5,-8; 34 -2,-8; 35 -1.5,-8; 36 -1,-8; 37 -0.5,-8; 38 0,-8; 39 0.5,-8; 40 1,-8; 41 1.5,-8; 42 2,-8; 43 2.5,-8; 44 3,-8; 45 3.5,-8; 46 4,-8; 47 4.5,-8; 48 5,-8; 49 5.5,-8; 50 6,-8; 76 6,8; 77 5.5,8; 78 5,8; 79 4.5,8; 80 4,8; 81 3.5,8; 82 3,8; 83 2.5,8; 84 2,8; 85 1.5,8; 86 1,8; 87 0.5,8; 88 0,8; 89 -0.5,8; 90 -1,8; 91 -1.5,8; 92 -2,8; 93 -2.5,8; 94 -3,8; 95 -3.5,8; 96 -4,8; 97 -4.5,8; 98 -5,8; 99 -5.5,8; 100 -6,8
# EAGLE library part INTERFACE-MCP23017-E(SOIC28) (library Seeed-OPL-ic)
310070050

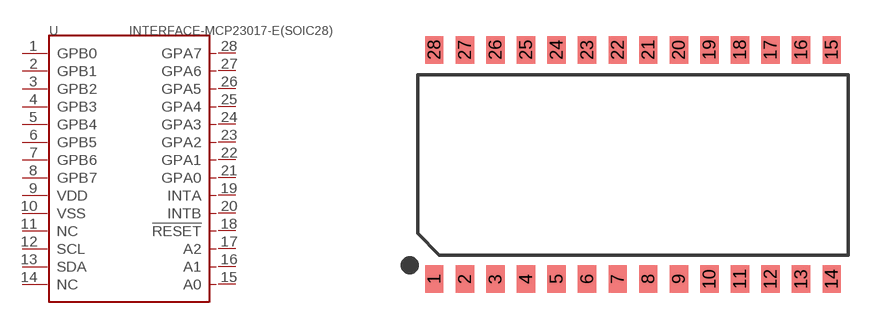
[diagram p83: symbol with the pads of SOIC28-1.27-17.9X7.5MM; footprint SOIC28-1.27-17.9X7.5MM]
Designator prefix U

## INTERFACE-MCP23017-E(SOIC28) (MPN: MCP23017-E/SO; VALUE: MCP23017-E/SO-SOIC28)  [SOIC28-1.27-17.9X7.5MM]
1  GPB0
2  GPB1
3  GPB2
4  GPB3
5  GPB4
6  GPB5
7  GPB6
8  GPB7
9  VDD
10  VSS
11  NC
12  SCL
13  SDA
14  NC
15  A0
16  A1
17  A2
18  !RESET
19  INTA
20  INTB
21  GPA0
22  GPA1
23  GPA2
24  GPA3
25  GPA4
26  GPA5
27  GPA6
28  GPA7

## Footprint SOIC28-1.27-17.9X7.5MM (pad centres in mm)
smd 0.762 x 1.143: 1 -8.255,-4.75; 2 -6.985,-4.75; 3 -5.715,-4.75; 4 -4.445,-4.75; 5 -3.175,-4.75; 6 -1.905,-4.75; 7 -0.635,-4.75; 8 0.635,-4.75; 9 1.905,-4.75; 10 3.175,-4.75; 11 4.445,-4.75; 12 5.715,-4.75; 13 6.985,-4.75; 14 8.255,-4.75; 15 8.255,4.775; 16 6.985,4.775; 17 5.715,4.775; 18 4.445,4.775; 19 3.175,4.775; 20 1.905,4.775; 21 0.635,4.775; 22 -0.635,4.775; 23 -1.905,4.775; 24 -3.175,4.775; 25 -4.445,4.775; 26 -5.715,4.775; 27 -6.985,4.775; 28 -8.255,4.775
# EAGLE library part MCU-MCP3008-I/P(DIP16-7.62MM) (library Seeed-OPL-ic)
310990040

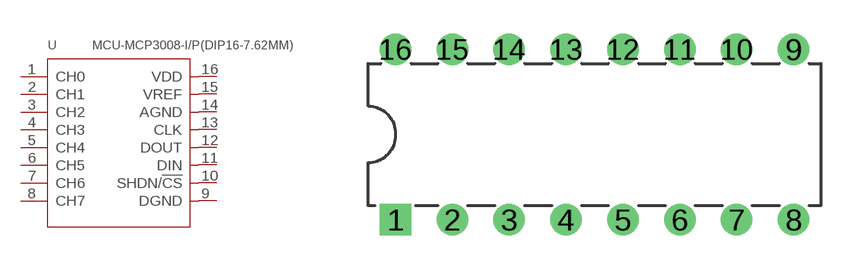
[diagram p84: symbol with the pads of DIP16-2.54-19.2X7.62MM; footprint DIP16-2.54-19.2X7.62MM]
Designator prefix U

## MCU-MCP3008-I/P(DIP16-7.62MM) (MPN: MCP3008-I/P; VALUE: MCP3008-I/P-DIP16)  [DIP16-2.54-19.2X7.62MM]
1  CH0  out
2  CH1  in
3  CH2  out
4  CH3  in
5  CH4  in
6  CH5  in
7  CH6  out
8  CH7  in
9  DGND  out
10  SHDN/!CS  out
11  DIN  in
12  DOUT  in
13  CLK  out
14  AGND  in
15  VREF  in
16  VDD  sup

## Footprint DIP16-2.54-19.2X7.62MM (pad centres in mm)
drill 0.9 pad 1.4 square: 1 -8.89,-3.81
drill 0.9 pad 1.4: 2 -6.35,-3.81; 3 -3.81,-3.81; 4 -1.27,-3.81; 5 1.27,-3.81; 6 3.81,-3.81; 7 6.35,-3.81; 8 8.89,-3.81; 9 8.89,3.81; 10 6.35,3.81; 11 3.81,3.81; 12 1.27,3.81; 13 -1.27,3.81; 14 -3.81,3.81; 15 -6.35,3.81; 16 -8.89,3.81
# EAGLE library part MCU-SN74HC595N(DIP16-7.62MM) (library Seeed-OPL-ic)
310050081

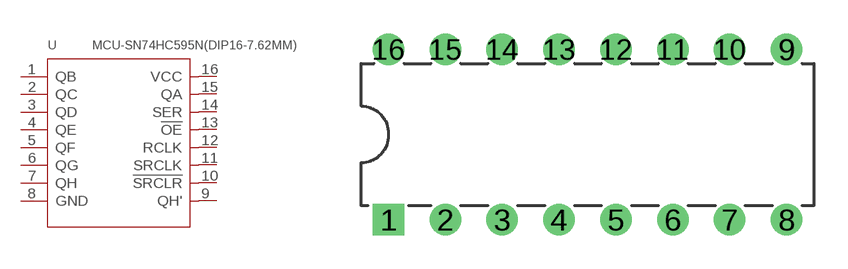
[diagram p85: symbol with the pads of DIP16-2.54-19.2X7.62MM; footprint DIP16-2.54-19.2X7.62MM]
Designator prefix U

## MCU-SN74HC595N(DIP16-7.62MM) (MPN: SN74HC595N; VALUE: SN74HC595N-DIP16)  [DIP16-2.54-19.2X7.62MM]
1  QB  out
2  QC  in
3  QD  out
4  QE  in
5  QF  in
6  QG  in
7  QH  out
8  GND  in
9  QH'  out
10  !SRCLR  out
11  SRCLK  in
12  RCLK  in
13  !OE  out
14  SER  in
15  QA  in
16  VCC  sup

## Footprint DIP16-2.54-19.2X7.62MM (pad centres in mm)
drill 0.9 pad 1.4 square: 1 -8.89,-3.81
drill 0.9 pad 1.4: 2 -6.35,-3.81; 3 -3.81,-3.81; 4 -1.27,-3.81; 5 1.27,-3.81; 6 3.81,-3.81; 7 6.35,-3.81; 8 8.89,-3.81; 9 8.89,3.81; 10 6.35,3.81; 11 3.81,3.81; 12 1.27,3.81; 13 -1.27,3.81; 14 -3.81,3.81; 15 -6.35,3.81; 16 -8.89,3.81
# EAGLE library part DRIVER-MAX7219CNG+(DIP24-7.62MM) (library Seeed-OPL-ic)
310030263

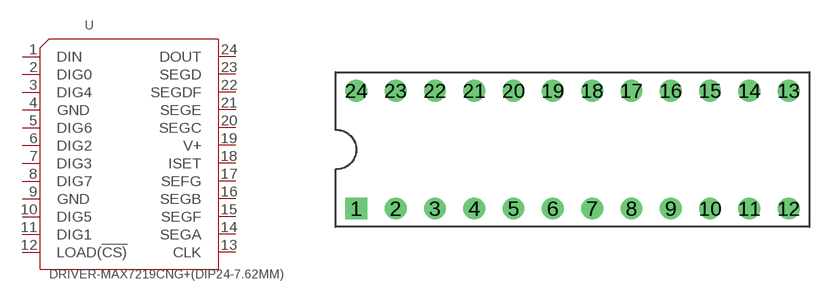
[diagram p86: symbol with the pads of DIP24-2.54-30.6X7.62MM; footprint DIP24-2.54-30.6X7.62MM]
Designator prefix U

## DRIVER-MAX7219CNG+(DIP24-7.62MM) (MPN: MAX7219CNG+; VALUE: led display 8dgt)  [DIP24-2.54-30.6X7.62MM]
1  DIN
2  DIG0
3  DIG4
4  GND
5  DIG6
6  DIG2
7  DIG3
8  DIG7
9  GND
10  DIG5
11  DIG1
12  LOAD(!CS)
13  CLK
14  SEGA
15  SEGF
16  SEGB
17  SEFG
18  ISET
19  V+
20  SEGC
21  SEGE
22  SEGDF
23  SEGD
24  DOUT

## Footprint DIP24-2.54-30.6X7.62MM (pad centres in mm)
drill 0.9 pad 1.4 square: 1 -13.97,-3.81
drill 0.9 pad 1.4: 2 -11.43,-3.81; 3 -8.89,-3.81; 4 -6.35,-3.81; 5 -3.81,-3.81; 6 -1.27,-3.81; 7 1.27,-3.81; 8 3.81,-3.81; 9 6.35,-3.81; 10 8.89,-3.81; 11 11.43,-3.81; 12 13.97,-3.81; 13 13.97,3.81; 14 11.43,3.81; 15 8.89,3.81; 16 6.35,3.81; 17 3.81,3.81; 18 1.27,3.81; 19 -1.27,3.81; 20 -3.81,3.81; 21 -6.35,3.81; 22 -8.89,3.81; 23 -11.43,3.81; 24 -13.97,3.81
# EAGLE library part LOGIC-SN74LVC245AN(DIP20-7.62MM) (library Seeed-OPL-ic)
310050092

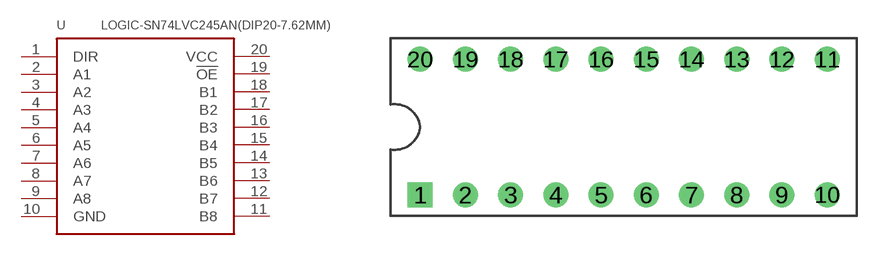
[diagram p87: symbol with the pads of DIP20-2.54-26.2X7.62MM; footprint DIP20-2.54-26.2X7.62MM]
Designator prefix U

## LOGIC-SN74LVC245AN(DIP20-7.62MM) (MPN: SN74LVC245AN; VALUE: TRANSCEIVER-8BIT)  [DIP20-2.54-26.2X7.62MM]
1  DIR
2  A1
3  A2
4  A3
5  A4
6  A5
7  A6
8  A7
9  A8
10  GND
11  B8
12  B7
13  B6
14  B5
15  B4
16  B3
17  B2
18  B1
19  !OE
20  VCC

## Footprint DIP20-2.54-26.2X7.62MM (pad centres in mm)
drill 0.9 pad 1.4 square: 1 -11.43,-3.81
drill 0.9 pad 1.4: 2 -8.89,-3.81; 3 -6.35,-3.81; 4 -3.81,-3.81; 5 -1.27,-3.81; 6 1.27,-3.81; 7 3.81,-3.81; 8 6.35,-3.81; 9 8.89,-3.81; 10 11.43,-3.81; 11 11.43,3.81; 12 8.89,3.81; 13 6.35,3.81; 14 3.81,3.81; 15 1.27,3.81; 16 -1.27,3.81; 17 -3.81,3.81; 18 -6.35,3.81; 19 -8.89,3.81; 20 -11.43,3.81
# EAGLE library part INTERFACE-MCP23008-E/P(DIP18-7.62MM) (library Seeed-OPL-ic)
310070051

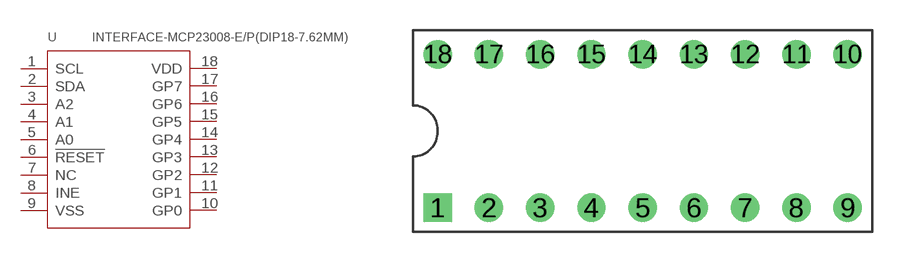
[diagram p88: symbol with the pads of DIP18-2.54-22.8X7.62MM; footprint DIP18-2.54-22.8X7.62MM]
Designator prefix U

## INTERFACE-MCP23008-E/P(DIP18-7.62MM) (MPN: MCP23008-E/P; VALUE: MCP23008-E/P-DIP18)  [DIP18-2.54-22.8X7.62MM]
1  SCL
2  SDA
3  A2
4  A1
5  A0
6  !RESET
7  NC
8  INE
9  VSS
10  GP0
11  GP1
12  GP2
13  GP3
14  GP4
15  GP5
16  GP6
17  GP7
18  VDD

## Footprint DIP18-2.54-22.8X7.62MM (pad centres in mm)
drill 0.9 pad 1.4 square: 1 -10.16,-3.81
drill 0.9 pad 1.4: 2 -7.62,-3.81; 3 -5.08,-3.81; 4 -2.54,-3.81; 5 0,-3.81; 6 2.54,-3.81; 7 5.08,-3.81; 8 7.62,-3.81; 9 10.16,-3.81; 10 10.16,3.81; 11 7.62,3.81; 12 5.08,3.81; 13 2.54,3.81; 14 0,3.81; 15 -2.54,3.81; 16 -5.08,3.81; 17 -7.62,3.81; 18 -10.16,3.81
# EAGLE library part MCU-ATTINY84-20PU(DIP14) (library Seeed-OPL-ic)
310010126

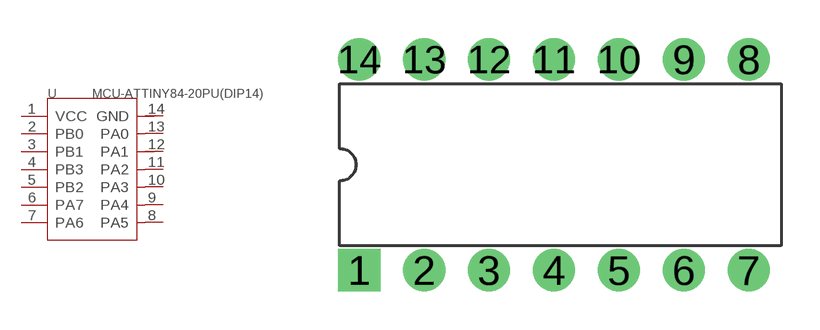
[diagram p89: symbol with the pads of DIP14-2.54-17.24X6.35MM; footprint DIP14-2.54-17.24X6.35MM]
Designator prefix U

## MCU-ATTINY84-20PU(DIP14) (MPN: ATTINY84-20PU; VALUE: ATTINY84-20PU DIP14)  [DIP14-2.54-17.24X6.35MM]
1  VCC
2  PB0
3  PB1
4  PB3
5  PB2
6  PA7
7  PA6
8  PA5
9  PA4
10  PA3
11  PA2
12  PA1
13  PA0
14  GND

## Footprint DIP14-2.54-17.24X6.35MM (pad centres in mm)
drill 0.889 pad 1.651 square: 1 -7.62,-4.128
drill 0.889 pad 1.651: 2 -5.08,-4.128; 3 -2.54,-4.128; 4 0,-4.128; 5 2.54,-4.128; 6 5.08,-4.128; 7 7.62,-4.128; 8 7.62,4.128; 9 5.08,4.128; 10 2.54,4.128; 11 0,4.128; 12 -2.54,4.128; 13 -5.08,4.128; 14 -7.62,4.128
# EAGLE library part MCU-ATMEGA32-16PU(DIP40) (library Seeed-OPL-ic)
310010127

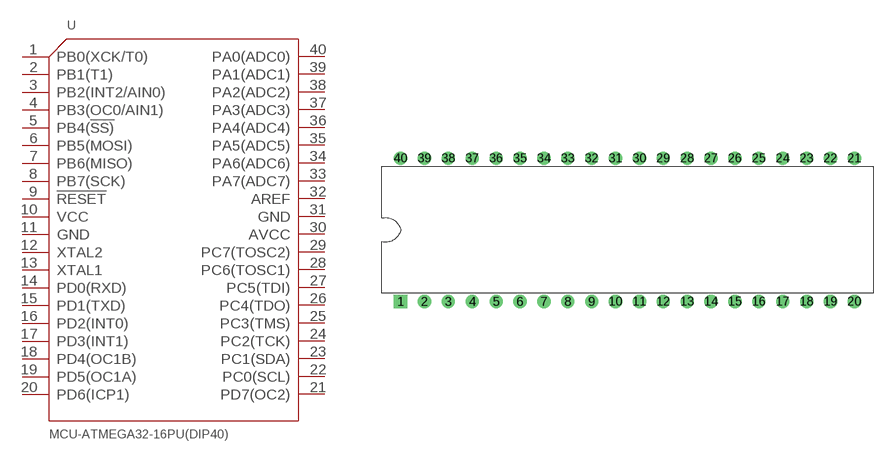
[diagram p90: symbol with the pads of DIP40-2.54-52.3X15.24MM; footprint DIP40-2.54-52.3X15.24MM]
Designator prefix U

## MCU-ATMEGA32-16PU(DIP40) (MPN: ATMEGA32-16PU; VALUE: ATMEGA32-16PU DIP40)  [DIP40-2.54-52.3X15.24MM]
1  PB0(XCK/T0)
2  PB1(T1)
3  PB2(INT2/AIN0)
4  PB3(OC0/AIN1)
5  PB4(!SS)
6  PB5(MOSI)
7  PB6(MISO)
8  PB7(SCK)
9  !RESET
10  VCC
11  GND
12  XTAL2
13  XTAL1
14  PD0(RXD)
15  PD1(TXD)
16  PD2(INT0)
17  PD3(INT1)
18  PD4(OC1B)
19  PD5(OC1A)
20  PD6(ICP1)
21  PD7(OC2)
22  PC0(SCL)
23  PC1(SDA)
24  PC2(TCK)
25  PC3(TMS)
26  PC4(TDO)
27  PC5(TDI)
28  PC6(TOSC1)
29  PC7(TOSC2)
30  AVCC
31  GND
32  AREF
33  PA7(ADC7)
34  PA6(ADC6)
35  PA5(ADC5)
36  PA4(ADC4)
37  PA3(ADC3)
38  PA2(ADC2)
39  PA1(ADC1)
40  PA0(ADC0)

## Footprint DIP40-2.54-52.3X15.24MM (pad centres in mm)
drill 0.9 pad 1.4 square: 1 -24.13,-7.62
drill 0.9 pad 1.4: 2 -21.59,-7.62; 3 -19.05,-7.62; 4 -16.51,-7.62; 5 -13.97,-7.62; 6 -11.43,-7.62; 7 -8.89,-7.62; 8 -6.35,-7.62; 9 -3.81,-7.62; 10 -1.27,-7.62; 11 1.27,-7.62; 12 3.81,-7.62; 13 6.35,-7.62; 14 8.89,-7.62; 15 11.43,-7.62; 16 13.97,-7.62; 17 16.51,-7.62; 18 19.05,-7.62; 19 21.59,-7.62; 20 24.13,-7.62; 21 24.13,7.62; 22 21.59,7.62; 23 19.05,7.62; 24 16.51,7.62; 25 13.97,7.62; 26 11.43,7.62; 27 8.89,7.62; 28 6.35,7.62; 29 3.81,7.62; 30 1.27,7.62; 31 -1.27,7.62; 32 -3.81,7.62; 33 -6.35,7.62; 34 -8.89,7.62; 35 -11.43,7.62; 36 -13.97,7.62; 37 -16.51,7.62; 38 -19.05,7.62; 39 -21.59,7.62; 40 -24.13,7.62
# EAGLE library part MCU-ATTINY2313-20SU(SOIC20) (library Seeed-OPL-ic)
310010128

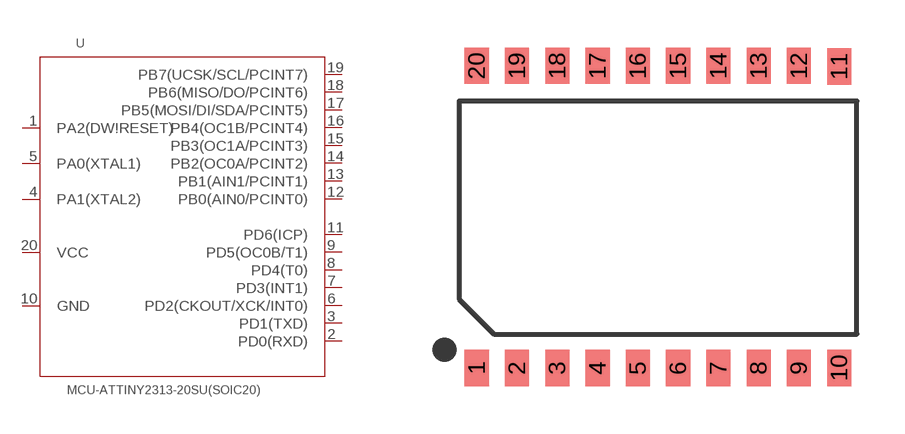
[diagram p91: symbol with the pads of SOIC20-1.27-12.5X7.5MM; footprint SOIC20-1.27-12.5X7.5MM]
Designator prefix U

## MCU-ATTINY2313-20SU(SOIC20) (MPN: ATTINY2313-20SU; VALUE: ATTINY2313-20SU soic20)  [SOIC20-1.27-12.5X7.5MM]
1  PA2(DW\!RESET)  out
2  PD0(RXD)  in
3  PD1(TXD)  out
4  PA1(XTAL2)  in
5  PA0(XTAL1)  in
6  PD2(CKOUT/XCK/INT0)  in
7  PD3(INT1)  out
8  PD4(T0)  in
9  PD5(OC0B/T1)  in
10  GND  in
11  PD6(ICP)  out
12  PB0(AIN0/PCINT0)  out
13  PB1(AIN1/PCINT1)  out
14  PB2(OC0A/PCINT2)  out
15  PB3(OC1A/PCINT3)  in
16  PB4(OC1B/PCINT4)  in
17  PB5(MOSI/DI/SDA/PCINT5)  out
18  PB6(MISO/DO/PCINT6)  in
19  PB7(UCSK/SCL/PCINT7)  in
20  VCC  sup

## Footprint SOIC20-1.27-12.5X7.5MM (pad centres in mm)
Small Outline Package
smd 0.762 x 1.143: 1 -5.715,-4.75; 2 -4.445,-4.75; 3 -3.175,-4.75; 4 -1.905,-4.75; 5 -0.635,-4.75; 6 0.635,-4.75; 7 1.905,-4.75; 8 3.175,-4.75; 9 4.445,-4.75; 10 5.715,-4.75; 11 5.715,4.75; 12 4.445,4.775; 13 3.175,4.775; 14 1.905,4.775; 15 0.635,4.775; 16 -0.635,4.775; 17 -1.905,4.775; 18 -3.175,4.775; 19 -4.445,4.775; 20 -5.715,4.775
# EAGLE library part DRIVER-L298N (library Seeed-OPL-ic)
310030269

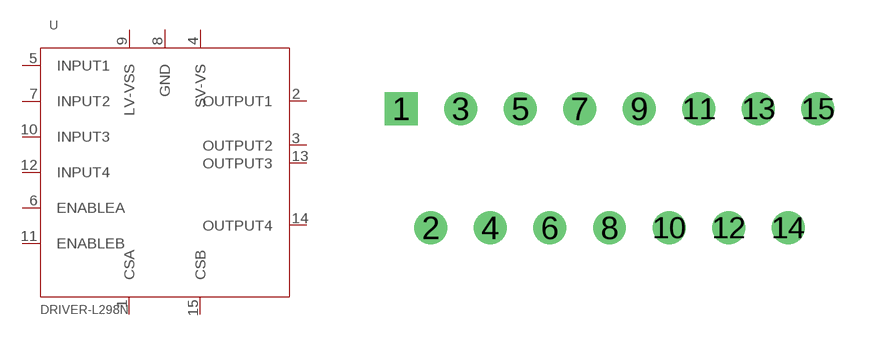
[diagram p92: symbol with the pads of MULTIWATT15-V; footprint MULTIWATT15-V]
Designator prefix U

## DRIVER-L298N (MPN: L298N; VALUE: L298N-Multiwatt15-V)  [MULTIWATT15-V]
1  CSA
2  OUTPUT1
3  OUTPUT2
4  SV-VS
5  INPUT1
6  ENABLEA
7  INPUT2
8  GND
9  LV-VSS
10  INPUT3
11  ENABLEB
12  INPUT4
13  OUTPUT3
14  OUTPUT4
15  CSB

## Footprint MULTIWATT15-V (pad centres in mm)
drill 0.9 square: 1 -8.89,0
drill 0.9: 2 -7.62,-5.08; 3 -6.35,0; 4 -5.08,-5.08; 5 -3.81,0; 6 -2.54,-5.08; 7 -1.27,0; 8 0,-5.08; 9 1.27,0; 10 2.54,-5.08; 11 3.81,0; 12 5.08,-5.08; 13 6.35,0; 14 7.62,-5.08; 15 8.89,0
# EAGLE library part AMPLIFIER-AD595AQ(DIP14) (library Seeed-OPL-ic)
310030269

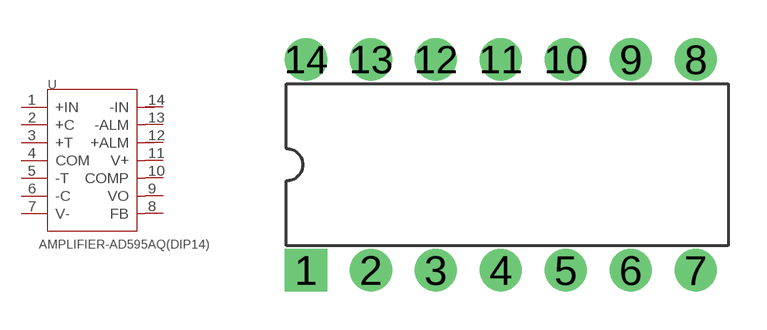
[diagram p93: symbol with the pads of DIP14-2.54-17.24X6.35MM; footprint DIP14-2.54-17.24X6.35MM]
Designator prefix U

## AMPLIFIER-AD595AQ(DIP14) (MPN: AD595AQ; VALUE: AD595AQ-DIP14)  [DIP14-2.54-17.24X6.35MM]
1  +IN
2  +C
3  +T
4  COM
5  -T
6  -C
7  V-
8  FB
9  VO
10  COMP
11  V+
12  +ALM
13  -ALM
14  -IN

## Footprint DIP14-2.54-17.24X6.35MM (pad centres in mm)
drill 0.889 pad 1.651 square: 1 -7.62,-4.128
drill 0.889 pad 1.651: 2 -5.08,-4.128; 3 -2.54,-4.128; 4 0,-4.128; 5 2.54,-4.128; 6 5.08,-4.128; 7 7.62,-4.128; 8 7.62,4.128; 9 5.08,4.128; 10 2.54,4.128; 11 0,4.128; 12 -2.54,4.128; 13 -5.08,4.128; 14 -7.62,4.128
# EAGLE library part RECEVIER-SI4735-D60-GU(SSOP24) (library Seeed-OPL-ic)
317020004

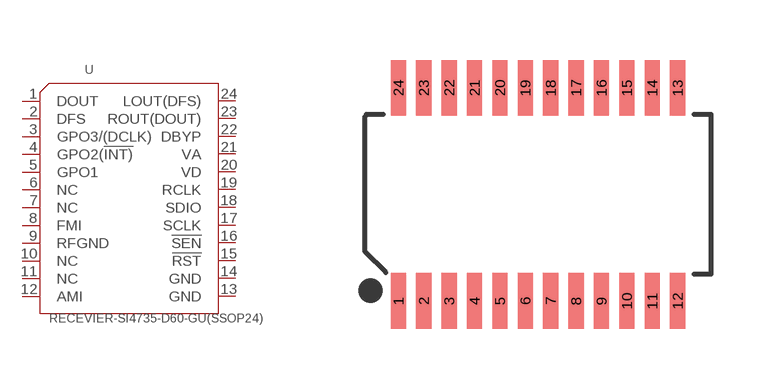
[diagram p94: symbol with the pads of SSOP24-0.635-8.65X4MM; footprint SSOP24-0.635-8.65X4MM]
Designator prefix U

## RECEVIER-SI4735-D60-GU(SSOP24) (MPN: SI4735-D60-GU; VALUE: SI4735-D60-GU-SSOP24)  [SSOP24-0.635-8.65X4MM]
1  DOUT
2  DFS
3  GPO3/(DCLK)
4  GPO2(!INT)
5  GPO1
6  NC
7  NC
8  FMI
9  RFGND
10  NC
11  NC
12  AMI
13  GND
14  GND
15  !RST
16  !SEN
17  SCLK
18  SDIO
19  RCLK
20  VD
21  VA
22  DBYP
23  ROUT(DOUT)
24  LOUT(DFS)

## Footprint SSOP24-0.635-8.65X4MM (pad centres in mm)
smd 0.381 x 1.397: 1 -3.493,-2.667; 2 -2.857,-2.667; 3 -2.223,-2.667; 4 -1.587,-2.667; 5 -0.953,-2.667; 6 -0.318,-2.667; 7 0.318,-2.667; 8 0.953,-2.667; 9 1.587,-2.667; 10 2.223,-2.667; 11 2.857,-2.667; 12 3.493,-2.667; 13 3.493,2.667; 14 2.857,2.667; 15 2.223,2.667; 16 1.587,2.667; 17 0.953,2.667; 18 0.318,2.667; 19 -0.318,2.667; 20 -0.953,2.667; 21 -1.587,2.667; 22 -2.223,2.667; 23 -2.857,2.667; 24 -3.493,2.667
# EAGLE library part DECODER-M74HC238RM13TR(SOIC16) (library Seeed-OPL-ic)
310080006

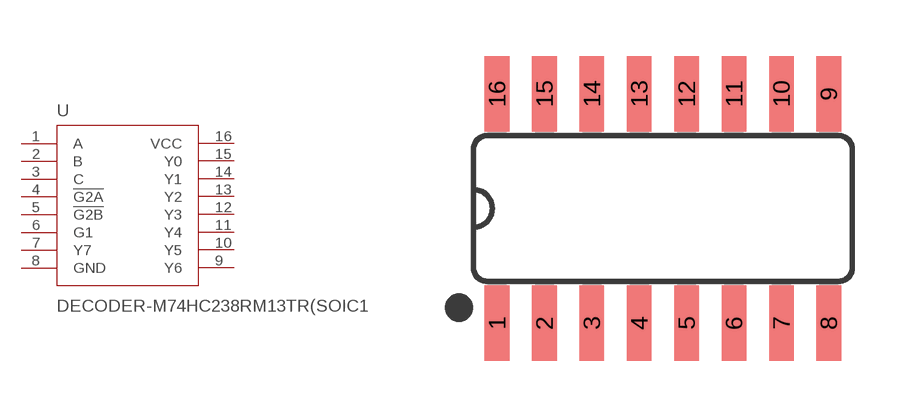
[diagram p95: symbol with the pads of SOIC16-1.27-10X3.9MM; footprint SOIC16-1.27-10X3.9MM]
Designator prefix U

## DECODER-M74HC238RM13TR(SOIC16) (MPN: M74HC238RM13TR; VALUE: M74HC238RM13TR-SOIC16)  [SOIC16-1.27-10X3.9MM]
1  A
2  B
3  C
4  !G2A
5  !G2B  in
6  G1
7  Y7
8  GND
9  Y6
10  Y5
11  Y4
12  Y3
13  Y2
14  Y1
15  Y0
16  VCC

## Footprint SOIC16-1.27-10X3.9MM (pad centres in mm)
Small Outline package 150 mil
smd 0.66 x 2.032: 1 -4.445,-3.073; 2 -3.175,-3.073; 3 -1.905,-3.073; 4 -0.635,-3.073; 5 0.635,-3.073; 6 1.905,-3.073; 7 3.175,-3.073; 8 4.445,-3.073; 9 4.445,3.073; 10 3.175,3.073; 11 1.905,3.073; 12 0.635,3.073; 13 -0.635,3.073; 14 -1.905,3.073; 15 -3.175,3.073; 16 -4.445,3.073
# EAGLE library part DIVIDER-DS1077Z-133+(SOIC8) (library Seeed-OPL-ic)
310110019

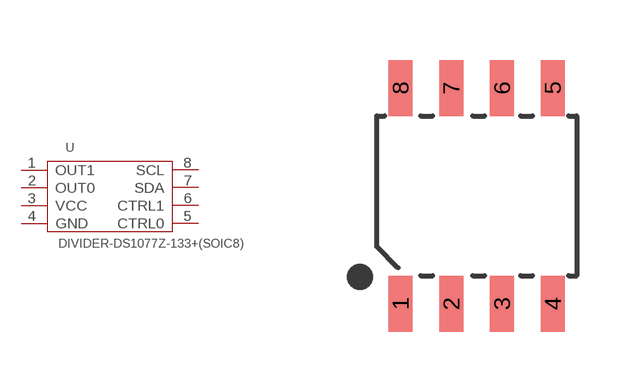
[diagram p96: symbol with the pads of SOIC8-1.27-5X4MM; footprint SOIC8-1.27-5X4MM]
Designator prefix U

## DIVIDER-DS1077Z-133+(SOIC8) (MPN: DS1077Z-133+; VALUE: DS1077Z-133+-SOIC8)  [SOIC8-1.27-5X4MM]
1  OUT1
2  OUT0
3  VCC
4  GND
5  CTRL0
6  CTRL1
7  SDA
8  SCL

## Footprint SOIC8-1.27-5X4MM (pad centres in mm)
smd 0.6 x 1.4: 1 -1.905,-2.7; 2 -0.635,-2.7; 3 0.635,-2.7; 4 1.905,-2.7; 5 1.905,2.7; 6 0.635,2.7; 7 -0.635,2.7; 8 -1.905,2.7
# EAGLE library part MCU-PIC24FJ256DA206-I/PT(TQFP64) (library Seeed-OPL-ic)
310010035

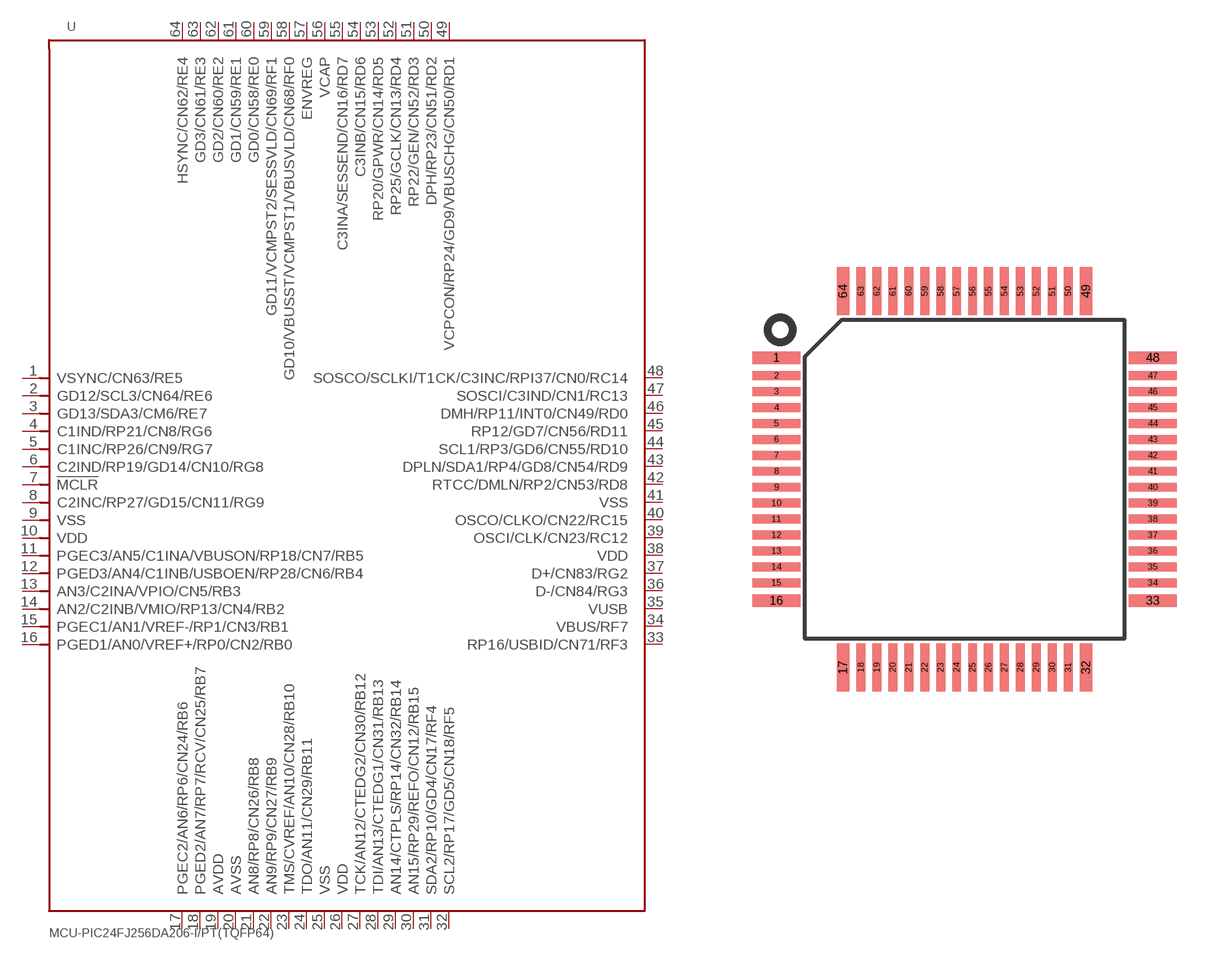
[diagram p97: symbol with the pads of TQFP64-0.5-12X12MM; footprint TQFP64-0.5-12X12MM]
Designator prefix U

## MCU-PIC24FJ256DA206-I/PT(TQFP64) (MPN: PIC24FJ256DA206-I/PT; VALUE: PIC24FJ256DA206-I/PT-TQFP64)  [TQFP64-0.5-12X12MM]
1  VSYNC/CN63/RE5
2  GD12/SCL3/CN64/RE6
3  GD13/SDA3/CM6/RE7
4  C1IND/RP21/CN8/RG6
5  C1INC/RP26/CN9/RG7
6  C2IND/RP19/GD14/CN10/RG8
7  !MCLR
8  C2INC/RP27/GD15/CN11/RG9
9  VSS
10  VDD
11  PGEC3/AN5/C1INA/VBUSON/RP18/CN7/RB5
12  PGED3/AN4/C1INB/USBOEN/RP28/CN6/RB4
13  AN3/C2INA/VPIO/CN5/RB3
14  AN2/C2INB/VMIO/RP13/CN4/RB2
15  PGEC1/AN1/VREF-/RP1/CN3/RB1
16  PGED1/AN0/VREF+/RP0/CN2/RB0
17  PGEC2/AN6/RP6/CN24/RB6
18  PGED2/AN7/RP7/RCV/CN25/RB7
19  AVDD
20  AVSS
21  AN8/RP8/CN26/RB8
22  AN9/RP9/CN27/RB9
23  TMS/CVREF/AN10/CN28/RB10
24  TDO/AN11/CN29/RB11
25  VSS
26  VDD
27  TCK/AN12/CTEDG2/CN30/RB12
28  TDI/AN13/CTEDG1/CN31/RB13
29  AN14/CTPLS/RP14/CN32/RB14
30  AN15/RP29/REFO/CN12/RB15
31  SDA2/RP10/GD4/CN17/RF4
32  SCL2/RP17/GD5/CN18/RF5
33  RP16/USBID/CN71/RF3
34  VBUS/RF7
35  VUSB
36  D-/CN84/RG3
37  D+/CN83/RG2
38  VDD
39  OSCI/CLK/CN23/RC12
40  OSCO/CLKO/CN22/RC15
41  VSS
42  RTCC/DMLN/RP2/CN53/RD8
43  DPLN/SDA1/RP4/GD8/CN54/RD9
44  SCL1/RP3/GD6/CN55/RD10
45  RP12/GD7/CN56/RD11
46  DMH/RP11/INT0/CN49/RD0
47  SOSCI/C3IND/CN1/RC13
48  SOSCO/SCLKI/T1CK/C3INC/RPI37/CN0/RC14
49  VCPCON/RP24/GD9/VBUSCHG/CN50/RD1
50  DPH/RP23/CN51/RD2
51  RP22/GEN/CN52/RD3
52  RP25/GCLK/CN13/RD4
53  RP20/GPWR/CN14/RD5
54  C3INB/CN15/RD6
55  C3INA/SESSEND/CN16/RD7
56  VCAP
57  ENVREG
58  GD10/VBUSST/VCMPST1/VBUSVLD/CN68/RF0
59  GD11/VCMPST2/SESSVLD/CN69/RF1
60  GD0/CN58/RE0
61  GD1/CN59/RE1
62  GD2/CN60/RE2
63  GD3/CN61/RE3
64  HSYNC/CN62/RE4

## Footprint TQFP64-0.5-12X12MM (pad centres in mm)
smd 1.5 x 0.4: 1 -5.9,3.81; 16 -5.9,-3.81; 33 5.9,-3.81; 48 5.9,3.81
smd 1.5 x 0.28: 2 -5.9,3.25; 3 -5.9,2.75; 4 -5.9,2.25; 5 -5.9,1.75; 6 -5.9,1.25; 7 -5.9,0.75; 8 -5.9,0.25; 9 -5.9,-0.25; 10 -5.9,-0.75; 11 -5.9,-1.25; 12 -5.9,-1.75; 13 -5.9,-2.25; 14 -5.9,-2.75; 15 -5.9,-3.25; 34 5.9,-3.25; 35 5.9,-2.75; 36 5.9,-2.25; 37 5.9,-1.75; 38 5.9,-1.25; 39 5.9,-0.75; 40 5.9,-0.25; 41 5.9,0.25; 42 5.9,0.75; 43 5.9,1.25; 44 5.9,1.75; 45 5.9,2.25; 46 5.9,2.75; 47 5.9,3.25
smd 0.4 x 1.5: 17 -3.81,-5.9; 32 3.81,-5.9; 49 3.81,5.9; 64 -3.81,5.9
smd 0.28 x 1.5: 18 -3.25,-5.9; 19 -2.75,-5.9; 20 -2.25,-5.9; 21 -1.75,-5.9; 22 -1.25,-5.9; 23 -0.75,-5.9; 24 -0.25,-5.9; 25 0.25,-5.9; 26 0.75,-5.9; 27 1.25,-5.9; 28 1.75,-5.9; 29 2.25,-5.9; 30 2.75,-5.9; 31 3.25,-5.9; 50 3.25,5.9; 51 2.75,5.9; 52 2.25,5.9; 53 1.75,5.9; 54 1.25,5.9; 55 0.75,5.9; 56 0.25,5.9; 57 -0.25,5.9; 58 -0.75,5.9; 59 -1.25,5.9; 60 -1.75,5.9; 61 -2.25,5.9; 62 -2.75,5.9; 63 -3.25,5.9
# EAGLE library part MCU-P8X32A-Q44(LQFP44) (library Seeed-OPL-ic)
310010129

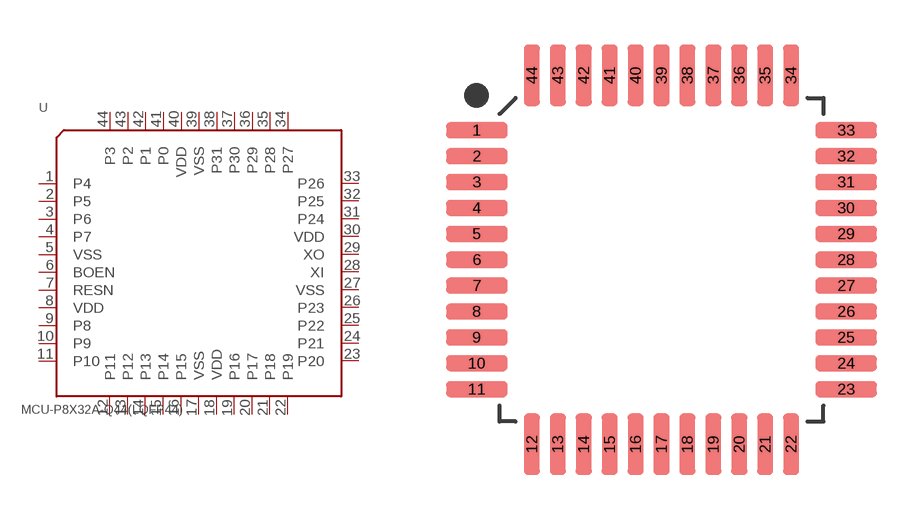
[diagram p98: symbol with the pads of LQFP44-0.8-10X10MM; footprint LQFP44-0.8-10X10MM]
Designator prefix U

## MCU-P8X32A-Q44(LQFP44) (MPN: P8X32A-Q44; VALUE: P8X32A-Q44-LQFP44)  [LQFP44-0.8-10X10MM]
1  P4
2  P5
3  P6
4  P7
5  VSS
6  BOEN
7  RESN
8  VDD
9  P8
10  P9
11  P10
12  P11
13  P12
14  P13
15  P14
16  P15
17  VSS
18  VDD
19  P16
20  P17
21  P18
22  P19
23  P20
24  P21
25  P22
26  P23
27  VSS
28  XI
29  XO
30  VDD
31  P24
32  P25
33  P26
34  P27
35  P28
36  P29
37  P30
38  P31
39  VSS
40  VDD
41  P0
42  P1
43  P2
44  P3

## Footprint LQFP44-0.8-10X10MM (pad centres in mm)
smd 1.9 x 0.5: 1 -5.7,4; 2 -5.7,3.2; 3 -5.7,2.4; 4 -5.7,1.6; 5 -5.7,0.8; 6 -5.7,0; 7 -5.7,-0.8; 8 -5.7,-1.6; 9 -5.7,-2.4; 10 -5.7,-3.2; 11 -5.7,-4; 23 5.7,-4; 24 5.7,-3.2; 25 5.7,-2.4; 26 5.7,-1.6; 27 5.7,-0.8; 28 5.7,0; 29 5.7,0.8; 30 5.7,1.6; 31 5.7,2.4; 32 5.7,3.2; 33 5.7,4
smd 0.5 x 1.9: 12 -4,-5.7; 13 -3.2,-5.7; 14 -2.4,-5.7; 15 -1.6,-5.7; 16 -0.8,-5.7; 17 0,-5.7; 18 0.8,-5.7; 19 1.6,-5.7; 20 2.4,-5.7; 21 3.2,-5.7; 22 4,-5.7; 34 4,5.7; 35 3.2,5.7; 36 2.4,5.7; 37 1.6,5.7; 38 0.8,5.7; 39 0,5.7; 40 -0.8,5.7; 41 -1.6,5.7; 42 -2.4,5.7; 43 -3.2,5.7; 44 -4,5.7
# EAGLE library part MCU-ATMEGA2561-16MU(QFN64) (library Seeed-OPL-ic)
310010130

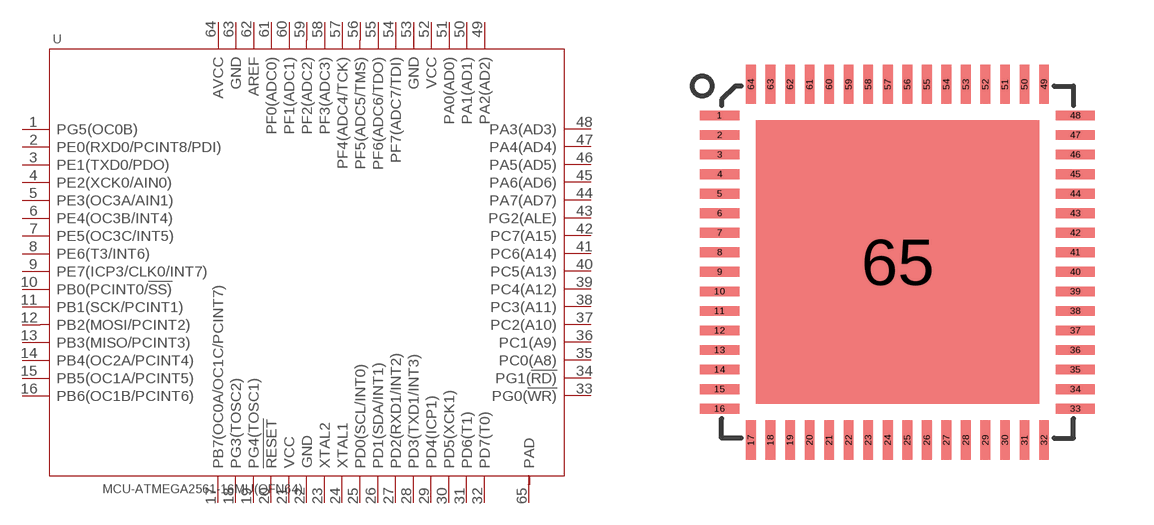
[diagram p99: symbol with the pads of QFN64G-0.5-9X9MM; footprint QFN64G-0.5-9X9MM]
Designator prefix U

## MCU-ATMEGA2561-16MU(QFN64) (MPN: ATMEGA2561-16MU; VALUE: ATMEGA2561-16MU-QFN64)  [QFN64G-0.5-9X9MM]
1  PG5(OC0B)
2  PE0(RXD0/PCINT8/PDI)
3  PE1(TXD0/PDO)
4  PE2(XCK0/AIN0)
5  PE3(OC3A/AIN1)
6  PE4(OC3B/INT4)
7  PE5(OC3C/INT5)
8  PE6(T3/INT6)
9  PE7(ICP3/CLK0/INT7)
10  PB0(PCINT0/!SS)
11  PB1(SCK/PCINT1)
12  PB2(MOSI/PCINT2)
13  PB3(MISO/PCINT3)
14  PB4(OC2A/PCINT4)
15  PB5(OC1A/PCINT5)
16  PB6(OC1B/PCINT6)
17  PB7(OC0A/OC1C/PCINT7)
18  PG3(TOSC2)
19  PG4(TOSC1)
20  !RESET
21  VCC
22  GND
23  XTAL2
24  XTAL1
25  PD0(SCL/INT0)
26  PD1(SDA/INT1)
27  PD2(RXD1/INT2)
28  PD3(TXD1/INT3)
29  PD4(ICP1)
30  PD5(XCK1)
31  PD6(T1)
32  PD7(T0)
33  PG0(!WR)
34  PG1(!RD)
35  PC0(A8)
36  PC1(A9)
37  PC2(A10)
38  PC3(A11)
39  PC4(A12)
40  PC5(A13)
41  PC6(A14)
42  PC7(A15)
43  PG2(ALE)
44  PA7(AD7)
45  PA6(AD6)
46  PA5(AD5)
47  PA4(AD4)
48  PA3(AD3)
49  PA2(AD2)
50  PA1(AD1)
51  PA0(AD0)
52  VCC
53  GND
54  PF7(ADC7/TDI)
55  PF6(ADC6/TDO)
56  PF5(ADC5/TMS)
57  PF4(ADC4/TCK)
58  PF3(ADC3)
59  PF2(ADC2)
60  PF1(ADC1)
61  PF0(ADC0)
62  AREF
63  GND
64  AVCC
65  PAD

## Footprint QFN64G-0.5-9X9MM (pad centres in mm)
smd 1 x 0.25: 1 -4.55,3.75; 2 -4.55,3.25; 3 -4.55,2.75; 4 -4.55,2.25; 5 -4.55,1.75; 6 -4.55,1.25; 7 -4.55,0.75; 8 -4.55,0.25; 9 -4.55,-0.25; 10 -4.55,-0.75; 11 -4.55,-1.25; 12 -4.55,-1.75; 13 -4.55,-2.25; 14 -4.55,-2.75; 15 -4.55,-3.25; 16 -4.55,-3.75; 33 4.55,-3.75; 34 4.55,-3.25; 35 4.55,-2.75; 36 4.55,-2.25; 37 4.55,-1.75; 38 4.55,-1.25; 39 4.55,-0.75; 40 4.55,-0.25; 41 4.55,0.25; 42 4.55,0.75; 43 4.55,1.25; 44 4.55,1.75; 45 4.55,2.25; 46 4.55,2.75; 47 4.55,3.25; 48 4.55,3.75
smd 0.25 x 1: 17 -3.75,-4.55; 18 -3.25,-4.55; 19 -2.75,-4.55; 20 -2.25,-4.55; 21 -1.75,-4.55; 22 -1.25,-4.55; 23 -0.75,-4.55; 24 -0.25,-4.55; 25 0.25,-4.55; 26 0.75,-4.55; 27 1.25,-4.55; 28 1.75,-4.55; 29 2.25,-4.55; 30 2.75,-4.55; 31 3.25,-4.55; 32 3.75,-4.55; 49 3.75,4.55; 50 3.25,4.55; 51 2.75,4.55; 52 2.25,4.55; 53 1.75,4.55; 54 1.25,4.55; 55 0.75,4.55; 56 0.25,4.55; 57 -0.25,4.55; 58 -0.75,4.55; 59 -1.25,4.55; 60 -1.75,4.55; 61 -2.25,4.55; 62 -2.75,4.55; 63 -3.25,4.55; 64 -3.75,4.55
smd 7.25 x 7.25: 65 0,0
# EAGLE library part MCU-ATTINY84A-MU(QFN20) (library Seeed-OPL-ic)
310010131

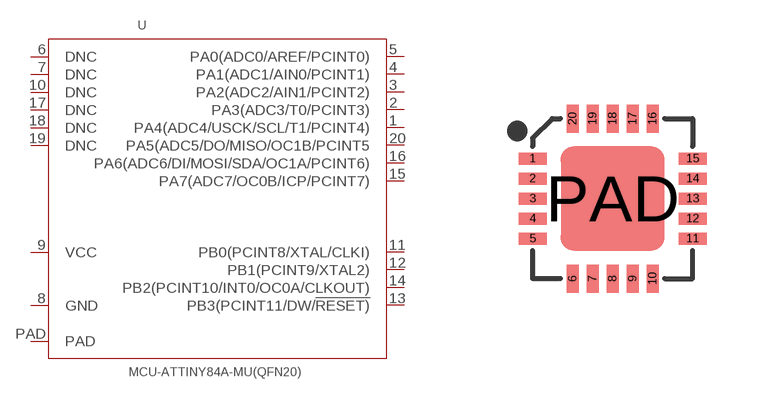
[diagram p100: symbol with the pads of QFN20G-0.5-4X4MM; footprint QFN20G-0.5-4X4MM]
Designator prefix U

## MCU-ATTINY84A-MU(QFN20) (MPN: ATTINY84A-MU; VALUE: ATTINY84A-MU-QFN20)  [QFN20G-0.5-4X4MM]
1  PA4(ADC4/USCK/SCL/T1/PCINT4)  in
2  PA3(ADC3/T0/PCINT3)  in
3  PA2(ADC2/AIN1/PCINT2)  out
4  PA1(ADC1/AIN0/PCINT1)  out
5  PA0(ADC0/AREF/PCINT0)  out
6  DNC  out
7  DNC  in
8  GND  in
9  VCC  sup
10  DNC  in
11  PB0(PCINT8/XTAL/CLKI)  out
12  PB1(PCINT9/XTAL2)  in
13  PB3(PCINT11/DW/!RESET)  out
14  PB2(PCINT10/INT0/OC0A/CLKOUT)  in
15  PA7(ADC7/OC0B/ICP/PCINT7)  in
16  PA6(ADC6/DI/MOSI/SDA/OC1A/PCINT6)  in
17  DNC  in
18  DNC  in
19  DNC  out
20  PA5(ADC5/DO/MISO/OC1B/PCINT5  out
PAD  PAD  in

## Footprint QFN20G-0.5-4X4MM (pad centres in mm)
smd 0.7 x 0.3: 1 -2,1; 2 -2,0.5; 3 -2,0; 4 -2,-0.5; 5 -2,-1; 11 2,-1; 12 2,-0.5; 13 2,0; 14 2,0.5; 15 2,1
smd 0.3 x 0.7: 6 -1,-2; 7 -0.5,-2; 8 0,-2; 9 0.5,-2; 10 1,-2; 16 1,2; 17 0.5,2; 18 0,2; 19 -0.5,2; 20 -1,2
smd 2.6 x 2.6: PAD 0,0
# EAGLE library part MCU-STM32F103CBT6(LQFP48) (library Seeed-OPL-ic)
310010004

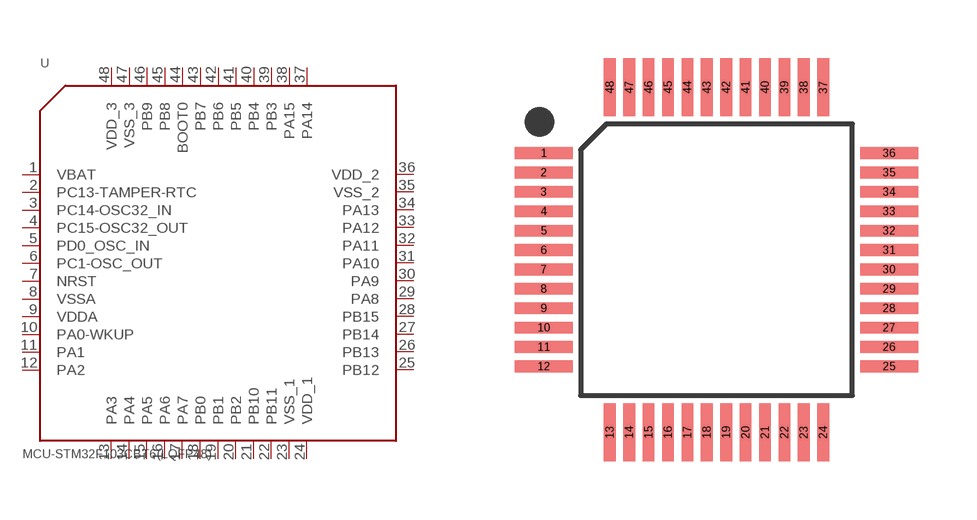
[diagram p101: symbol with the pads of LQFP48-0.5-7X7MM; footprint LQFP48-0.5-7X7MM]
Designator prefix U

## MCU-STM32F103CBT6(LQFP48) (MPN: STM32F103CBT6; VALUE: STM32F103CBT6-LQFP48)  [LQFP48-0.5-7X7MM]
1  VBAT
2  PC13-TAMPER-RTC
3  PC14-OSC32_IN
4  PC15-OSC32_OUT
5  PD0_OSC_IN
6  PC1-OSC_OUT
7  NRST
8  VSSA
9  VDDA
10  PA0-WKUP
11  PA1
12  PA2
13  PA3
14  PA4
15  PA5
16  PA6
17  PA7
18  PB0
19  PB1
20  PB2
21  PB10
22  PB11
23  VSS_1
24  VDD_1
25  PB12
26  PB13
27  PB14
28  PB15
29  PA8
30  PA9
31  PA10
32  PA11
33  PA12
34  PA13
35  VSS_2
36  VDD_2
37  PA14
38  PA15
39  PB3
40  PB4
41  PB5
42  PB6
43  PB7
44  BOOT0
45  PB8
46  PB9
47  VSS_3
48  VDD_3

## Footprint LQFP48-0.5-7X7MM (pad centres in mm)
smd 1.5 x 0.3: 1 -4.45,2.75; 2 -4.45,2.25; 3 -4.45,1.75; 4 -4.45,1.25; 5 -4.45,0.75; 6 -4.45,0.25; 7 -4.45,-0.25; 8 -4.45,-0.75; 9 -4.45,-1.25; 10 -4.45,-1.75; 11 -4.45,-2.25; 12 -4.45,-2.75; 25 4.45,-2.75; 26 4.45,-2.25; 27 4.45,-1.75; 28 4.45,-1.25; 29 4.45,-0.75; 30 4.45,-0.25; 31 4.45,0.25; 32 4.45,0.75; 33 4.45,1.25; 34 4.45,1.75; 35 4.45,2.25; 36 4.45,2.75
smd 0.3 x 1.5: 13 -2.75,-4.45; 14 -2.25,-4.45; 15 -1.75,-4.45; 16 -1.25,-4.45; 17 -0.75,-4.45; 18 -0.25,-4.45; 19 0.25,-4.45; 20 0.75,-4.45; 21 1.25,-4.45; 22 1.75,-4.45; 23 2.25,-4.45; 24 2.75,-4.45; 37 2.75,4.45; 38 2.25,4.45; 39 1.75,4.45; 40 1.25,4.45; 41 0.75,4.45; 42 0.25,4.45; 43 -0.25,4.45; 44 -0.75,4.45; 45 -1.25,4.45; 46 -1.75,4.45; 47 -2.25,4.45; 48 -2.75,4.45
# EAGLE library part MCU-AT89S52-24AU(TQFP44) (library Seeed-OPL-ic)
310010009

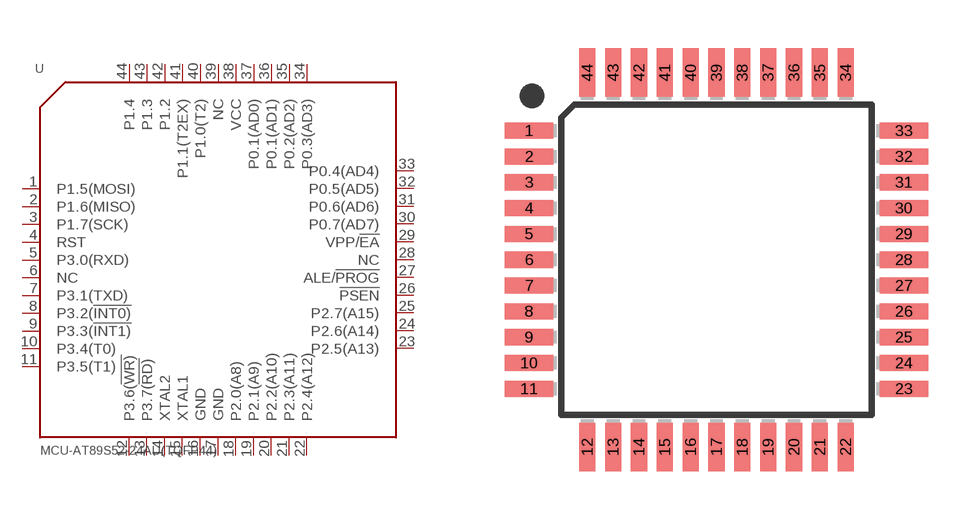
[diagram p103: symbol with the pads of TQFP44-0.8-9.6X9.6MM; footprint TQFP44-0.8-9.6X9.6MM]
Designator prefix U

## MCU-AT89S52-24AU(TQFP44) (MPN: AT89S52-24AU; VALUE: AT89S52-24AU-TQFP44)  [TQFP44-0.8-9.6X9.6MM]
1  P1.5(MOSI)
2  P1.6(MISO)
3  P1.7(SCK)
4  RST
5  P3.0(RXD)
6  NC
7  P3.1(TXD)
8  P3.2(!INT0)
9  P3.3(!INT1)
10  P3.4(T0)
11  P3.5(T1)
12  P3.6(!WR)
13  P3.7(!RD)
14  XTAL2
15  XTAL1
16  GND
17  GND
18  P2.0(A8)
19  P2.1(A9)
20  P2.2(A10)
21  P2.3(A11)
22  P2.4(A12)
23  P2.5(A13)
24  P2.6(A14)
25  P2.7(A15)
26  !PSEN
27  ALE/!PROG
28  NC
29  VPP/!EA
30  P0.7(AD7)
31  P0.6(AD6)
32  P0.5(AD5)
33  P0.4(AD4)
34  P0.3(AD3)
35  P0.2(AD2)
36  P0.1(AD1)
37  P0.1(AD0)
38  VCC
39  NC
40  P1.0(T2)
41  P1.1(T2EX)
42  P1.2
43  P1.3
44  P1.4

## Footprint TQFP44-0.8-9.6X9.6MM (pad centres in mm)
Thin Plasic Quad Flat Package
smd 1.5 x 0.5: 1 -5.8,4; 2 -5.8,3.2; 3 -5.8,2.4; 4 -5.8,1.6; 5 -5.8,0.8; 6 -5.8,0; 7 -5.8,-0.8; 8 -5.8,-1.6; 9 -5.8,-2.4; 10 -5.8,-3.2; 11 -5.8,-4; 23 5.8,-4; 24 5.8,-3.2; 25 5.8,-2.4; 26 5.8,-1.6; 27 5.8,-0.8; 28 5.8,0; 29 5.8,0.8; 30 5.8,1.6; 31 5.8,2.4; 32 5.8,3.2; 33 5.8,4
smd 0.5 x 1.5: 12 -4,-5.8; 13 -3.2,-5.8; 14 -2.4,-5.8; 15 -1.6,-5.8; 16 -0.8,-5.8; 17 0,-5.8; 18 0.8,-5.8; 19 1.6,-5.8; 20 2.4,-5.8; 21 3.2,-5.8; 22 4,-5.8; 34 4,5.8; 35 3.2,5.8; 36 2.4,5.8; 37 1.6,5.8; 38 0.8,5.8; 39 0,5.8; 40 -0.8,5.8; 41 -1.6,5.8; 42 -2.4,5.8; 43 -3.2,5.8; 44 -4,5.8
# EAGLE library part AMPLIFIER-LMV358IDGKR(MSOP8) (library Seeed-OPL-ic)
310020007

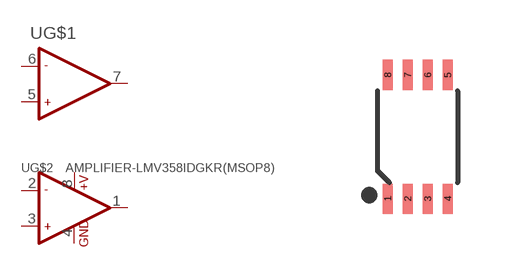
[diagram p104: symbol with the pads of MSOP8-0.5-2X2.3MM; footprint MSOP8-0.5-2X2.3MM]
Designator prefix U; gates G$1=OPAMP_2_1 G$2=OPAMP_2

## AMPLIFIER-LMV358IDGKR(MSOP8) (MPN: LMV358IDGKR; VALUE: LMV358IDGKR-MSOP8)  [MSOP8-0.5-2X2.3MM]
1  G$2:OUT1  out
2  G$2:-IN1  in
3  G$2:+IN1  in
4  G$2:GND  pwr
5  G$1:+IN2  in
6  G$1:-IN2  in
7  G$1:OUT2  out
8  G$2:+V  pwr

## Footprint MSOP8-0.5-2X2.3MM (pad centres in mm)
smd 0.25 x 0.75: 1 -0.75,-1.55; 2 -0.25,-1.55; 3 0.25,-1.55; 4 0.75,-1.55; 5 0.75,1.55; 6 0.25,1.55; 7 -0.25,1.55; 8 -0.75,1.55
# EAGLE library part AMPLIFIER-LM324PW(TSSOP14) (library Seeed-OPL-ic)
310020008

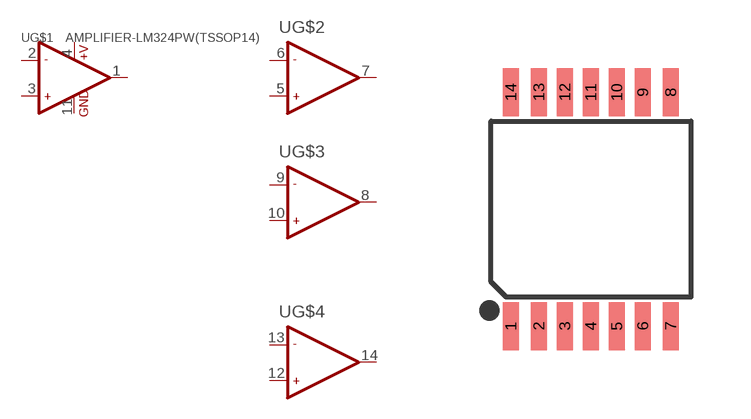
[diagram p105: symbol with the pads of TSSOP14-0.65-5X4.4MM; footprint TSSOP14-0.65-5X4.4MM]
Designator prefix U; gates G$1=OPAMP_2 G$2=OPAMP_2_1 G$3=OPAMP_2_1 G$4=OPAMP_2_1

## AMPLIFIER-LM324PW(TSSOP14) (MPN: LM324PW; VALUE: LM324PW-TSSOP14)  [TSSOP14-0.65-5X4.4MM]
1  G$1:OUT1  out
2  G$1:-IN1  in
3  G$1:+IN1  in
4  G$1:+V  pwr
5  G$2:+IN2  in
6  G$2:-IN2  in
7  G$2:OUT2  out
8  G$3:OUT2  out
9  G$3:-IN2  in
10  G$3:+IN2  in
11  G$1:GND  pwr
12  G$4:+IN2  in
13  G$4:-IN2  in
14  G$4:OUT2  out

## Footprint TSSOP14-0.65-5X4.4MM (pad centres in mm)
smd 0.4 x 1.2: 1 -2,-2.925; 2 -1.3,-2.925; 3 -0.65,-2.925; 4 0,-2.925; 5 0.65,-2.925; 6 1.3,-2.925; 7 2,-2.925; 8 2,2.925; 9 1.3,2.925; 10 0.65,2.925; 11 0,2.925; 12 -0.65,2.925; 13 -1.3,2.925; 14 -2,2.925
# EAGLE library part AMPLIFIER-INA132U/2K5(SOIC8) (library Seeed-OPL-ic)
310020010

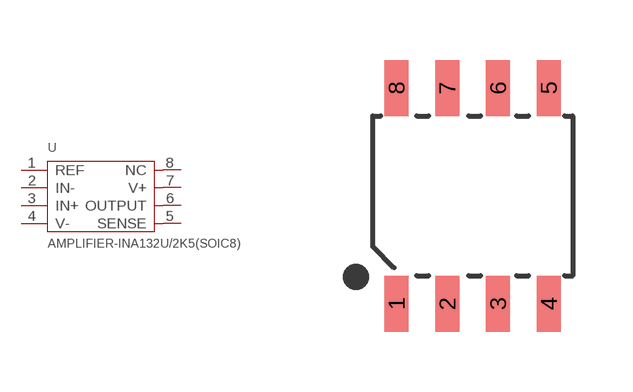
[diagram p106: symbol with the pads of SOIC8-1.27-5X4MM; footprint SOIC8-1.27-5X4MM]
Designator prefix U

## AMPLIFIER-INA132U/2K5(SOIC8) (MPN: INA132U/2K5; VALUE: INA132U/2K5-SOIC8)  [SOIC8-1.27-5X4MM]
1  REF
2  IN-  in
3  IN+  in
4  V-  pwr
5  SENSE
6  OUTPUT  out
7  V+  pwr
8  NC  sup

## Footprint SOIC8-1.27-5X4MM (pad centres in mm)
smd 0.6 x 1.4: 1 -1.905,-2.7; 2 -0.635,-2.7; 3 0.635,-2.7; 4 1.905,-2.7; 5 1.905,2.7; 6 0.635,2.7; 7 -0.635,2.7; 8 -1.905,2.7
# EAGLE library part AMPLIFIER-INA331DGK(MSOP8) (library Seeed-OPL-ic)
310020014

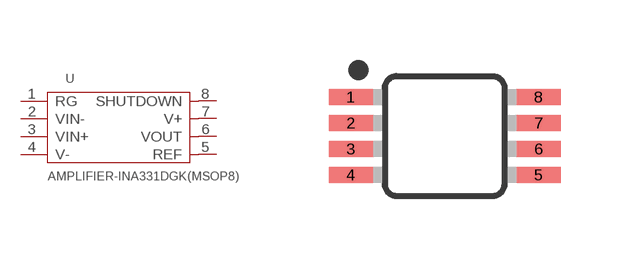
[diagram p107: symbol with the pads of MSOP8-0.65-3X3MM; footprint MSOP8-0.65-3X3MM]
Designator prefix U

## AMPLIFIER-INA331DGK(MSOP8) (MPN: INA331IDGK; VALUE: INA331IDGK-MSOP8)  [MSOP8-0.65-3X3MM]
1  RG  out
2  VIN-  in
3  VIN+  in
4  V-  sup
5  REF  in
6  VOUT  in
7  V+  out
8  SHUTDOWN  sup

## Footprint MSOP8-0.65-3X3MM (pad centres in mm)
8M, 8-Lead, 0.118" Wide, Miniature Small Outline Package MSOP 8M-Package doc1097.pdf
smd 1.1 x 0.4: 1 -2.35,0.975; 2 -2.35,0.325; 3 -2.35,-0.325; 4 -2.35,-0.975; 5 2.35,-0.975; 6 2.35,-0.325; 7 2.35,0.325; 8 2.35,0.975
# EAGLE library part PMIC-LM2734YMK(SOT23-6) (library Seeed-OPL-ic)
310030023

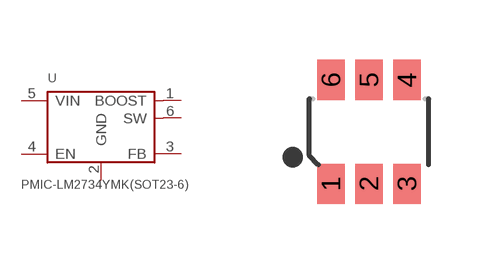
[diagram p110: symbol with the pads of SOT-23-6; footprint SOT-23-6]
Designator prefix U

## PMIC-LM2734YMK(SOT23-6) (MPN: LM2734YMK; VALUE: LM2734YMK-SOT23-6)  [SOT-23-6]
1  BOOST  out
2  GND  pwr
3  FB  in
4  EN  in
5  VIN  in
6  SW  in

## Footprint SOT-23-6 (pad centres in mm)
smd 0.69 x 1: 1 -0.95,-1.3; 2 0,-1.3; 3 0.95,-1.3; 4 0.95,1.3; 5 0,1.3; 6 -0.95,1.3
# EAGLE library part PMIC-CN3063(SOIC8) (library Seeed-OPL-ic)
310030060

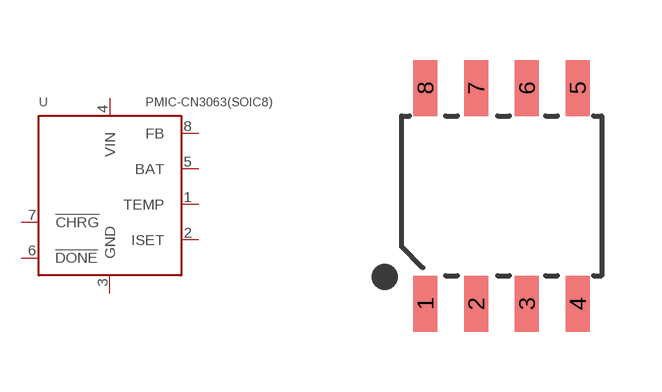
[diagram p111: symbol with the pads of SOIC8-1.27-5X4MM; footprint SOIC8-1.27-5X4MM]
Designator prefix U

## PMIC-CN3063(SOIC8) (MPN: CN3063; VALUE: CN3063-SOIC8)  [SOIC8-1.27-5X4MM]
1  TEMP
2  ISET
3  GND  sup
4  VIN  in
5  BAT  pwr
6  !DONE  in
7  !CHRG  out
8  FB  in

## Footprint SOIC8-1.27-5X4MM (pad centres in mm)
smd 0.6 x 1.4: 1 -1.905,-2.7; 2 -0.635,-2.7; 3 0.635,-2.7; 4 1.905,-2.7; 5 1.905,2.7; 6 0.635,2.7; 7 -0.635,2.7; 8 -1.905,2.7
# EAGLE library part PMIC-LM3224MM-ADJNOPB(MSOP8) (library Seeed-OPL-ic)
310030062

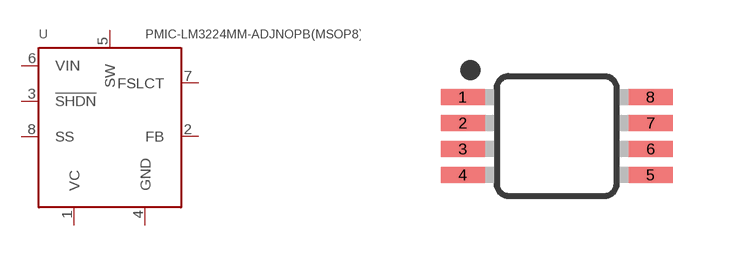
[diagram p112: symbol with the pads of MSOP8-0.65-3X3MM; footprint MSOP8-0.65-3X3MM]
Designator prefix U

## PMIC-LM3224MM-ADJNOPB(MSOP8) (MPN: LM3224MM-ADJNOPB; VALUE: LM3224MM-ADJNOPB-MSOP8)  [MSOP8-0.65-3X3MM]
1  VC
2  FB  in
3  !SHDN
4  GND  sup
5  SW
6  VIN  in
7  FSLCT
8  SS

## Footprint MSOP8-0.65-3X3MM (pad centres in mm)
8M, 8-Lead, 0.118" Wide, Miniature Small Outline Package MSOP 8M-Package doc1097.pdf
smd 1.1 x 0.4: 1 -2.35,0.975; 2 -2.35,0.325; 3 -2.35,-0.325; 4 -2.35,-0.975; 5 2.35,-0.975; 6 2.35,-0.325; 7 2.35,0.325; 8 2.35,0.975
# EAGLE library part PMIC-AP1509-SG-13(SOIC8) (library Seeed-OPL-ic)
310030075

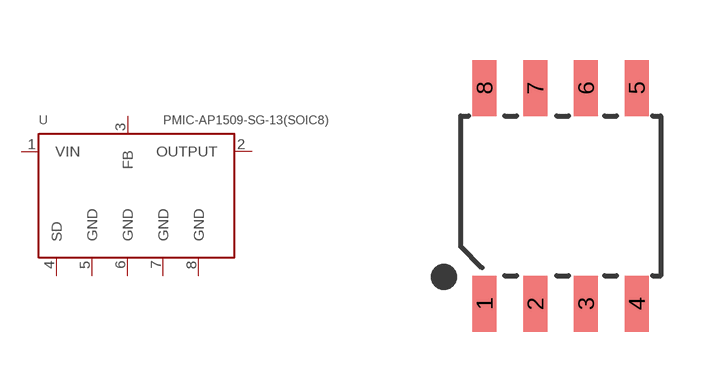
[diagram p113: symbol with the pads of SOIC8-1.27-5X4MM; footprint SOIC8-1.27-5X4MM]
Designator prefix U

## PMIC-AP1509-SG-13(SOIC8) (MPN: AP1509-SG-13; VALUE: AP1509-SG-13-SOIC8)  [SOIC8-1.27-5X4MM]
1  VIN  in
2  OUTPUT  out
3  FB
4  SD
5  GND  pwr
6  GND  pwr
7  GND  pwr
8  GND  pwr

## Footprint SOIC8-1.27-5X4MM (pad centres in mm)
smd 0.6 x 1.4: 1 -1.905,-2.7; 2 -0.635,-2.7; 3 0.635,-2.7; 4 1.905,-2.7; 5 1.905,2.7; 6 0.635,2.7; 7 -0.635,2.7; 8 -1.905,2.7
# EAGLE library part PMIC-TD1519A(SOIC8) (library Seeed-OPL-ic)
310030141

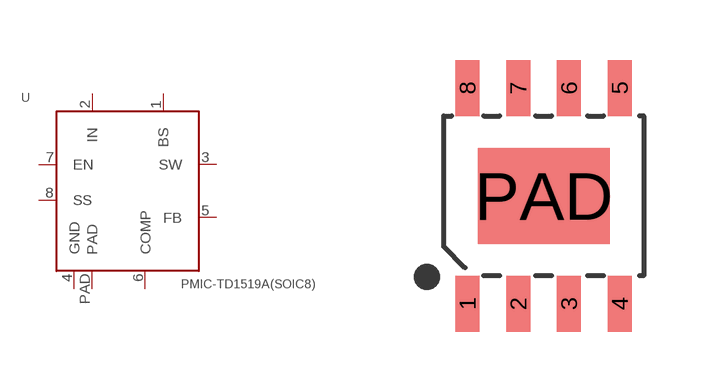
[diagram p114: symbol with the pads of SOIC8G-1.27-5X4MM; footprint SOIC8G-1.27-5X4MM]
Designator prefix U

## PMIC-TD1519A(SOIC8) (MPN: TD1519A; VALUE: TD1519A-soic8)  [SOIC8G-1.27-5X4MM]
1  BS
2  IN  in
3  SW
4  GND  sup
5  FB  in
6  COMP
7  EN
8  SS
PAD  PAD  sup

## Footprint SOIC8G-1.27-5X4MM (pad centres in mm)
smd 0.6 x 1.4: 1 -1.905,-2.7; 2 -0.635,-2.7; 3 0.635,-2.7; 4 1.905,-2.7; 5 1.905,2.7; 6 0.635,2.7; 7 -0.635,2.7; 8 -1.905,2.7
smd 3.3 x 2.4: PAD 0,0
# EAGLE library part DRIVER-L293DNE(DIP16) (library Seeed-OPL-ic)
310040017

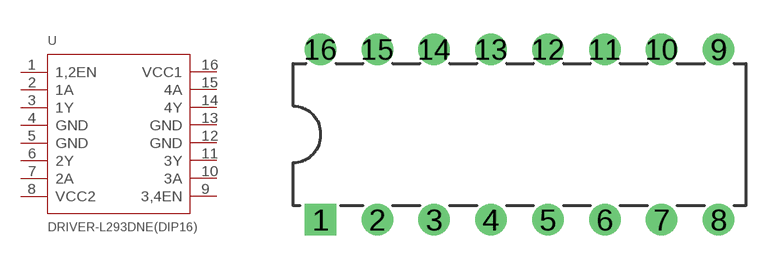
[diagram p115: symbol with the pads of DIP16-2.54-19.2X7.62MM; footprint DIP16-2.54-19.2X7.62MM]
Designator prefix U

## DRIVER-L293DNE(DIP16) (MPN: L293DNE; VALUE: L293DNE-dip16)  [DIP16-2.54-19.2X7.62MM]
1  1,2EN
2  1A
3  1Y
4  GND
5  GND
6  2Y
7  2A
8  VCC2
9  3,4EN
10  3A
11  3Y
12  GND
13  GND
14  4Y
15  4A
16  VCC1

## Footprint DIP16-2.54-19.2X7.62MM (pad centres in mm)
drill 0.9 pad 1.4 square: 1 -8.89,-3.81
drill 0.9 pad 1.4: 2 -6.35,-3.81; 3 -3.81,-3.81; 4 -1.27,-3.81; 5 1.27,-3.81; 6 3.81,-3.81; 7 6.35,-3.81; 8 8.89,-3.81; 9 8.89,3.81; 10 6.35,3.81; 11 3.81,3.81; 12 1.27,3.81; 13 -1.27,3.81; 14 -3.81,3.81; 15 -6.35,3.81; 16 -8.89,3.81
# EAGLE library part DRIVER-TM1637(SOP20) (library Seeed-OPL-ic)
310040027

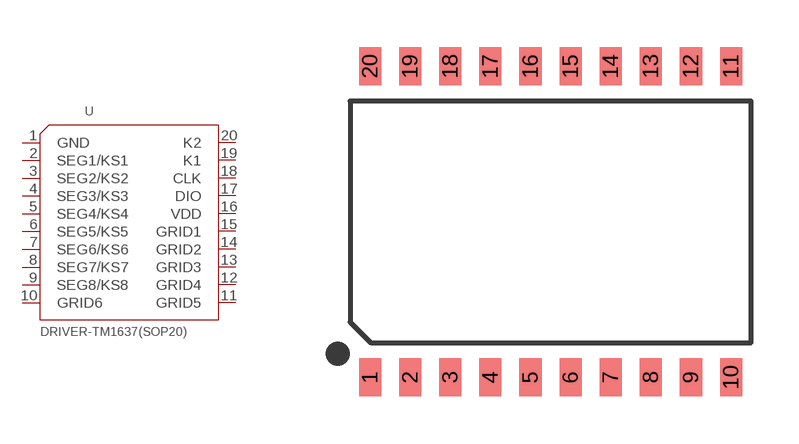
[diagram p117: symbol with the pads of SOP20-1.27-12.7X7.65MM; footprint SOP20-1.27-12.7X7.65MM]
Designator prefix U

## DRIVER-TM1637(SOP20) (MPN: TM1637; VALUE: TM1637-sop20)  [SOP20-1.27-12.7X7.65MM]
1  GND
2  SEG1/KS1
3  SEG2/KS2
4  SEG3/KS3
5  SEG4/KS4
6  SEG5/KS5
7  SEG6/KS6
8  SEG7/KS7
9  SEG8/KS8
10  GRID6
11  GRID5
12  GRID4
13  GRID3
14  GRID2
15  GRID1
16  VDD
17  DIO
18  CLK
19  K1
20  K2

## Footprint SOP20-1.27-12.7X7.65MM (pad centres in mm)
smd 0.7 x 1.2: 1 -5.715,-4.925; 2 -4.445,-4.925; 3 -3.175,-4.925; 4 -1.905,-4.925; 5 -0.635,-4.925; 6 0.635,-4.925; 7 1.905,-4.925; 8 3.175,-4.925; 9 4.445,-4.925; 10 5.715,-4.925; 11 5.715,4.925; 12 4.445,4.925; 13 3.175,4.925; 14 1.905,4.925; 15 0.635,4.925; 16 -0.635,4.925; 17 -1.905,4.925; 18 -3.175,4.925; 19 -4.445,4.925; 20 -5.715,4.925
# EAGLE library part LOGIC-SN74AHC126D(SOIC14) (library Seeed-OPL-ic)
310050013

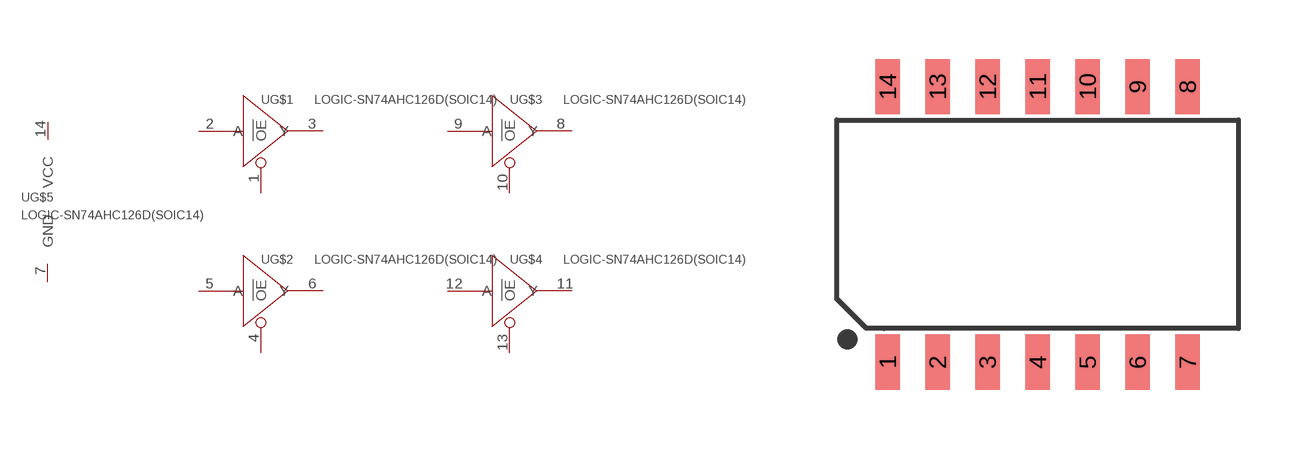
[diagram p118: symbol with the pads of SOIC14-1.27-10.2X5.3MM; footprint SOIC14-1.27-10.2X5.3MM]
Designator prefix U; gates G$1=BUFFER G$2=BUFFER G$3=BUFFER G$4=BUFFER G$5=VCC-GND

## LOGIC-SN74AHC126D(SOIC14) (MPN: SN74AHC126D; VALUE: SN74AHC126D-soic14)  [SOIC14-1.27-10.2X5.3MM]
1  G$1:!OE
2  G$1:A
3  G$1:Y
4  G$2:!OE
5  G$2:A
6  G$2:Y
7  G$5:GND  sup
8  G$3:Y
9  G$3:A
10  G$3:!OE
11  G$4:Y
12  G$4:A
13  G$4:!OE
14  G$5:VCC  sup

## Footprint SOIC14-1.27-10.2X5.3MM (pad centres in mm)
smd 0.62 x 1.4: 1 -3.81,-3.5; 2 -2.54,-3.5; 3 -1.27,-3.5; 4 0,-3.5; 5 1.27,-3.5; 6 2.54,-3.5; 7 3.81,-3.5; 8 3.81,3.5; 9 2.54,3.5; 10 1.27,3.5; 11 0,3.5; 12 -1.27,3.5; 13 -2.54,3.5; 14 -3.81,3.5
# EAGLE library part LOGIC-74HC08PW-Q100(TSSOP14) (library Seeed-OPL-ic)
310050060

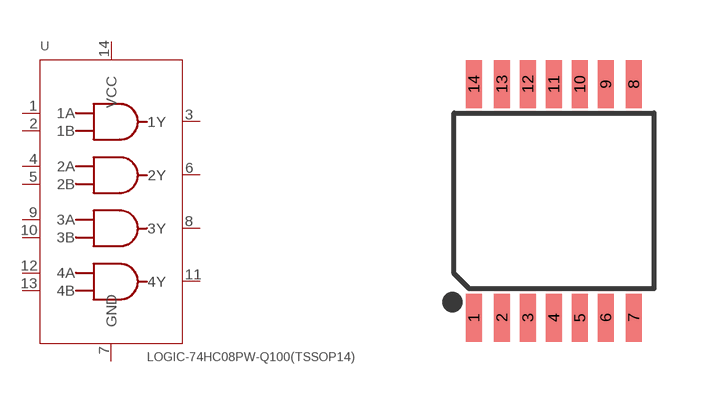
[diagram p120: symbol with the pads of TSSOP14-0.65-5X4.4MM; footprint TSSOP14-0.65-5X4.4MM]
Designator prefix U

## LOGIC-74HC08PW-Q100(TSSOP14) (MPN: 74HC08PW-Q100; VALUE: 74HC08PW-Q100-tssop14)  [TSSOP14-0.65-5X4.4MM]
1  1A
2  1B
3  1Y  sup
4  2A
5  2B
6  2Y  sup
7  GND  sup
8  3Y
9  3A
10  3B
11  4Y  in
12  4A
13  4B
14  VCC  pwr

## Footprint TSSOP14-0.65-5X4.4MM (pad centres in mm)
smd 0.4 x 1.2: 1 -2,-2.925; 2 -1.3,-2.925; 3 -0.65,-2.925; 4 0,-2.925; 5 0.65,-2.925; 6 1.3,-2.925; 7 2,-2.925; 8 2,2.925; 9 1.3,2.925; 10 0.65,2.925; 11 0,2.925; 12 -0.65,2.925; 13 -1.3,2.925; 14 -2,2.925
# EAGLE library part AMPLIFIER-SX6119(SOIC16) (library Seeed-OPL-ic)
310060020

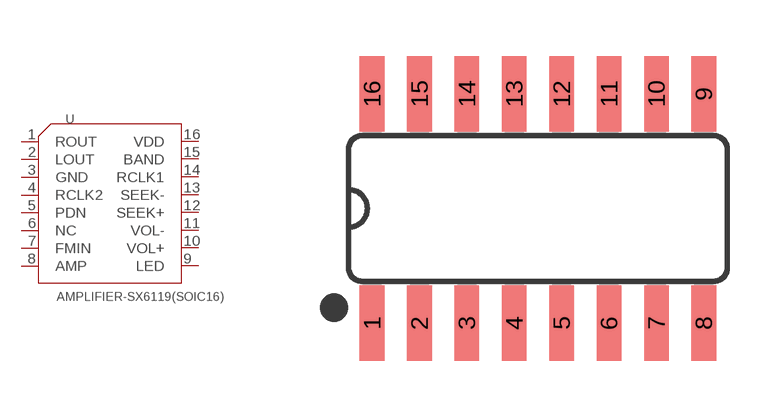
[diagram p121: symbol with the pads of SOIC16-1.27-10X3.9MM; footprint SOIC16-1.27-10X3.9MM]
Designator prefix U

## AMPLIFIER-SX6119(SOIC16) (MPN: SX6119; VALUE: SX6119-soic16)  [SOIC16-1.27-10X3.9MM]
1  ROUT
2  LOUT
3  GND
4  RCLK2
5  PDN
6  NC
7  FMIN
8  AMP
9  LED
10  VOL+
11  VOL-
12  SEEK+
13  SEEK-
14  RCLK1
15  BAND
16  VDD

## Footprint SOIC16-1.27-10X3.9MM (pad centres in mm)
Small Outline package 150 mil
smd 0.66 x 2.032: 1 -4.445,-3.073; 2 -3.175,-3.073; 3 -1.905,-3.073; 4 -0.635,-3.073; 5 0.635,-3.073; 6 1.905,-3.073; 7 3.175,-3.073; 8 4.445,-3.073; 9 4.445,3.073; 10 3.175,3.073; 11 1.905,3.073; 12 0.635,3.073; 13 -0.635,3.073; 14 -1.905,3.073; 15 -3.175,3.073; 16 -4.445,3.073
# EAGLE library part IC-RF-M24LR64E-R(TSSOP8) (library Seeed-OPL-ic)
310060022

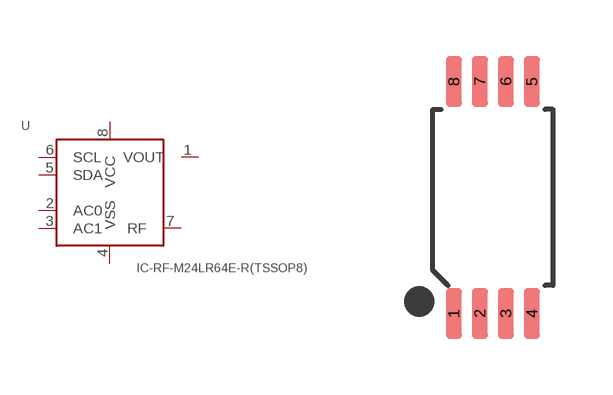
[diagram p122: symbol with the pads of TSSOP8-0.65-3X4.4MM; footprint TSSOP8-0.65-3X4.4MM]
Designator prefix U

## IC-RF-M24LR64E-R(TSSOP8) (MPN: M24LR64E-R; VALUE: M24LR64E-R-tssop8)  [TSSOP8-0.65-3X4.4MM]
1  VOUT
2  AC0
3  AC1
4  VSS
5  SDA
6  SCL
7  RF
8  VCC

## Footprint TSSOP8-0.65-3X4.4MM (pad centres in mm)
smd 0.4 x 1.27: 1 -0.975,-2.9; 2 -0.325,-2.9; 3 0.325,-2.9; 4 0.975,-2.9; 5 0.975,2.9; 6 0.325,2.9; 7 -0.325,2.9; 8 -0.975,2.9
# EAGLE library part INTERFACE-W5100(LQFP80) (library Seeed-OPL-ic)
310070000

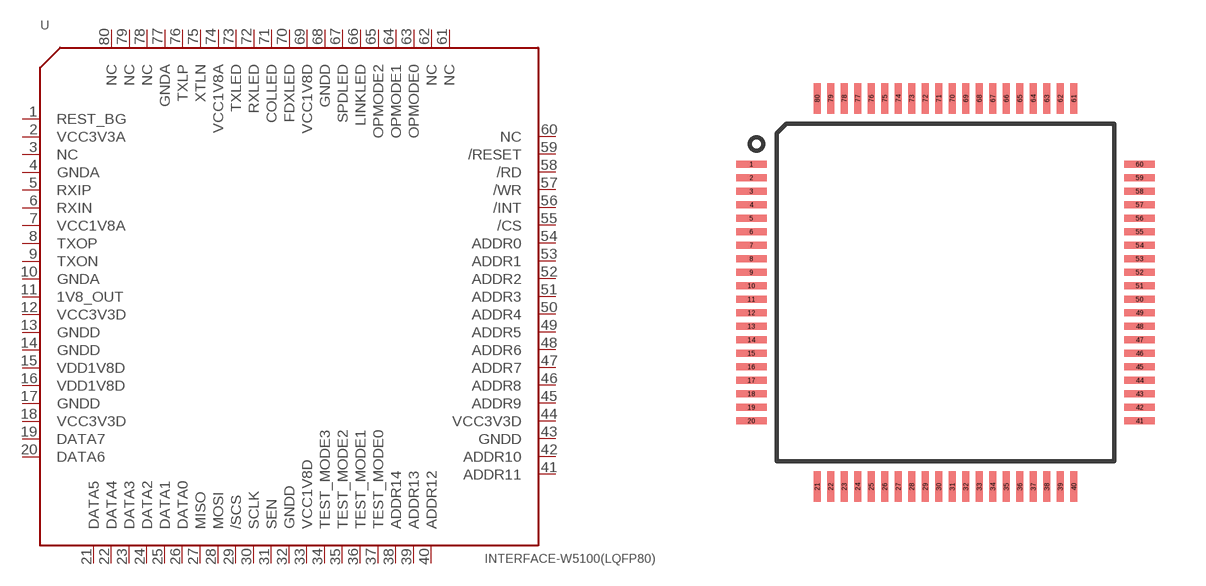
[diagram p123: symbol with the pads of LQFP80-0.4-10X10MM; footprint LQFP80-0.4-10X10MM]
Designator prefix U

## INTERFACE-W5100(LQFP80) (MPN: W5100; VALUE: W5100-LQFP80)  [LQFP80-0.4-10X10MM]
1  REST_BG
2  VCC3V3A  pwr
3  NC  nc
4  GNDA  sup
5  RXIP
6  RXIN
7  VCC1V8A  pwr
8  TXOP
9  TXON
10  GNDA  sup
11  1V8_OUT  pwr
12  VCC3V3D  pwr
13  GNDD  sup
14  GNDD  sup
15  VDD1V8D  pwr
16  VDD1V8D  pwr
17  GNDD  sup
18  VCC3V3D  pwr
19  DATA7
20  DATA6
21  DATA5
22  DATA4
23  DATA3
24  DATA2
25  DATA1
26  DATA0
27  MISO
28  MOSI
29  /SCS
30  SCLK
31  SEN
32  GNDD  sup
33  VCC1V8D  pwr
34  TEST_MODE3
35  TEST_MODE2
36  TEST_MODE1
37  TEST_MODE0
38  ADDR14
39  ADDR13
40  ADDR12
41  ADDR11
42  ADDR10
43  GNDD  sup
44  VCC3V3D  pwr
45  ADDR9
46  ADDR8
47  ADDR7
48  ADDR6
49  ADDR5
50  ADDR4
51  ADDR3
52  ADDR2
53  ADDR1
54  ADDR0
55  /CS
56  /INT
57  /WR
58  /RD
59  /RESET
60  NC  nc
61  NC  nc
62  NC  nc
63  OPMODE0
64  OPMODE1
65  OPMODE2
66  LINKLED
67  SPDLED
68  GNDD  sup
69  VCC1V8D  pwr
70  FDXLED
71  COLLED
72  RXLED
73  TXLED
74  VCC1V8A  pwr
75  XTLN
76  TXLP
77  GNDA  sup
78  NC  nc
79  NC  nc
80  NC  nc

## Footprint LQFP80-0.4-10X10MM (pad centres in mm)
smd 0.9 x 0.2: 1 -5.75,3.8; 2 -5.75,3.4; 3 -5.75,3; 4 -5.75,2.6; 5 -5.75,2.2; 6 -5.75,1.8; 7 -5.75,1.4; 8 -5.75,1; 9 -5.75,0.6; 10 -5.75,0.2; 11 -5.75,-0.2; 12 -5.75,-0.6; 13 -5.75,-1; 14 -5.75,-1.4; 15 -5.75,-1.8; 16 -5.75,-2.2; 17 -5.75,-2.6; 18 -5.75,-3; 19 -5.75,-3.4; 20 -5.75,-3.8; 41 5.75,-3.8; 42 5.75,-3.4; 43 5.75,-3; 44 5.75,-2.6; 45 5.75,-2.2; 46 5.75,-1.8; 47 5.75,-1.4; 48 5.75,-1; 49 5.75,-0.6; 50 5.75,-0.2; 51 5.75,0.2; 52 5.75,0.6; 53 5.75,1; 54 5.75,1.4; 55 5.75,1.8; 56 5.75,2.2; 57 5.75,2.6; 58 5.75,3; 59 5.75,3.4; 60 5.75,3.8
smd 0.2 x 0.9: 21 -3.8,-5.75; 22 -3.4,-5.75; 23 -3,-5.75; 24 -2.6,-5.75; 25 -2.2,-5.75; 26 -1.8,-5.75; 27 -1.4,-5.75; 28 -1,-5.75; 29 -0.6,-5.75; 30 -0.2,-5.75; 31 0.2,-5.75; 32 0.6,-5.75; 33 1,-5.75; 34 1.4,-5.75; 35 1.8,-5.75; 36 2.2,-5.75; 37 2.6,-5.75; 38 3,-5.75; 39 3.4,-5.75; 40 3.8,-5.75; 61 3.8,5.75; 62 3.4,5.75; 63 3,5.75; 64 2.6,5.75; 65 2.2,5.75; 66 1.8,5.75; 67 1.4,5.75; 68 1,5.75; 69 0.6,5.75; 70 0.2,5.75; 71 -0.2,5.75; 72 -0.6,5.75; 73 -1,5.75; 74 -1.4,5.75; 75 -1.8,5.75; 76 -2.2,5.75; 77 -2.6,5.75; 78 -3,5.75; 79 -3.4,5.75; 80 -3.8,5.75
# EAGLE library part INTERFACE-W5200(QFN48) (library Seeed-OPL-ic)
310070002

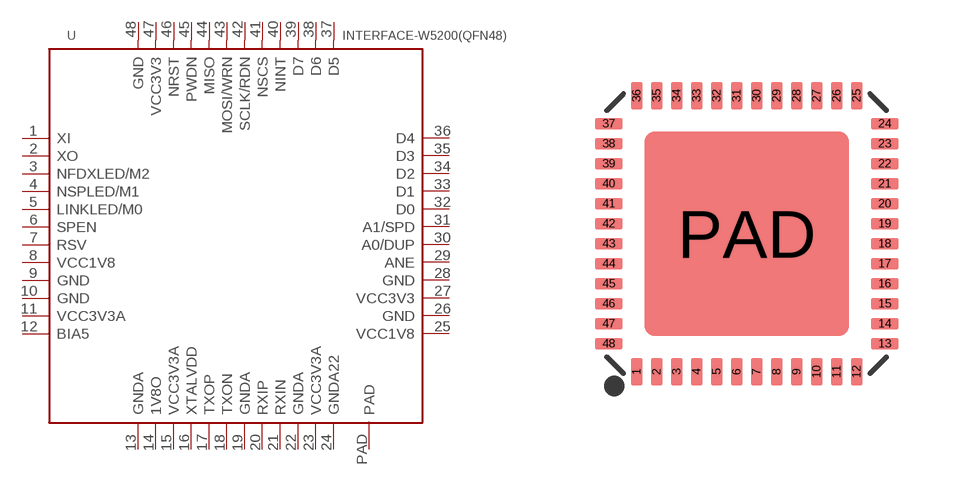
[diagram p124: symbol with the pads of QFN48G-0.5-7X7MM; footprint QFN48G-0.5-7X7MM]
Designator prefix U

## INTERFACE-W5200(QFN48) (MPN: W5200; VALUE: W5200-QFN48)  [QFN48G-0.5-7X7MM]
1  XI
2  XO
3  NFDXLED/M2
4  NSPLED/M1
5  LINKLED/M0
6  SPEN
7  RSV
8  VCC1V8  pwr
9  GND  sup
10  GND  sup
11  VCC3V3A  pwr
12  BIA5
13  GNDA  sup
14  1V8O  pwr
15  VCC3V3A  pwr
16  XTALVDD  pas
17  TXOP  pas
18  TXON  pas
19  GNDA  pas
20  RXIP  pwr
21  RXIN  pas
22  GNDA  sup
23  VCC3V3A  pwr
24  GNDA22  sup
25  VCC1V8  pwr
26  GND  sup
27  VCC3V3  pwr
28  GND  sup
29  ANE  in
30  A0/DUP  in
31  A1/SPD  in
32  D0
33  D1
34  D2
35  D3
36  D4
37  D5
38  D6
39  D7
40  NINT  pas
41  NSCS  pas
42  SCLK/RDN  pas
43  MOSI/WRN  pas
44  MISO  pas
45  PWDN  pas
46  NRST
47  VCC3V3  pwr
48  GND  sup
PAD  PAD  sup

## Footprint QFN48G-0.5-7X7MM (pad centres in mm)
smd 0.3 x 0.7: 1 -2.75,-3.45; 2 -2.25,-3.45; 3 -1.75,-3.45; 4 -1.25,-3.45; 5 -0.75,-3.45; 6 -0.25,-3.45; 7 0.25,-3.45; 8 0.75,-3.45; 9 1.25,-3.45; 10 1.75,-3.45; 11 2.25,-3.45; 12 2.75,-3.45; 25 2.75,3.45; 26 2.25,3.45; 27 1.75,3.45; 28 1.25,3.45; 29 0.75,3.45; 30 0.25,3.45; 31 -0.25,3.45; 32 -0.75,3.45; 33 -1.25,3.45; 34 -1.75,3.45; 35 -2.25,3.45; 36 -2.75,3.45
smd 0.7 x 0.3: 13 3.45,-2.75; 14 3.45,-2.25; 15 3.45,-1.75; 16 3.45,-1.25; 17 3.45,-0.75; 18 3.45,-0.25; 19 3.45,0.25; 20 3.45,0.75; 21 3.45,1.25; 22 3.45,1.75; 23 3.45,2.25; 24 3.45,2.75; 37 -3.45,2.75; 38 -3.45,2.25; 39 -3.45,1.75; 40 -3.45,1.25; 41 -3.45,0.75; 42 -3.45,0.25; 43 -3.45,-0.25; 44 -3.45,-0.75; 45 -3.45,-1.25; 46 -3.45,-1.75; 47 -3.45,-2.25; 48 -3.45,-2.75
smd 5.1 x 5.1: PAD 0,0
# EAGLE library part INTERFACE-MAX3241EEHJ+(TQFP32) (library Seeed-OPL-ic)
310070004

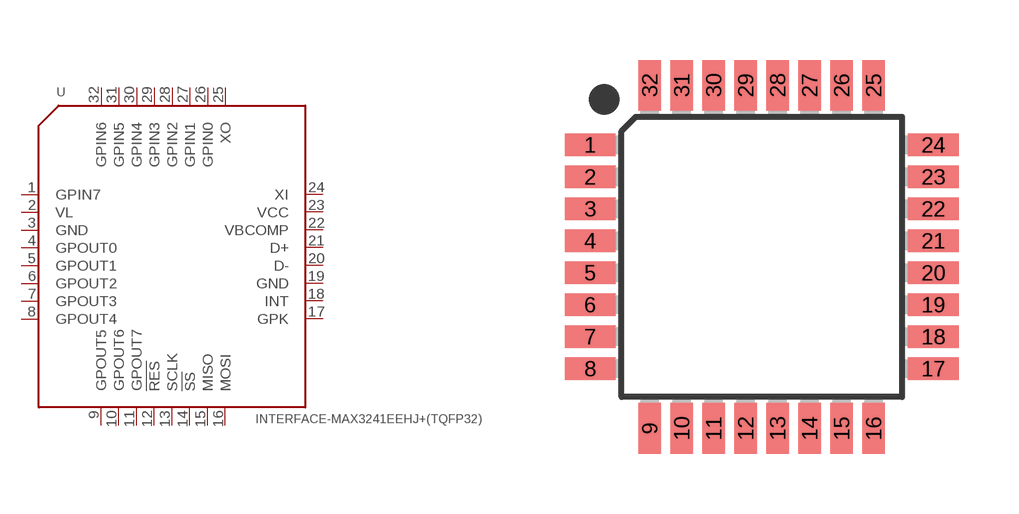
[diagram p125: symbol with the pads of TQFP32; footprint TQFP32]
Designator prefix U

## INTERFACE-MAX3241EEHJ+(TQFP32) (MPN: MAX3421EEHJ+; VALUE: MAX3421EEHJ+-tqfp32)  [TQFP32]
1  GPIN7
2  VL
3  GND
4  GPOUT0
5  GPOUT1
6  GPOUT2
7  GPOUT3
8  GPOUT4
9  GPOUT5
10  GPOUT6
11  GPOUT7
12  !RES
13  SCLK
14  !SS
15  MISO
16  MOSI
17  GPK
18  INT
19  GND
20  D-
21  D+
22  VBCOMP
23  VCC
24  XI
25  XO
26  GPIN0
27  GPIN1
28  GPIN2
29  GPIN3
30  GPIN4
31  GPIN5
32  GPIN6

## Footprint TQFP32 (pad centres in mm)
Thin Plasic Quad Flat Package Grid 0.8 mm
smd 1.27 x 0.559: 1 -4.293,2.8; 2 -4.293,2; 3 -4.293,1.2; 4 -4.293,0.4; 5 -4.293,-0.4; 6 -4.293,-1.2; 7 -4.293,-2; 8 -4.293,-2.8; 17 4.293,-2.8; 18 4.293,-2; 19 4.293,-1.2; 20 4.293,-0.4; 21 4.293,0.4; 22 4.293,1.2; 23 4.293,2; 24 4.293,2.8
smd 0.559 x 1.27: 9 -2.8,-4.293; 10 -2,-4.293; 11 -1.2,-4.293; 12 -0.4,-4.293; 13 0.4,-4.293; 14 1.2,-4.293; 15 2,-4.293; 16 2.8,-4.293; 25 2.8,4.293; 26 2,4.293; 27 1.2,4.293; 28 0.4,4.293; 29 -0.4,4.293; 30 -1.2,4.293; 31 -2,4.293; 32 -2.8,4.293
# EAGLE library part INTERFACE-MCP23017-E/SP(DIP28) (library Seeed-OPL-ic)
310070009

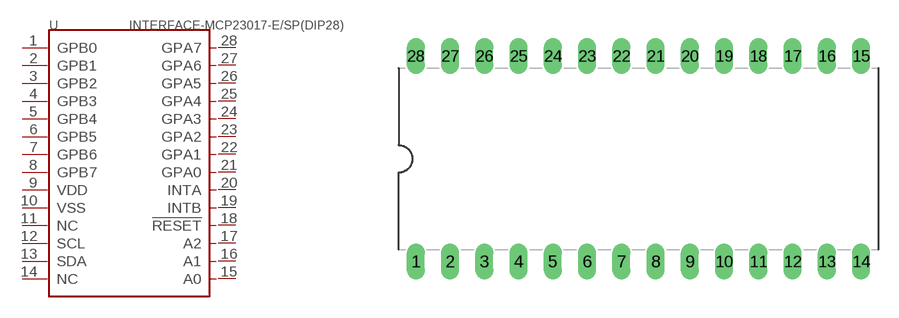
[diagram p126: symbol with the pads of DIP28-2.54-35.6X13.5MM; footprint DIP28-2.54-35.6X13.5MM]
Designator prefix U

## INTERFACE-MCP23017-E/SP(DIP28) (MPN: MCP23017-E/SP; VALUE: MCP23017-E/SP-dip28)  [DIP28-2.54-35.6X13.5MM]
1  GPB0
2  GPB1
3  GPB2
4  GPB3
5  GPB4
6  GPB5
7  GPB6
8  GPB7
9  VDD
10  VSS
11  NC
12  SCL
13  SDA
14  NC
15  A0
16  A1
17  A2
18  !RESET
19  INTB
20  INTA
21  GPA0
22  GPA1
23  GPA2
24  GPA3
25  GPA4
26  GPA5
27  GPA6
28  GPA7

## Footprint DIP28-2.54-35.6X13.5MM (pad centres in mm)
drill 0.813 long: 1 -16.51,-7.62; 2 -13.97,-7.62; 3 -11.43,-7.62; 4 -8.89,-7.62; 5 -6.35,-7.62; 6 -3.81,-7.62; 7 -1.27,-7.62; 8 1.27,-7.62; 9 3.81,-7.62; 10 6.35,-7.62; 11 8.89,-7.62; 12 11.43,-7.62; 13 13.97,-7.62; 14 16.51,-7.62; 15 16.51,7.62; 16 13.97,7.62; 17 11.43,7.62; 18 8.89,7.62; 19 6.35,7.62; 20 3.81,7.62; 21 1.27,7.62; 22 -1.27,7.62; 23 -3.81,7.62; 24 -6.35,7.62; 25 -8.89,7.62; 26 -11.43,7.62; 27 -13.97,7.62; 28 -16.51,7.62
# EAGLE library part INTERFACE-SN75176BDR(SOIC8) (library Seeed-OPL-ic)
310070018

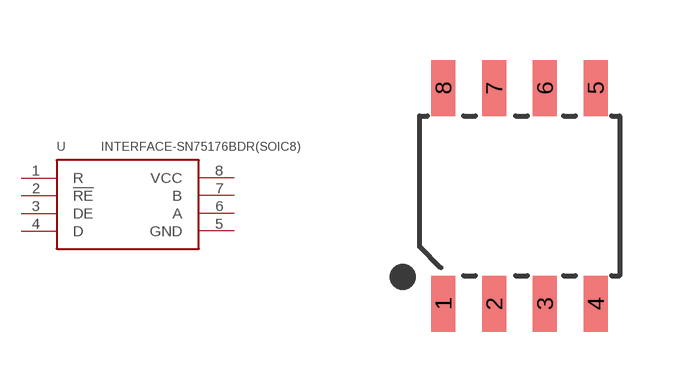
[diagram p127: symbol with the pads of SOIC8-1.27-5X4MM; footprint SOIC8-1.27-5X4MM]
Designator prefix U

## INTERFACE-SN75176BDR(SOIC8) (MPN: SN75176BDR; VALUE: SN75176BDR-soic8)  [SOIC8-1.27-5X4MM]
1  R
2  !RE
3  DE
4  D
5  GND  sup
6  A
7  B
8  VCC  pwr

## Footprint SOIC8-1.27-5X4MM (pad centres in mm)
smd 0.6 x 1.4: 1 -1.905,-2.7; 2 -0.635,-2.7; 3 0.635,-2.7; 4 1.905,-2.7; 5 1.905,2.7; 6 0.635,2.7; 7 -0.635,2.7; 8 -1.905,2.7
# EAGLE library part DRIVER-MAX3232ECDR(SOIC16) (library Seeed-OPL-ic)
310070037

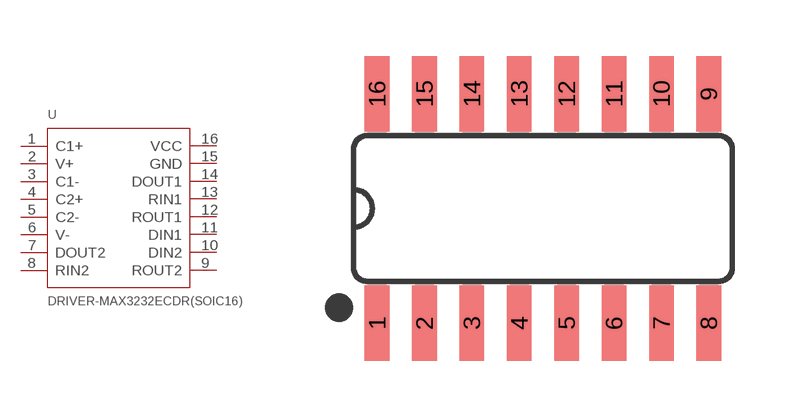
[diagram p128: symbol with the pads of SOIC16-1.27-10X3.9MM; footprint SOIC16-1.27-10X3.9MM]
Designator prefix U

## DRIVER-MAX3232ECDR(SOIC16) (MPN: MAX3232ECDR; VALUE: MAX3232ECDR-soic16)  [SOIC16-1.27-10X3.9MM]
1  C1+
2  V+
3  C1-
4  C2+
5  C2-
6  V-
7  DOUT2
8  RIN2
9  ROUT2
10  DIN2
11  DIN1
12  ROUT1
13  RIN1
14  DOUT1
15  GND  sup
16  VCC  pwr

## Footprint SOIC16-1.27-10X3.9MM (pad centres in mm)
Small Outline package 150 mil
smd 0.66 x 2.032: 1 -4.445,-3.073; 2 -3.175,-3.073; 3 -1.905,-3.073; 4 -0.635,-3.073; 5 0.635,-3.073; 6 1.905,-3.073; 7 3.175,-3.073; 8 4.445,-3.073; 9 4.445,3.073; 10 3.175,3.073; 11 1.905,3.073; 12 0.635,3.073; 13 -0.635,3.073; 14 -1.905,3.073; 15 -3.175,3.073; 16 -4.445,3.073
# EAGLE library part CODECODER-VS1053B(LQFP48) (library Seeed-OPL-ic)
310080002

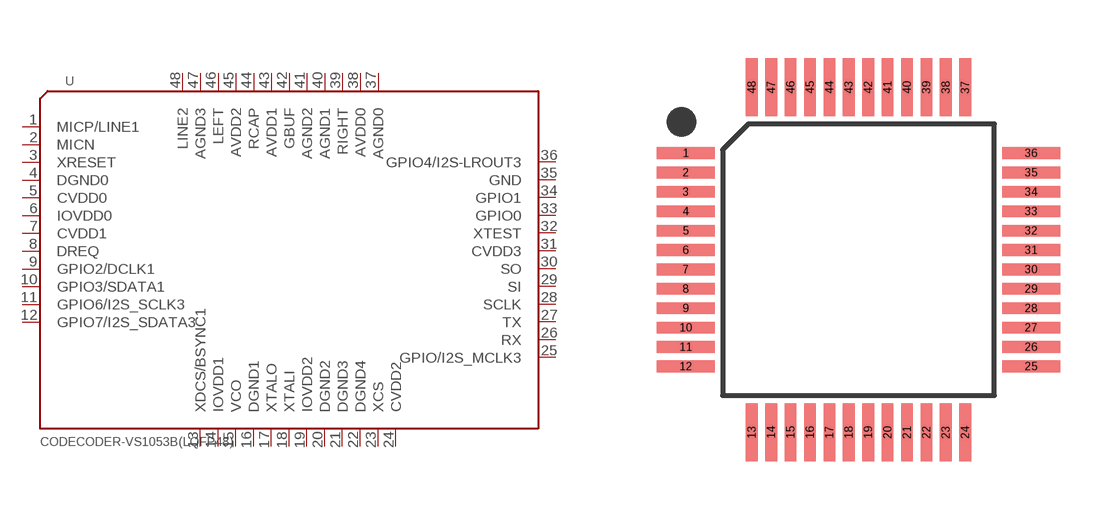
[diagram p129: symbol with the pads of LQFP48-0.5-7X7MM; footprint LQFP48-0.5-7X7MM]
Designator prefix U

## CODECODER-VS1053B(LQFP48) (MPN: VS1053B; VALUE: VS1053B-lqfp48)  [LQFP48-0.5-7X7MM]
1  MICP/LINE1
2  MICN
3  XRESET
4  DGND0  sup
5  CVDD0  pwr
6  IOVDD0  pwr
7  CVDD1  pwr
8  DREQ
9  GPIO2/DCLK1
10  GPIO3/SDATA1
11  GPIO6/I2S_SCLK3
12  GPIO7/I2S_SDATA3
13  XDCS/BSYNC1
14  IOVDD1  pwr
15  VCO  pwr
16  DGND1  sup
17  XTALO
18  XTALI
19  IOVDD2  pwr
20  DGND2  sup
21  DGND3  sup
22  DGND4  sup
23  XCS
24  CVDD2  pwr
25  GPIO/I2S_MCLK3
26  RX
27  TX
28  SCLK
29  SI
30  SO
31  CVDD3  pwr
32  XTEST
33  GPIO0
34  GPIO1
35  GND  sup
36  GPIO4/I2S-LROUT3
37  AGND0  sup
38  AVDD0  sup
39  RIGHT
40  AGND1  sup
41  AGND2  sup
42  GBUF
43  AVDD1  pwr
44  RCAP
45  AVDD2  pwr
46  LEFT
47  AGND3  sup
48  LINE2

## Footprint LQFP48-0.5-7X7MM (pad centres in mm)
smd 1.5 x 0.3: 1 -4.45,2.75; 2 -4.45,2.25; 3 -4.45,1.75; 4 -4.45,1.25; 5 -4.45,0.75; 6 -4.45,0.25; 7 -4.45,-0.25; 8 -4.45,-0.75; 9 -4.45,-1.25; 10 -4.45,-1.75; 11 -4.45,-2.25; 12 -4.45,-2.75; 25 4.45,-2.75; 26 4.45,-2.25; 27 4.45,-1.75; 28 4.45,-1.25; 29 4.45,-0.75; 30 4.45,-0.25; 31 4.45,0.25; 32 4.45,0.75; 33 4.45,1.25; 34 4.45,1.75; 35 4.45,2.25; 36 4.45,2.75
smd 0.3 x 1.5: 13 -2.75,-4.45; 14 -2.25,-4.45; 15 -1.75,-4.45; 16 -1.25,-4.45; 17 -0.75,-4.45; 18 -0.25,-4.45; 19 0.25,-4.45; 20 0.75,-4.45; 21 1.25,-4.45; 22 1.75,-4.45; 23 2.25,-4.45; 24 2.75,-4.45; 37 2.75,4.45; 38 2.25,4.45; 39 1.75,4.45; 40 1.25,4.45; 41 0.75,4.45; 42 0.25,4.45; 43 -0.25,4.45; 44 -0.75,4.45; 45 -1.25,4.45; 46 -1.75,4.45; 47 -2.25,4.45; 48 -2.75,4.45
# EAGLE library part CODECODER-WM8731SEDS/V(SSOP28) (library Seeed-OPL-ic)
310080003

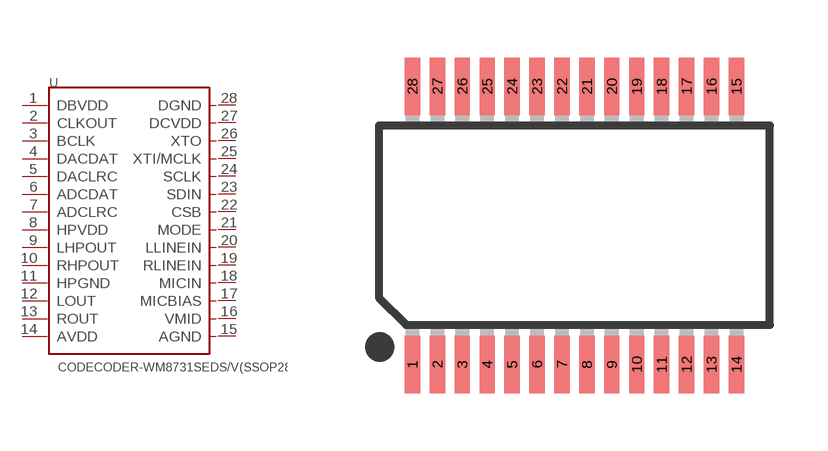
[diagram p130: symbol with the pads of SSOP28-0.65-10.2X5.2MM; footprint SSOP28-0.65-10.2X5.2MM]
Designator prefix U

## CODECODER-WM8731SEDS/V(SSOP28) (MPN: WM8731SEDS/V; VALUE: WM8731SEDS/V-ssop28)  [SSOP28-0.65-10.2X5.2MM]
1  DBVDD  pwr
2  CLKOUT
3  BCLK
4  DACDAT
5  DACLRC
6  ADCDAT
7  ADCLRC
8  HPVDD  pwr
9  LHPOUT
10  RHPOUT
11  HPGND
12  LOUT
13  ROUT
14  AVDD  pwr
15  AGND  sup
16  VMID
17  MICBIAS
18  MICIN
19  RLINEIN
20  LLINEIN
21  MODE
22  CSB
23  SDIN
24  SCLK
25  XTI/MCLK
26  XTO
27  DCVDD  pwr
28  DGND  sup

## Footprint SSOP28-0.65-10.2X5.2MM (pad centres in mm)
Shrink Small Outline Package SSOP-28 http://www.ftdichip.com/Documents/DataSheets/DS_FT232R_v104.pdf
smd 0.4 x 1.5: 1 -4.225,-3.625; 2 -3.575,-3.625; 3 -2.925,-3.625; 4 -2.275,-3.625; 5 -1.625,-3.625; 6 -0.975,-3.625; 7 -0.325,-3.625; 8 0.325,-3.625; 9 0.975,-3.625; 10 1.625,-3.625; 11 2.275,-3.625; 12 2.925,-3.625; 13 3.575,-3.625; 14 4.225,-3.625; 15 4.225,3.625; 16 3.575,3.625; 17 2.925,3.625; 18 2.275,3.625; 19 1.625,3.625; 20 0.975,3.625; 21 0.325,3.625; 22 -0.325,3.625; 23 -0.975,3.625; 24 -1.625,3.625; 25 -2.275,3.625; 26 -2.925,3.625; 27 -3.575,3.625; 28 -4.225,3.625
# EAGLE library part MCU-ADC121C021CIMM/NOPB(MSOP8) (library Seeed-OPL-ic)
310990001

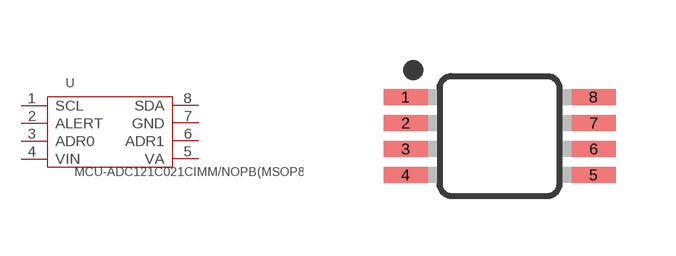
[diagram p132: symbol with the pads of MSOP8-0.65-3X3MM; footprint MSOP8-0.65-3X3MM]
Designator prefix U

## MCU-ADC121C021CIMM/NOPB(MSOP8) (MPN: ADC121C021CIMM/NOPB; VALUE: ADC121C021CIMM/NOPB-msop8)  [MSOP8-0.65-3X3MM]
1  SCL
2  ALERT
3  ADR0
4  VIN  pwr
5  VA
6  ADR1
7  GND  sup
8  SDA

## Footprint MSOP8-0.65-3X3MM (pad centres in mm)
8M, 8-Lead, 0.118" Wide, Miniature Small Outline Package MSOP 8M-Package doc1097.pdf
smd 1.1 x 0.4: 1 -2.35,0.975; 2 -2.35,0.325; 3 -2.35,-0.325; 4 -2.35,-0.975; 5 2.35,-0.975; 6 2.35,-0.325; 7 2.35,0.325; 8 2.35,0.975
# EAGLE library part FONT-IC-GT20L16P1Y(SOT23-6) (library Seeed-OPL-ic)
310990002

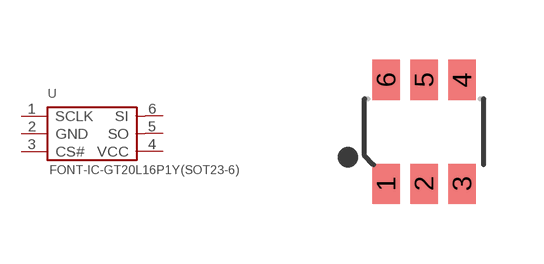
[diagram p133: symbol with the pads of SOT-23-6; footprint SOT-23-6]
Designator prefix U

## FONT-IC-GT20L16P1Y(SOT23-6) (MPN: GT20L16P1Y; VALUE: GT20L16P1Y-sot23-6)  [SOT-23-6]
1  SCLK  in
2  GND  sup
3  CS#  in
4  VCC  pwr
5  SO  in
6  SI  out

## Footprint SOT-23-6 (pad centres in mm)
smd 0.69 x 1: 1 -0.95,-1.3; 2 0,-1.3; 3 0.95,-1.3; 4 0.95,1.3; 5 0,1.3; 6 -0.95,1.3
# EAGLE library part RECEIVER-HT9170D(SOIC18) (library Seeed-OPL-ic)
310990004

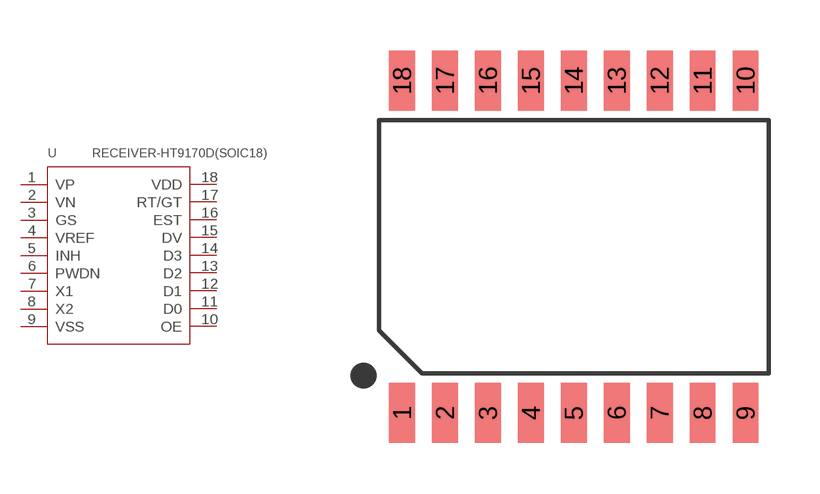
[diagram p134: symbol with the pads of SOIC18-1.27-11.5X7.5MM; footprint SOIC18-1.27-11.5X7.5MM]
Designator prefix U

## RECEIVER-HT9170D(SOIC18) (MPN: HT9170D; VALUE: HT9170D-soic18)  [SOIC18-1.27-11.5X7.5MM]
1  VP
2  VN
3  GS
4  VREF
5  INH
6  PWDN
7  X1
8  X2
9  VSS  sup
10  OE
11  D0
12  D1
13  D2
14  D3
15  DV
16  EST
17  RT/GT
18  VDD  pwr

## Footprint SOIC18-1.27-11.5X7.5MM (pad centres in mm)
smd 0.762 x 1.778: 1 -5.08,-4.915; 2 -3.81,-4.915; 3 -2.54,-4.915; 4 -1.27,-4.915; 5 0,-4.915; 6 1.27,-4.915; 7 2.54,-4.915; 8 3.81,-4.915; 9 5.08,-4.915; 10 5.08,4.915; 11 3.81,4.915; 12 2.54,4.915; 13 1.27,4.915; 14 0,4.915; 15 -1.27,4.915; 16 -2.54,4.915; 17 -3.81,4.915; 18 -5.08,4.915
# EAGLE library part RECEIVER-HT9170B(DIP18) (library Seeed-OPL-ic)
310990006

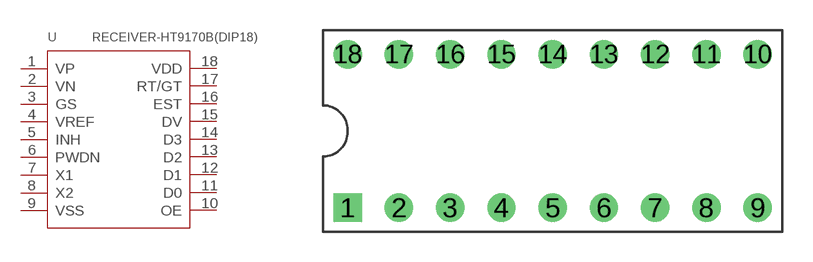
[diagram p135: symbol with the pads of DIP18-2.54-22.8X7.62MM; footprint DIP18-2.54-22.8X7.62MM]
Designator prefix U

## RECEIVER-HT9170B(DIP18) (MPN: HT9170B; VALUE: HT9170B-dip18)  [DIP18-2.54-22.8X7.62MM]
1  VP
2  VN
3  GS
4  VREF
5  INH
6  PWDN
7  X1
8  X2
9  VSS  sup
10  OE
11  D0
12  D1
13  D2
14  D3
15  DV
16  EST
17  RT/GT
18  VDD  pwr

## Footprint DIP18-2.54-22.8X7.62MM (pad centres in mm)
drill 0.9 pad 1.4 square: 1 -10.16,-3.81
drill 0.9 pad 1.4: 2 -7.62,-3.81; 3 -5.08,-3.81; 4 -2.54,-3.81; 5 0,-3.81; 6 2.54,-3.81; 7 5.08,-3.81; 8 7.62,-3.81; 9 10.16,-3.81; 10 10.16,3.81; 11 7.62,3.81; 12 5.08,3.81; 13 2.54,3.81; 14 0,3.81; 15 -2.54,3.81; 16 -5.08,3.81; 17 -7.62,3.81; 18 -10.16,3.81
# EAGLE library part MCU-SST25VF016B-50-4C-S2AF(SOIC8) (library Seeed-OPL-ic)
310090058

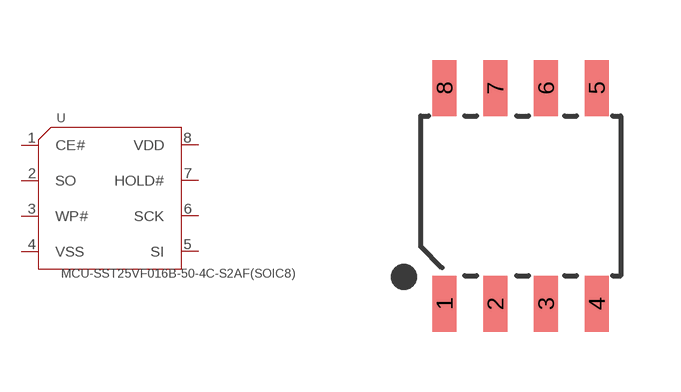
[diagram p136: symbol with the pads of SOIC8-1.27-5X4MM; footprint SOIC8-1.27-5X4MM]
Designator prefix U

## MCU-SST25VF016B-50-4C-S2AF(SOIC8) (MPN: SST25VF016B-50-4C-S2AF; VALUE: SST25VF016B-50-4C-S2AF-soic8)  [SOIC8-1.27-5X4MM]
1  CE#
2  SO
3  WP#
4  VSS  sup
5  SI
6  SCK
7  HOLD#
8  VDD  pwr

## Footprint SOIC8-1.27-5X4MM (pad centres in mm)
smd 0.6 x 1.4: 1 -1.905,-2.7; 2 -0.635,-2.7; 3 0.635,-2.7; 4 1.905,-2.7; 5 1.905,2.7; 6 0.635,2.7; 7 -0.635,2.7; 8 -1.905,2.7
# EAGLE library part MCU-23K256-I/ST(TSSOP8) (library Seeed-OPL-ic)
310090003

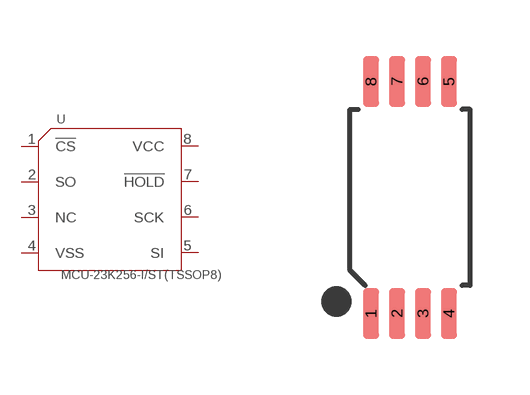
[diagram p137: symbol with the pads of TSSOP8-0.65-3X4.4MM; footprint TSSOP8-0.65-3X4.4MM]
Designator prefix U

## MCU-23K256-I/ST(TSSOP8) (MPN: 23K256-I/ST; VALUE: 23K256-I/ST-tssop8)  [TSSOP8-0.65-3X4.4MM]
1  !CS
2  SO
3  NC
4  VSS  sup
5  SI
6  SCK
7  !HOLD
8  VCC  pwr

## Footprint TSSOP8-0.65-3X4.4MM (pad centres in mm)
smd 0.4 x 1.27: 1 -0.975,-2.9; 2 -0.325,-2.9; 3 0.325,-2.9; 4 0.975,-2.9; 5 0.975,2.9; 6 0.325,2.9; 7 -0.325,2.9; 8 -0.975,2.9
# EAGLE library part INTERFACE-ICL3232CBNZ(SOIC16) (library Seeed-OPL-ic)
310070007

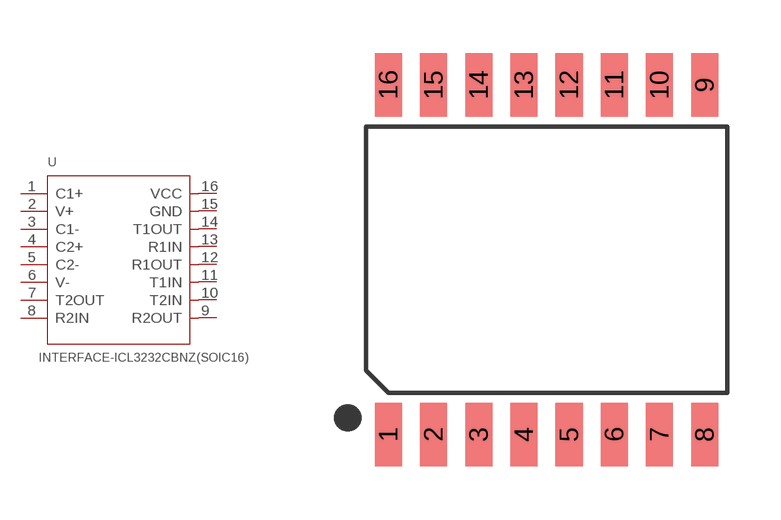
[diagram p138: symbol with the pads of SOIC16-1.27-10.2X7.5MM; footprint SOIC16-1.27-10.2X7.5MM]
Designator prefix U

## INTERFACE-ICL3232CBNZ(SOIC16) (MPN: ICL3232CBNZ; VALUE: ICL3232CBNZ-SOIC16)  [SOIC16-1.27-10.2X7.5MM]
1  C1+  out
2  V+  in
3  C1-  out
4  C2+  in
5  C2-  in
6  V-  in
7  T2OUT  out
8  R2IN  in
9  R2OUT  out
10  T2IN  out
11  T1IN  in
12  R1OUT  in
13  R1IN  out
14  T1OUT  in
15  GND  sup
16  VCC  pwr

## Footprint SOIC16-1.27-10.2X7.5MM (pad centres in mm)
smd 0.762 x 1.778: 1 -4.445,-4.915; 2 -3.175,-4.915; 3 -1.905,-4.915; 4 -0.635,-4.915; 5 0.635,-4.915; 6 1.905,-4.915; 7 3.175,-4.915; 8 4.445,-4.915; 9 4.445,4.915; 10 3.175,4.915; 11 1.905,4.915; 12 0.635,4.915; 13 -0.635,4.915; 14 -1.905,4.915; 15 -3.175,4.915; 16 -4.445,4.915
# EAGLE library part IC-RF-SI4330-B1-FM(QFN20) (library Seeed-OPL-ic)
310060019

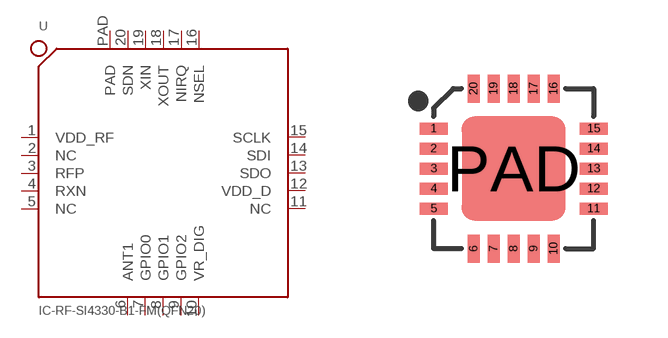
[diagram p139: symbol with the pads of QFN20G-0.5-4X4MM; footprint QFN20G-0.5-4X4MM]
Designator prefix U

## IC-RF-SI4330-B1-FM(QFN20) (MPN: SI4330-B1-FM; VALUE: SI4330-B1-FM-qfn20)  [QFN20G-0.5-4X4MM]
1  VDD_RF
2  NC
3  RFP
4  RXN
5  NC
6  ANT1
7  GPIO0
8  GPIO1
9  GPIO2
10  VR_DIG
11  NC
12  VDD_D
13  SDO
14  SDI
15  SCLK
16  NSEL
17  NIRQ
18  XOUT
19  XIN
20  SDN
PAD  PAD

## Footprint QFN20G-0.5-4X4MM (pad centres in mm)
smd 0.7 x 0.3: 1 -2,1; 2 -2,0.5; 3 -2,0; 4 -2,-0.5; 5 -2,-1; 11 2,-1; 12 2,-0.5; 13 2,0; 14 2,0.5; 15 2,1
smd 0.3 x 0.7: 6 -1,-2; 7 -0.5,-2; 8 0,-2; 9 0.5,-2; 10 1,-2; 16 1,2; 17 0.5,2; 18 0,2; 19 -0.5,2; 20 -1,2
smd 2.6 x 2.6: PAD 0,0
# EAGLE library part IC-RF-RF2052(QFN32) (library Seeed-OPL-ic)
310060015

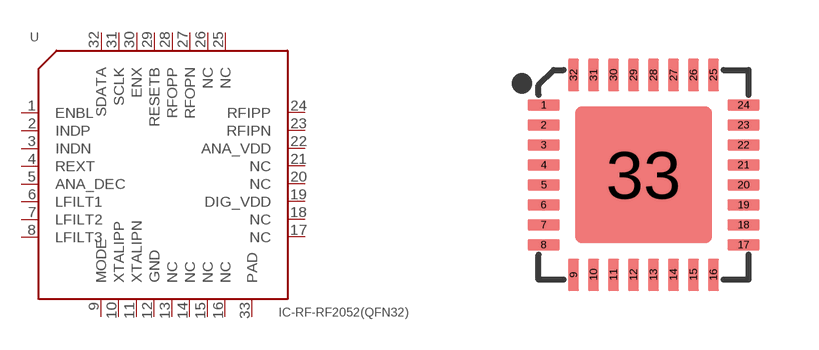
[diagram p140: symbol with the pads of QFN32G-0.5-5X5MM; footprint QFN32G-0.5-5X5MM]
Designator prefix U

## IC-RF-RF2052(QFN32) (MPN: RF2052; VALUE: RF2052-qfn32)  [QFN32G-0.5-5X5MM]
1  ENBL
2  INDP
3  INDN
4  REXT
5  ANA_DEC
6  LFILT1
7  LFILT2
8  LFILT3
9  MODE
10  XTALIPP
11  XTALIPN
12  GND
13  NC
14  NC
15  NC
16  NC
17  NC
18  NC
19  DIG_VDD
20  NC
21  NC
22  ANA_VDD
23  RFIPN
24  RFIPP
25  NC
26  NC
27  RFOPN
28  RFOPP
29  RESETB
30  ENX
31  SCLK
32  SDATA
33  PAD

## Footprint QFN32G-0.5-5X5MM (pad centres in mm)
smd 0.813 x 0.279: 1 -2.5,1.75; 2 -2.5,1.25; 3 -2.5,0.75; 4 -2.5,0.25; 5 -2.5,-0.25; 6 -2.5,-0.75; 7 -2.5,-1.25; 8 -2.5,-1.75; 17 2.5,-1.75; 18 2.5,-1.25; 19 2.5,-0.75; 20 2.5,-0.25; 21 2.5,0.25; 22 2.5,0.75; 23 2.5,1.25; 24 2.5,1.75
smd 0.279 x 0.813: 9 -1.75,-2.5; 10 -1.25,-2.5; 11 -0.75,-2.5; 12 -0.25,-2.5; 13 0.25,-2.5; 14 0.75,-2.5; 15 1.25,-2.5; 16 1.75,-2.5; 25 1.75,2.5; 26 1.25,2.5; 27 0.75,2.5; 28 0.25,2.5; 29 -0.25,2.5; 30 -0.75,2.5; 31 -1.25,2.5; 32 -1.75,2.5
smd 3.429 x 3.429: 33 0,0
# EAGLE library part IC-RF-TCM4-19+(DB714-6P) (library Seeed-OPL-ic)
310060011

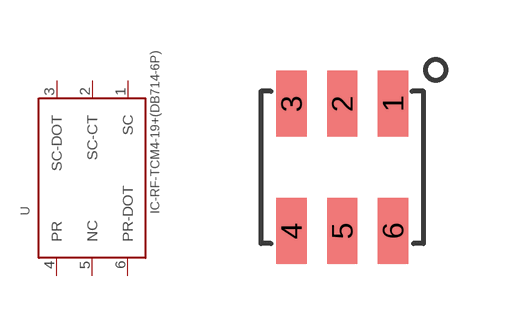
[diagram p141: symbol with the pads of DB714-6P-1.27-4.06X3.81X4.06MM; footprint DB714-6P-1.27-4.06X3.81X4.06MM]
Designator prefix U

## IC-RF-TCM4-19+(DB714-6P) (MPN: TCM4-19+; VALUE: TCM4-19+-DB714)  [DB714-6P-1.27-4.06X3.81X4.06MM]
1  SC
2  SC-CT
3  SC-DOT
4  PR
5  NC
6  PR-DOT

## Footprint DB714-6P-1.27-4.06X3.81X4.06MM (pad centres in mm)
smd 0.76 x 1.65: 1 1.27,1.59; 2 0,1.59; 3 -1.27,1.59; 4 -1.27,-1.59; 5 0,-1.59; 6 1.27,-1.59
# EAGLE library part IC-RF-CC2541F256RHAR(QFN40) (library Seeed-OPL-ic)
310060003

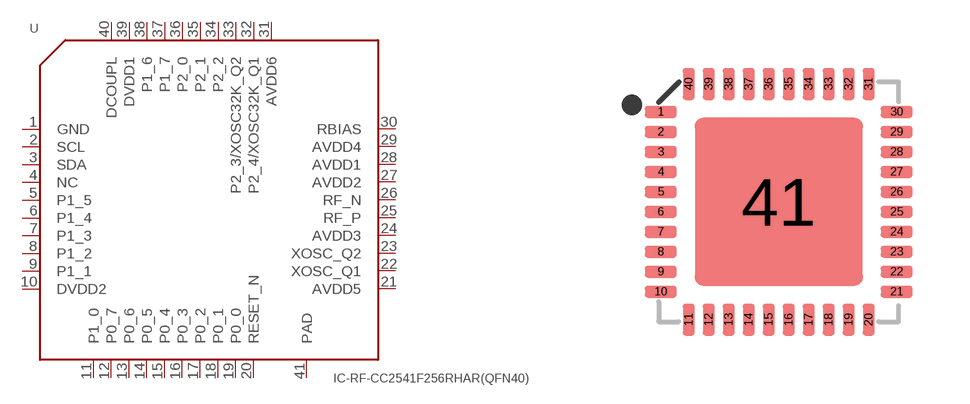
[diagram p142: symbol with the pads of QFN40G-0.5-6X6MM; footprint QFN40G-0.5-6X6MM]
Designator prefix U

## IC-RF-CC2541F256RHAR(QFN40) (MPN: CC2541F256RHAR; VALUE: CC2541F256RHAR-qfn40)  [QFN40G-0.5-6X6MM]
1  GND  sup
2  SCL
3  SDA
4  NC  nc
5  P1_5
6  P1_4
7  P1_3
8  P1_2
9  P1_1
10  DVDD2  pwr
11  P1_0
12  P0_7
13  P0_6
14  P0_5
15  P0_4
16  P0_3
17  P0_2
18  P0_1
19  P0_0
20  RESET_N
21  AVDD5  pwr
22  XOSC_Q1
23  XOSC_Q2
24  AVDD3  pwr
25  RF_P
26  RF_N
27  AVDD2  pwr
28  AVDD1  pwr
29  AVDD4  pwr
30  RBIAS
31  AVDD6  pwr
32  P2_4/XOSC32K_Q1
33  P2_3/XOSC32K_Q2
34  P2_2
35  P2_1
36  P2_0
37  P1_7
38  P1_6
39  DVDD1  pwr
40  DCOUPL
41  PAD  sup

## Footprint QFN40G-0.5-6X6MM (pad centres in mm)
smd 0.8 x 0.3: 1 -2.95,2.25; 2 -2.95,1.75; 3 -2.95,1.25; 4 -2.95,0.75; 5 -2.95,0.25; 6 -2.95,-0.25; 7 -2.95,-0.75; 8 -2.95,-1.25; 9 -2.95,-1.75; 10 -2.95,-2.25; 21 2.95,-2.25; 22 2.95,-1.75; 23 2.95,-1.25; 24 2.95,-0.75; 25 2.95,-0.25; 26 2.95,0.25; 27 2.95,0.75; 28 2.95,1.25; 29 2.95,1.75; 30 2.95,2.25
smd 0.3 x 0.8: 11 -2.25,-2.95; 12 -1.75,-2.95; 13 -1.25,-2.95; 14 -0.75,-2.95; 15 -0.25,-2.95; 16 0.25,-2.95; 17 0.75,-2.95; 18 1.25,-2.95; 19 1.75,-2.95; 20 2.25,-2.95; 31 2.25,2.95; 32 1.75,2.95; 33 1.25,2.95; 34 0.75,2.95; 35 0.25,2.95; 36 -0.25,2.95; 37 -0.75,2.95; 38 -1.25,2.95; 39 -1.75,2.95; 40 -2.25,2.95
smd 4.2 x 4.2: 41 0,0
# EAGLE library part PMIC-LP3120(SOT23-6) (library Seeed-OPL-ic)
310030090

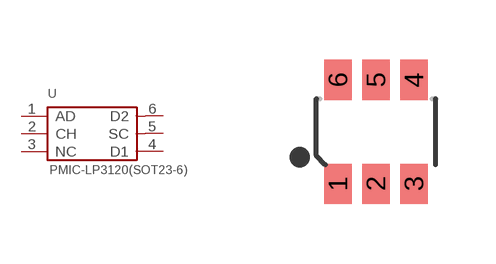
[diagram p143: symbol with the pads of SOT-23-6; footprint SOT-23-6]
Designator prefix U

## PMIC-LP3120(SOT23-6) (MPN: LP3120; VALUE: LP3120-sot23-6)  [SOT-23-6]
1  AD  in
2  CH  in
3  NC  nc
4  D1
5  SC  in
6  D2  out

## Footprint SOT-23-6 (pad centres in mm)
smd 0.69 x 1: 1 -0.95,-1.3; 2 0,-1.3; 3 0.95,-1.3; 4 0.95,1.3; 5 0,1.3; 6 -0.95,1.3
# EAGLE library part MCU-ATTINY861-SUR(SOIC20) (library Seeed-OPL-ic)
310010076

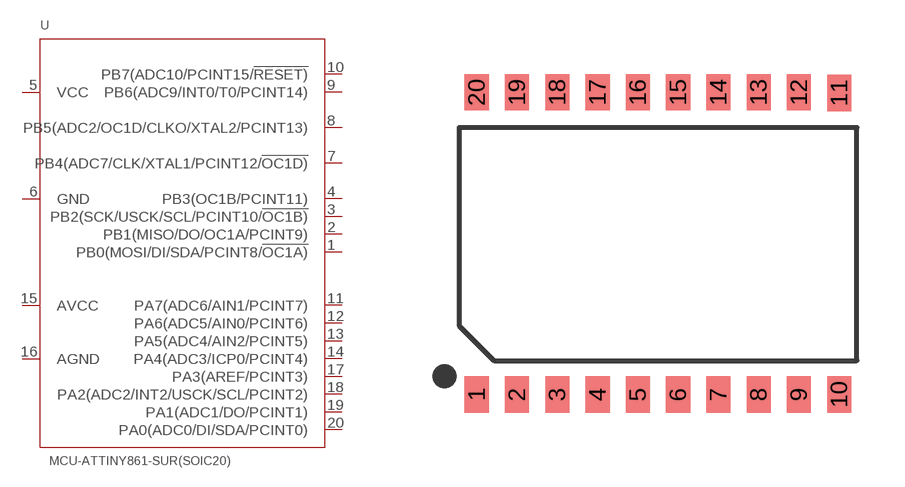
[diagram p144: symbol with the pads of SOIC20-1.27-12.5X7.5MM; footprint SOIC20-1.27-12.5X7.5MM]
Designator prefix U

## MCU-ATTINY861-SUR(SOIC20) (MPN: ATTINY861A-SUR; VALUE: ATTINY861A-SUR-soic20)  [SOIC20-1.27-12.5X7.5MM]
1  PB0(MOSI/DI/SDA/PCINT8/!OC1A)
2  PB1(MISO/DO/OC1A/PCINT9)
3  PB2(SCK/USCK/SCL/PCINT10/!OC1B)
4  PB3(OC1B/PCINT11)
5  VCC  pwr
6  GND  sup
7  PB4(ADC7/CLK/XTAL1/PCINT12/!OC1D)
8  PB5(ADC2/OC1D/CLKO/XTAL2/PCINT13)
9  PB6(ADC9/INT0/T0/PCINT14)
10  PB7(ADC10/PCINT15/!RESET)
11  PA7(ADC6/AIN1/PCINT7)
12  PA6(ADC5/AIN0/PCINT6)
13  PA5(ADC4/AIN2/PCINT5)
14  PA4(ADC3/ICP0/PCINT4)
15  AVCC  pwr
16  AGND  sup
17  PA3(AREF/PCINT3)
18  PA2(ADC2/INT2/USCK/SCL/PCINT2)
19  PA1(ADC1/DO/PCINT1)
20  PA0(ADC0/DI/SDA/PCINT0)

## Footprint SOIC20-1.27-12.5X7.5MM (pad centres in mm)
Small Outline Package
smd 0.762 x 1.143: 1 -5.715,-4.75; 2 -4.445,-4.75; 3 -3.175,-4.75; 4 -1.905,-4.75; 5 -0.635,-4.75; 6 0.635,-4.75; 7 1.905,-4.75; 8 3.175,-4.75; 9 4.445,-4.75; 10 5.715,-4.75; 11 5.715,4.75; 12 4.445,4.775; 13 3.175,4.775; 14 1.905,4.775; 15 0.635,4.775; 16 -0.635,4.775; 17 -1.905,4.775; 18 -3.175,4.775; 19 -4.445,4.775; 20 -5.715,4.775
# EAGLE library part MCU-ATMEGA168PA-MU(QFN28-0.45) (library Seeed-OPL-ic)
310010072

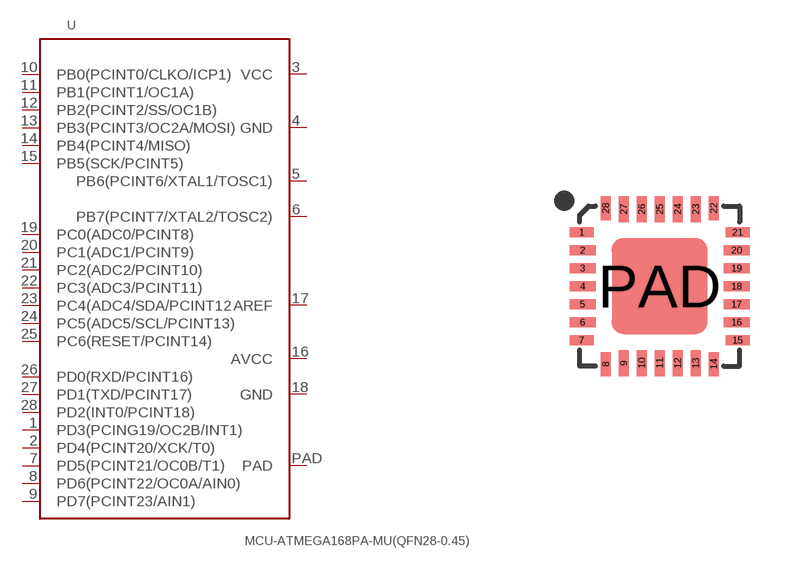
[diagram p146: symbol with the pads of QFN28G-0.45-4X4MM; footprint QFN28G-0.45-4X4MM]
Designator prefix U

## MCU-ATMEGA168PA-MU(QFN28-0.45) (MPN: ATMEGA168PA-MU; VALUE: ATMEGA168PA-MU-QFN28)  [QFN28G-0.45-4X4MM]
1  PD3(PCING19/OC2B/INT1)
2  PD4(PCINT20/XCK/T0)
3  VCC
4  GND
5  PB6(PCINT6/XTAL1/TOSC1)
6  PB7(PCINT7/XTAL2/TOSC2)
7  PD5(PCINT21/OC0B/T1)
8  PD6(PCINT22/OC0A/AIN0)
9  PD7(PCINT23/AIN1)
10  PB0(PCINT0/CLKO/ICP1)
11  PB1(PCINT1/OC1A)
12  PB2(PCINT2/SS/OC1B)
13  PB3(PCINT3/OC2A/MOSI)
14  PB4(PCINT4/MISO)
15  PB5(SCK/PCINT5)
16  AVCC
17  AREF
18  GND
19  PC0(ADC0/PCINT8)
20  PC1(ADC1/PCINT9)
21  PC2(ADC2/PCINT10)
22  PC3(ADC3/PCINT11)
23  PC4(ADC4/SDA/PCINT12
24  PC5(ADC5/SCL/PCINT13)
25  PC6(RESET/PCINT14)
26  PD0(RXD/PCINT16)
27  PD1(TXD/PCINT17)
28  PD2(INT0/PCINT18)
PAD  PAD

## Footprint QFN28G-0.45-4X4MM (pad centres in mm)
smd 0.6 x 0.25: 1 -1.95,1.35; 7 -1.95,-1.35; 15 1.95,-1.35; 21 1.95,1.35
smd 0.65 x 0.25: 2 -1.925,0.9; 3 -1.925,0.45; 4 -1.925,0; 5 -1.925,-0.45; 6 -1.925,-0.9; 16 1.925,-0.9; 17 1.925,-0.45; 18 1.925,0; 19 1.925,0.45; 20 1.925,0.9
smd 0.25 x 0.6: 8 -1.35,-1.95; 14 1.35,-1.95; 22 1.35,1.95; 28 -1.35,1.95
smd 0.25 x 0.65: 9 -0.9,-1.925; 10 -0.45,-1.925; 11 0,-1.925; 12 0.45,-1.925; 13 0.9,-1.925; 23 0.9,1.925; 24 0.45,1.925; 25 0,1.925; 26 -0.45,1.925; 27 -0.9,1.925
smd 2.4 x 2.4: PAD 0,0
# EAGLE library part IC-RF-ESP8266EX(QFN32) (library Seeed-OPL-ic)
310060034

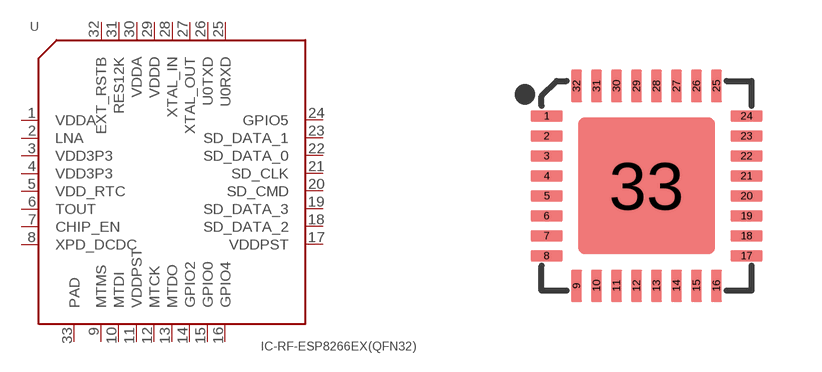
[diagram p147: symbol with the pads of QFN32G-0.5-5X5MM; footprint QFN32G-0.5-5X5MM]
Designator prefix U

## IC-RF-ESP8266EX(QFN32) (MPN: ESP8266EX; VALUE: ESP8266EX)  [QFN32G-0.5-5X5MM]
1  VDDA  pwr
2  LNA
3  VDD3P3  pwr
4  VDD3P3  pwr
5  VDD_RTC
6  TOUT  out
7  CHIP_EN
8  XPD_DCDC
9  MTMS
10  MTDI
11  VDDPST
12  MTCK
13  MTDO
14  GPIO2
15  GPIO0
16  GPIO4
17  VDDPST
18  SD_DATA_2
19  SD_DATA_3
20  SD_CMD
21  SD_CLK
22  SD_DATA_0
23  SD_DATA_1
24  GPIO5
25  U0RXD
26  U0TXD
27  XTAL_OUT
28  XTAL_IN
29  VDDD
30  VDDA
31  RES12K
32  EXT_RSTB
33  PAD

## Footprint QFN32G-0.5-5X5MM (pad centres in mm)
smd 0.813 x 0.279: 1 -2.5,1.75; 2 -2.5,1.25; 3 -2.5,0.75; 4 -2.5,0.25; 5 -2.5,-0.25; 6 -2.5,-0.75; 7 -2.5,-1.25; 8 -2.5,-1.75; 17 2.5,-1.75; 18 2.5,-1.25; 19 2.5,-0.75; 20 2.5,-0.25; 21 2.5,0.25; 22 2.5,0.75; 23 2.5,1.25; 24 2.5,1.75
smd 0.279 x 0.813: 9 -1.75,-2.5; 10 -1.25,-2.5; 11 -0.75,-2.5; 12 -0.25,-2.5; 13 0.25,-2.5; 14 0.75,-2.5; 15 1.25,-2.5; 16 1.75,-2.5; 25 1.75,2.5; 26 1.25,2.5; 27 0.75,2.5; 28 0.25,2.5; 29 -0.25,2.5; 30 -0.75,2.5; 31 -1.25,2.5; 32 -1.75,2.5
smd 3.429 x 3.429: 33 0,0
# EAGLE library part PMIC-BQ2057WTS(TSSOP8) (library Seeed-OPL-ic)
310030039

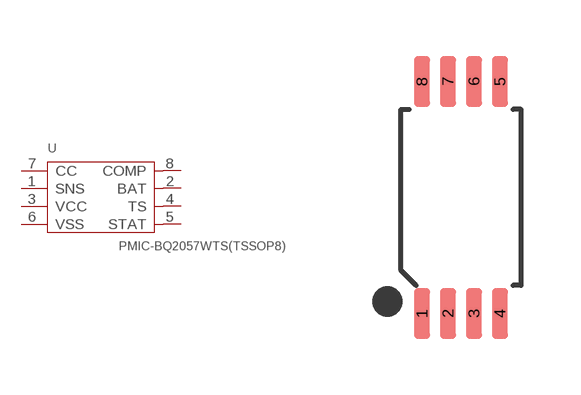
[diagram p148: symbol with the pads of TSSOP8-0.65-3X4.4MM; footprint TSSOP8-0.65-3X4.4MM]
Designator prefix U

## PMIC-BQ2057WTS(TSSOP8) (MPN: BQ2057WTS; VALUE: BQ2057WTS)  [TSSOP8-0.65-3X4.4MM]
1  SNS
2  BAT
3  VCC  pwr
4  TS
5  STAT
6  VSS  sup
7  CC  in
8  COMP  in

## Footprint TSSOP8-0.65-3X4.4MM (pad centres in mm)
smd 0.4 x 1.27: 1 -0.975,-2.9; 2 -0.325,-2.9; 3 0.325,-2.9; 4 0.975,-2.9; 5 0.975,2.9; 6 0.325,2.9; 7 -0.325,2.9; 8 -0.975,2.9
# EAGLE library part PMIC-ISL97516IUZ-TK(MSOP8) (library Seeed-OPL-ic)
310030092

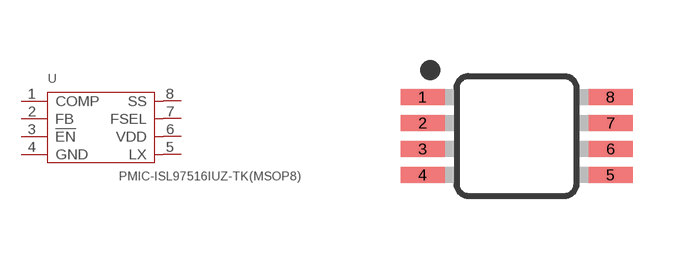
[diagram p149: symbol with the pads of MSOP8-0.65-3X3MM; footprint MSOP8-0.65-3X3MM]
Designator prefix U

## PMIC-ISL97516IUZ-TK(MSOP8) (MPN: ISL97516IUZ-TK; VALUE: ISL97516IUZ-TK)  [MSOP8-0.65-3X3MM]
1  COMP  in
2  FB
3  !EN  in
4  GND  sup
5  LX
6  VDD  pwr
7  FSEL
8  SS

## Footprint MSOP8-0.65-3X3MM (pad centres in mm)
8M, 8-Lead, 0.118" Wide, Miniature Small Outline Package MSOP 8M-Package doc1097.pdf
smd 1.1 x 0.4: 1 -2.35,0.975; 2 -2.35,0.325; 3 -2.35,-0.325; 4 -2.35,-0.975; 5 2.35,-0.975; 6 2.35,-0.325; 7 2.35,0.325; 8 2.35,0.975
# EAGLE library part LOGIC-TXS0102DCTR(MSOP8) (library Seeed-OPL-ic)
310050061

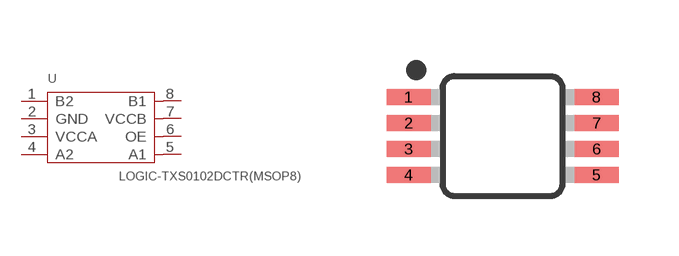
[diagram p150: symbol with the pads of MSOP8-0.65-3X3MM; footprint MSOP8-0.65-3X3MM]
Designator prefix U

## LOGIC-TXS0102DCTR(MSOP8) (MPN: TXS0102DCTR; VALUE: TXS0102DCTR)  [MSOP8-0.65-3X3MM]
1  B2  in
2  GND  sup
3  VCCA  pwr
4  A2
5  A1
6  OE
7  VCCB  pwr
8  B1

## Footprint MSOP8-0.65-3X3MM (pad centres in mm)
8M, 8-Lead, 0.118" Wide, Miniature Small Outline Package MSOP 8M-Package doc1097.pdf
smd 1.1 x 0.4: 1 -2.35,0.975; 2 -2.35,0.325; 3 -2.35,-0.325; 4 -2.35,-0.975; 5 2.35,-0.975; 6 2.35,-0.325; 7 2.35,0.325; 8 2.35,0.975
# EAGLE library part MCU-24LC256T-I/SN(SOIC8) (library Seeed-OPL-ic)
310090063

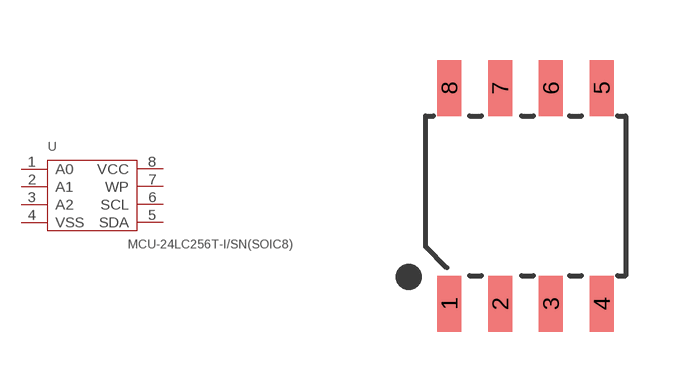
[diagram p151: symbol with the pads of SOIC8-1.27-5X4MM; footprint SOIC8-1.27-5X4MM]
Designator prefix U

## MCU-24LC256T-I/SN(SOIC8) (MPN: 24LC256T-I/SN; VALUE: 24LC256T-I/SN)  [SOIC8-1.27-5X4MM]
1  A0
2  A1
3  A2
4  VSS  sup
5  SDA
6  SCL
7  WP
8  VCC  pwr

## Footprint SOIC8-1.27-5X4MM (pad centres in mm)
smd 0.6 x 1.4: 1 -1.905,-2.7; 2 -0.635,-2.7; 3 0.635,-2.7; 4 1.905,-2.7; 5 1.905,2.7; 6 0.635,2.7; 7 -0.635,2.7; 8 -1.905,2.7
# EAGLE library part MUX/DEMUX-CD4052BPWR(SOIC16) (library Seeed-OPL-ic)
310070052

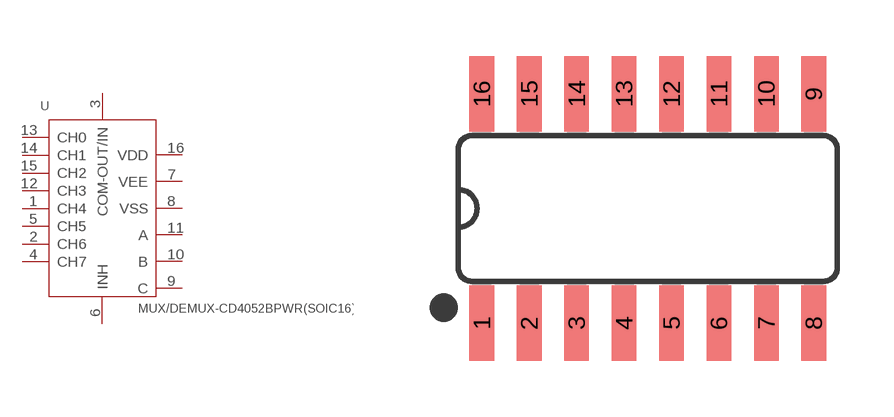
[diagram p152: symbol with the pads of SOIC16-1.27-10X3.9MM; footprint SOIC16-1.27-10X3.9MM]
Designator prefix U

## MUX/DEMUX-CD4052BPWR(SOIC16) (MPN: CD4052BPWR; VALUE: CD4052BPWR)  [SOIC16-1.27-10X3.9MM]
1  CH4
2  CH6
3  COM-OUT/IN  in
4  CH7
5  CH5
6  INH  in
7  VEE  in
8  VSS  sup
9  C  in
10  B
11  A
12  CH3
13  CH0
14  CH1
15  CH2
16  VDD  pwr

## Footprint SOIC16-1.27-10X3.9MM (pad centres in mm)
Small Outline package 150 mil
smd 0.66 x 2.032: 1 -4.445,-3.073; 2 -3.175,-3.073; 3 -1.905,-3.073; 4 -0.635,-3.073; 5 0.635,-3.073; 6 1.905,-3.073; 7 3.175,-3.073; 8 4.445,-3.073; 9 4.445,3.073; 10 3.175,3.073; 11 1.905,3.073; 12 0.635,3.073; 13 -0.635,3.073; 14 -1.905,3.073; 15 -3.175,3.073; 16 -4.445,3.073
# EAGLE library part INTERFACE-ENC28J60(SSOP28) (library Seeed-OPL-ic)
310070055

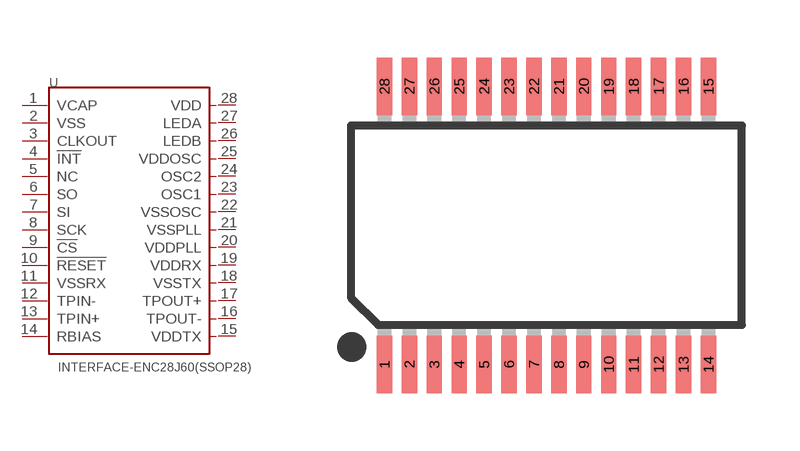
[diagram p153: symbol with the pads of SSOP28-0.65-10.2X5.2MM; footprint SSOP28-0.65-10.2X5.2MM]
Designator prefix U

## INTERFACE-ENC28J60(SSOP28) (MPN: ENC28J60; VALUE: ENC28J60v)  [SSOP28-0.65-10.2X5.2MM]
1  VCAP  pwr
2  VSS  sup
3  CLKOUT
4  !INT
5  NC  nc
6  SO
7  SI
8  SCK
9  !CS
10  !RESET
11  VSSRX
12  TPIN-
13  TPIN+
14  RBIAS
15  VDDTX  pwr
16  TPOUT-
17  TPOUT+
18  VSSTX  sup
19  VDDRX  pwr
20  VDDPLL  pwr
21  VSSPLL  sup
22  VSSOSC  sup
23  OSC1
24  OSC2
25  VDDOSC  pwr
26  LEDB
27  LEDA  pwr
28  VDD  pwr

## Footprint SSOP28-0.65-10.2X5.2MM (pad centres in mm)
Shrink Small Outline Package SSOP-28 http://www.ftdichip.com/Documents/DataSheets/DS_FT232R_v104.pdf
smd 0.4 x 1.5: 1 -4.225,-3.625; 2 -3.575,-3.625; 3 -2.925,-3.625; 4 -2.275,-3.625; 5 -1.625,-3.625; 6 -0.975,-3.625; 7 -0.325,-3.625; 8 0.325,-3.625; 9 0.975,-3.625; 10 1.625,-3.625; 11 2.275,-3.625; 12 2.925,-3.625; 13 3.575,-3.625; 14 4.225,-3.625; 15 4.225,3.625; 16 3.575,3.625; 17 2.925,3.625; 18 2.275,3.625; 19 1.625,3.625; 20 0.975,3.625; 21 0.325,3.625; 22 -0.325,3.625; 23 -0.975,3.625; 24 -1.625,3.625; 25 -2.275,3.625; 26 -2.925,3.625; 27 -3.575,3.625; 28 -4.225,3.625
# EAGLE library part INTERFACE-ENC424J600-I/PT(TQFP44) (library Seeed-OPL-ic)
310070053

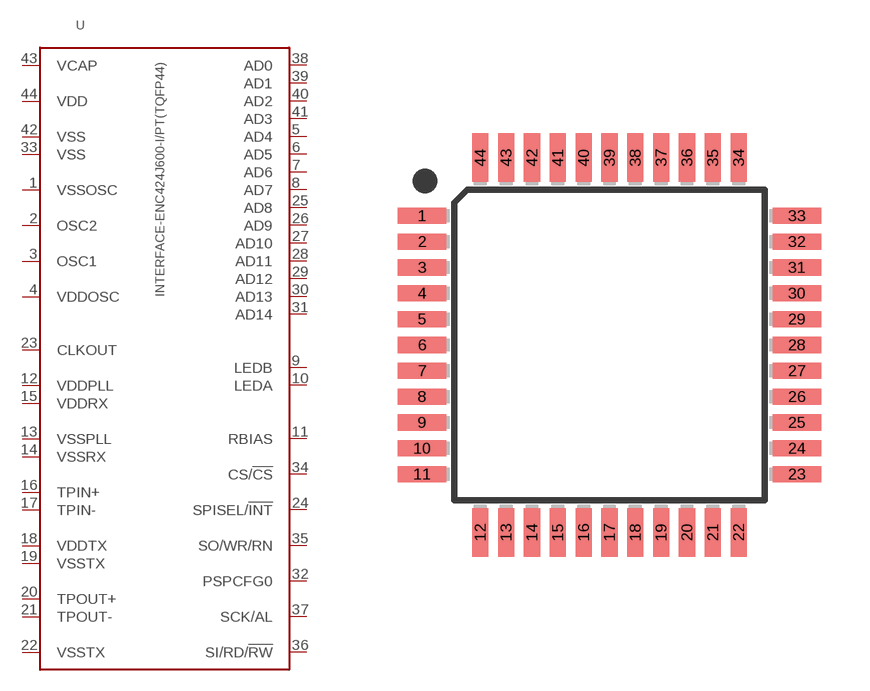
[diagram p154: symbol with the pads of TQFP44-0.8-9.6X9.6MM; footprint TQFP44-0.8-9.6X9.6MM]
Designator prefix U

## INTERFACE-ENC424J600-I/PT(TQFP44) (MPN: ENC424J600-I/PT; VALUE: ENC424J600-I/PT)  [TQFP44-0.8-9.6X9.6MM]
1  VSSOSC  sup
2  OSC2
3  OSC1
4  VDDOSC  pwr
5  AD4
6  AD5
7  AD6
8  AD7
9  LEDB
10  LEDA
11  RBIAS
12  VDDPLL  pwr
13  VSSPLL  sup
14  VSSRX  sup
15  VDDRX  pwr
16  TPIN+
17  TPIN-
18  VDDTX  pwr
19  VSSTX  sup
20  TPOUT+
21  TPOUT-
22  VSSTX  sup
23  CLKOUT
24  SPISEL/!INT
25  AD8
26  AD9
27  AD10
28  AD11
29  AD12
30  AD13
31  AD14
32  PSPCFG0
33  VSS  sup
34  CS/!CS
35  SO/WR/RN
36  SI/RD/!RW
37  SCK/AL
38  AD0
39  AD1
40  AD2
41  AD3
42  VSS  sup
43  VCAP
44  VDD  pwr

## Footprint TQFP44-0.8-9.6X9.6MM (pad centres in mm)
Thin Plasic Quad Flat Package
smd 1.5 x 0.5: 1 -5.8,4; 2 -5.8,3.2; 3 -5.8,2.4; 4 -5.8,1.6; 5 -5.8,0.8; 6 -5.8,0; 7 -5.8,-0.8; 8 -5.8,-1.6; 9 -5.8,-2.4; 10 -5.8,-3.2; 11 -5.8,-4; 23 5.8,-4; 24 5.8,-3.2; 25 5.8,-2.4; 26 5.8,-1.6; 27 5.8,-0.8; 28 5.8,0; 29 5.8,0.8; 30 5.8,1.6; 31 5.8,2.4; 32 5.8,3.2; 33 5.8,4
smd 0.5 x 1.5: 12 -4,-5.8; 13 -3.2,-5.8; 14 -2.4,-5.8; 15 -1.6,-5.8; 16 -0.8,-5.8; 17 0,-5.8; 18 0.8,-5.8; 19 1.6,-5.8; 20 2.4,-5.8; 21 3.2,-5.8; 22 4,-5.8; 34 4,5.8; 35 3.2,5.8; 36 2.4,5.8; 37 1.6,5.8; 38 0.8,5.8; 39 0,5.8; 40 -0.8,5.8; 41 -1.6,5.8; 42 -2.4,5.8; 43 -3.2,5.8; 44 -4,5.8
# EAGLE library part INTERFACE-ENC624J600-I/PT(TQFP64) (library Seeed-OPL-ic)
310070054

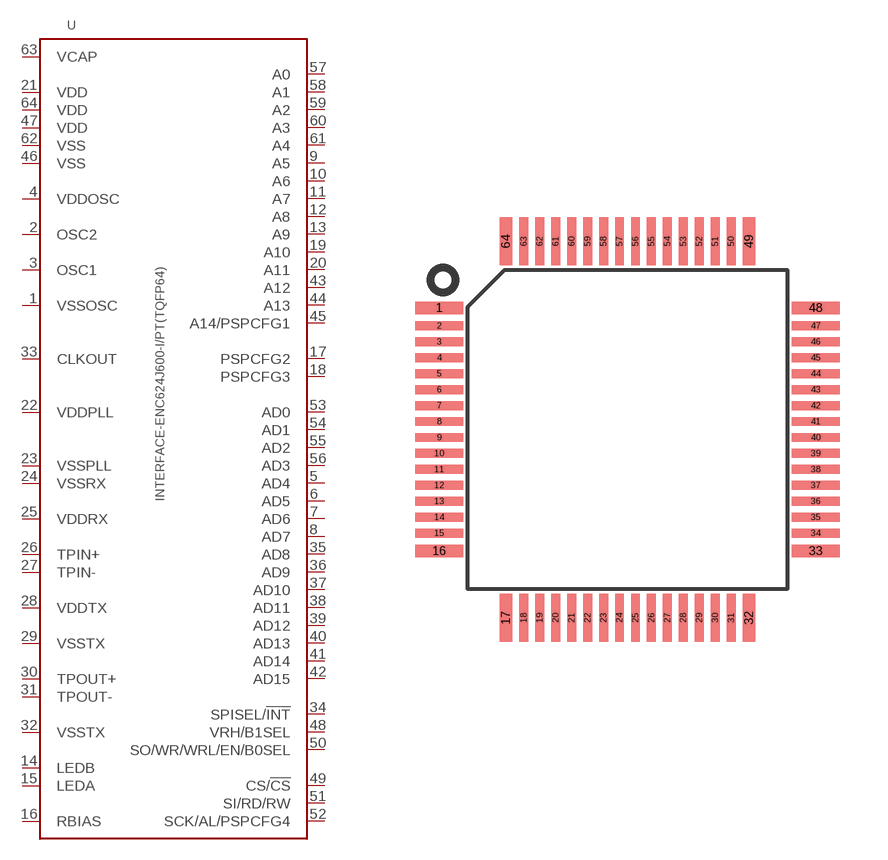
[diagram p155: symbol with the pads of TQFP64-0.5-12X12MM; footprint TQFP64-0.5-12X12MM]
Designator prefix U

## INTERFACE-ENC624J600-I/PT(TQFP64) (MPN: ENC624J600-I/PT; VALUE: ENC624J600-I/PT)  [TQFP64-0.5-12X12MM]
1  VSSOSC  sup
2  OSC2
3  OSC1
4  VDDOSC  pwr
5  AD4
6  AD5
7  AD6
8  AD7
9  A5
10  A6
11  A7
12  A8
13  A9
14  LEDB
15  LEDA
16  RBIAS
17  PSPCFG2
18  PSPCFG3
19  A10
20  A11
21  VDD  pwr
22  VDDPLL  pwr
23  VSSPLL  sup
24  VSSRX  sup
25  VDDRX  pwr
26  TPIN+
27  TPIN-
28  VDDTX  pwr
29  VSSTX  sup
30  TPOUT+
31  TPOUT-
32  VSSTX  sup
33  CLKOUT
34  SPISEL/!INT
35  AD8
36  AD9
37  AD10
38  AD11
39  AD12
40  AD13
41  AD14
42  AD15
43  A12
44  A13
45  A14/PSPCFG1
46  VSS  sup
47  VDD  pwr
48  VRH/B1SEL
49  CS/!CS
50  SO/WR/WRL/EN/B0SEL
51  SI/RD/RW
52  SCK/AL/PSPCFG4
53  AD0
54  AD1
55  AD2
56  AD3
57  A0
58  A1
59  A2
60  A3
61  A4
62  VSS  sup
63  VCAP
64  VDD  pwr

## Footprint TQFP64-0.5-12X12MM (pad centres in mm)
smd 1.5 x 0.4: 1 -5.9,3.81; 16 -5.9,-3.81; 33 5.9,-3.81; 48 5.9,3.81
smd 1.5 x 0.28: 2 -5.9,3.25; 3 -5.9,2.75; 4 -5.9,2.25; 5 -5.9,1.75; 6 -5.9,1.25; 7 -5.9,0.75; 8 -5.9,0.25; 9 -5.9,-0.25; 10 -5.9,-0.75; 11 -5.9,-1.25; 12 -5.9,-1.75; 13 -5.9,-2.25; 14 -5.9,-2.75; 15 -5.9,-3.25; 34 5.9,-3.25; 35 5.9,-2.75; 36 5.9,-2.25; 37 5.9,-1.75; 38 5.9,-1.25; 39 5.9,-0.75; 40 5.9,-0.25; 41 5.9,0.25; 42 5.9,0.75; 43 5.9,1.25; 44 5.9,1.75; 45 5.9,2.25; 46 5.9,2.75; 47 5.9,3.25
smd 0.4 x 1.5: 17 -3.81,-5.9; 32 3.81,-5.9; 49 3.81,5.9; 64 -3.81,5.9
smd 0.28 x 1.5: 18 -3.25,-5.9; 19 -2.75,-5.9; 20 -2.25,-5.9; 21 -1.75,-5.9; 22 -1.25,-5.9; 23 -0.75,-5.9; 24 -0.25,-5.9; 25 0.25,-5.9; 26 0.75,-5.9; 27 1.25,-5.9; 28 1.75,-5.9; 29 2.25,-5.9; 30 2.75,-5.9; 31 3.25,-5.9; 50 3.25,5.9; 51 2.75,5.9; 52 2.25,5.9; 53 1.75,5.9; 54 1.25,5.9; 55 0.75,5.9; 56 0.25,5.9; 57 -0.25,5.9; 58 -0.75,5.9; 59 -1.25,5.9; 60 -1.75,5.9; 61 -2.25,5.9; 62 -2.75,5.9; 63 -3.25,5.9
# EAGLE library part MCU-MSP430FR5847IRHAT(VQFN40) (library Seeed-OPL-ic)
310010136

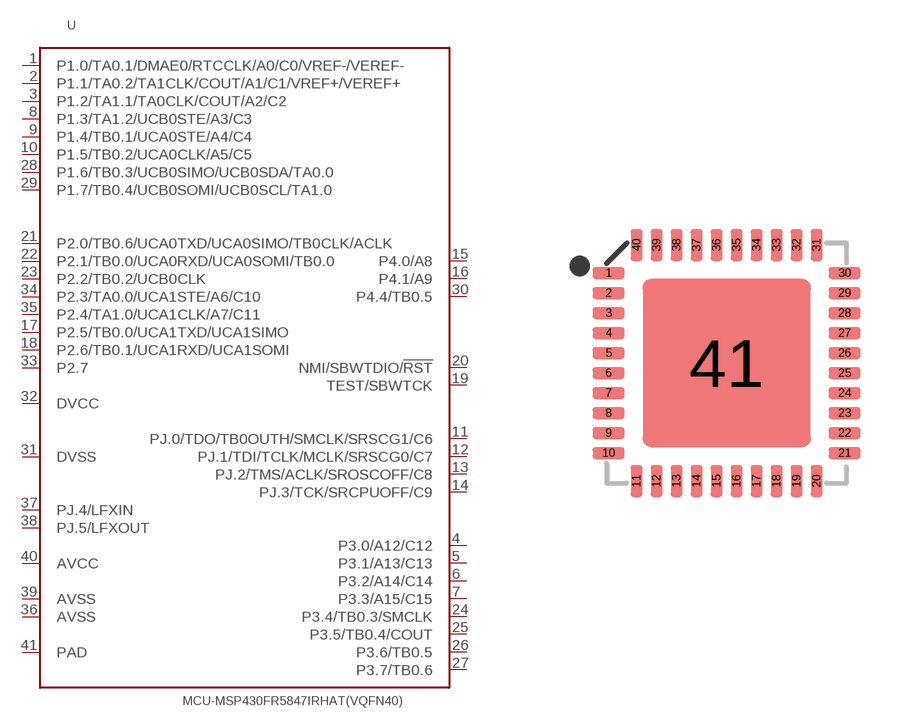
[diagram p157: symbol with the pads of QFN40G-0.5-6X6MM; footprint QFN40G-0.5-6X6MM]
Designator prefix U

## MCU-MSP430FR5847IRHAT(VQFN40) (MPN: MSP430FR5847IRHAT; VALUE: MSP430FR5847IRHAT)  [QFN40G-0.5-6X6MM]
1  P1.0/TA0.1/DMAE0/RTCCLK/A0/C0/VREF-/VEREF-
2  P1.1/TA0.2/TA1CLK/COUT/A1/C1/VREF+/VEREF+
3  P1.2/TA1.1/TA0CLK/COUT/A2/C2
4  P3.0/A12/C12
5  P3.1/A13/C13
6  P3.2/A14/C14
7  P3.3/A15/C15
8  P1.3/TA1.2/UCB0STE/A3/C3
9  P1.4/TB0.1/UCA0STE/A4/C4
10  P1.5/TB0.2/UCA0CLK/A5/C5
11  PJ.0/TDO/TB0OUTH/SMCLK/SRSCG1/C6
12  PJ.1/TDI/TCLK/MCLK/SRSCG0/C7
13  PJ.2/TMS/ACLK/SROSCOFF/C8
14  PJ.3/TCK/SRCPUOFF/C9
15  P4.0/A8
16  P4.1/A9
17  P2.5/TB0.0/UCA1TXD/UCA1SIMO
18  P2.6/TB0.1/UCA1RXD/UCA1SOMI
19  TEST/SBWTCK
20  NMI/SBWTDIO/!RST
21  P2.0/TB0.6/UCA0TXD/UCA0SIMO/TB0CLK/ACLK
22  P2.1/TB0.0/UCA0RXD/UCA0SOMI/TB0.0
23  P2.2/TB0.2/UCB0CLK
24  P3.4/TB0.3/SMCLK
25  P3.5/TB0.4/COUT
26  P3.6/TB0.5
27  P3.7/TB0.6
28  P1.6/TB0.3/UCB0SIMO/UCB0SDA/TA0.0
29  P1.7/TB0.4/UCB0SOMI/UCB0SCL/TA1.0
30  P4.4/TB0.5
31  DVSS
32  DVCC
33  P2.7
34  P2.3/TA0.0/UCA1STE/A6/C10
35  P2.4/TA1.0/UCA1CLK/A7/C11
36  AVSS
37  PJ.4/LFXIN
38  PJ.5/LFXOUT
39  AVSS
40  AVCC
41  PAD

## Footprint QFN40G-0.5-6X6MM (pad centres in mm)
smd 0.8 x 0.3: 1 -2.95,2.25; 2 -2.95,1.75; 3 -2.95,1.25; 4 -2.95,0.75; 5 -2.95,0.25; 6 -2.95,-0.25; 7 -2.95,-0.75; 8 -2.95,-1.25; 9 -2.95,-1.75; 10 -2.95,-2.25; 21 2.95,-2.25; 22 2.95,-1.75; 23 2.95,-1.25; 24 2.95,-0.75; 25 2.95,-0.25; 26 2.95,0.25; 27 2.95,0.75; 28 2.95,1.25; 29 2.95,1.75; 30 2.95,2.25
smd 0.3 x 0.8: 11 -2.25,-2.95; 12 -1.75,-2.95; 13 -1.25,-2.95; 14 -0.75,-2.95; 15 -0.25,-2.95; 16 0.25,-2.95; 17 0.75,-2.95; 18 1.25,-2.95; 19 1.75,-2.95; 20 2.25,-2.95; 31 2.25,2.95; 32 1.75,2.95; 33 1.25,2.95; 34 0.75,2.95; 35 0.25,2.95; 36 -0.25,2.95; 37 -0.75,2.95; 38 -1.25,2.95; 39 -1.75,2.95; 40 -2.25,2.95
smd 4.2 x 4.2: 41 0,0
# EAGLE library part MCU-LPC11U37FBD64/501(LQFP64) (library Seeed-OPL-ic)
310010071

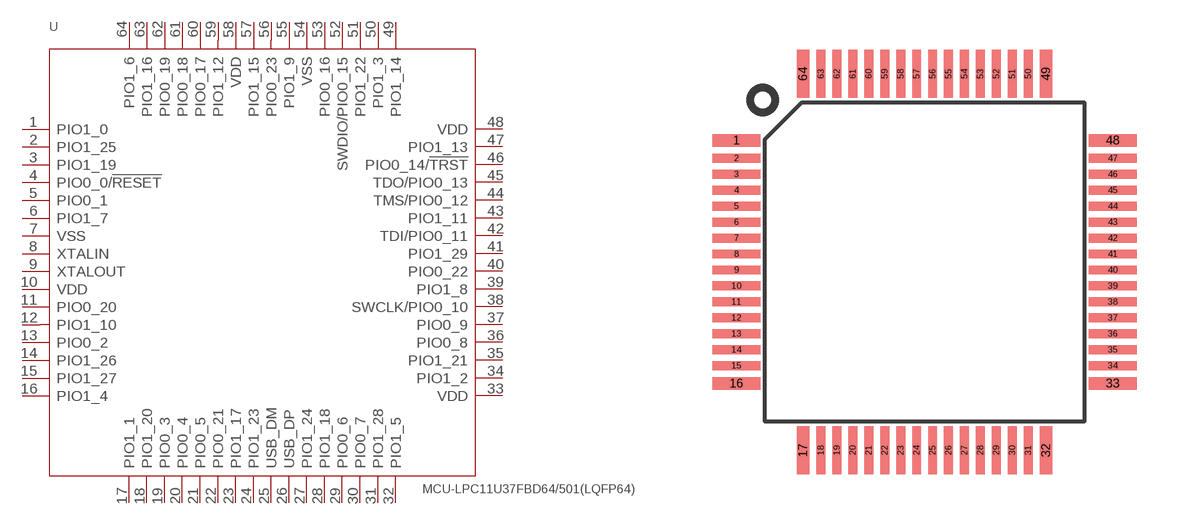
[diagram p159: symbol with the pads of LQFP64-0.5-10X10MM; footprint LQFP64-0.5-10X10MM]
Designator prefix U

## MCU-LPC11U37FBD64/501(LQFP64) (MPN: LPC11U37FBD64/501; VALUE: LPC11U37FBD64/501)  [LQFP64-0.5-10X10MM]
1  PIO1_0
2  PIO1_25
3  PIO1_19
4  PIO0_0/!RESET
5  PIO0_1
6  PIO1_7
7  VSS  sup
8  XTALIN
9  XTALOUT
10  VDD  pwr
11  PIO0_20
12  PIO1_10
13  PIO0_2
14  PIO1_26
15  PIO1_27
16  PIO1_4
17  PIO1_1
18  PIO1_20
19  PIO0_3
20  PIO0_4
21  PIO0_5
22  PIO0_21
23  PIO1_17
24  PIO1_23
25  USB_DM
26  USB_DP
27  PIO1_24
28  PIO1_18
29  PIO0_6
30  PIO0_7
31  PIO1_28
32  PIO1_5
33  VDD  pwr
34  PIO1_2
35  PIO1_21
36  PIO0_8
37  PIO0_9
38  SWCLK/PIO0_10
39  PIO1_8
40  PIO0_22
41  PIO1_29
42  TDI/PIO0_11
43  PIO1_11
44  TMS/PIO0_12
45  TDO/PIO0_13
46  PIO0_14/!TRST
47  PIO1_13
48  VDD  pwr
49  PIO1_14
50  PIO1_3
51  PIO1_22
52  SWDIO/PIO0_15
53  PIO0_16
54  VSS
55  PIO1_9
56  PIO0_23
57  PIO1_15
58  VDD  pwr
59  PIO1_12
60  PIO0_17
61  PIO0_18
62  PIO0_19
63  PIO1_16
64  PIO1_6

## Footprint LQFP64-0.5-10X10MM (pad centres in mm)
smd 1.5 x 0.4: 1 -5.9,3.81; 16 -5.9,-3.81; 33 5.9,-3.81; 48 5.9,3.81
smd 1.5 x 0.28: 2 -5.9,3.25; 3 -5.9,2.75; 4 -5.9,2.25; 5 -5.9,1.75; 6 -5.9,1.25; 7 -5.9,0.75; 8 -5.9,0.25; 9 -5.9,-0.25; 10 -5.9,-0.75; 11 -5.9,-1.25; 12 -5.9,-1.75; 13 -5.9,-2.25; 14 -5.9,-2.75; 15 -5.9,-3.25; 34 5.9,-3.25; 35 5.9,-2.75; 36 5.9,-2.25; 37 5.9,-1.75; 38 5.9,-1.25; 39 5.9,-0.75; 40 5.9,-0.25; 41 5.9,0.25; 42 5.9,0.75; 43 5.9,1.25; 44 5.9,1.75; 45 5.9,2.25; 46 5.9,2.75; 47 5.9,3.25
smd 0.4 x 1.5: 17 -3.81,-5.9; 32 3.81,-5.9; 49 3.81,5.9; 64 -3.81,5.9
smd 0.28 x 1.5: 18 -3.25,-5.9; 19 -2.75,-5.9; 20 -2.25,-5.9; 21 -1.75,-5.9; 22 -1.25,-5.9; 23 -0.75,-5.9; 24 -0.25,-5.9; 25 0.25,-5.9; 26 0.75,-5.9; 27 1.25,-5.9; 28 1.75,-5.9; 29 2.25,-5.9; 30 2.75,-5.9; 31 3.25,-5.9; 50 3.25,5.9; 51 2.75,5.9; 52 2.25,5.9; 53 1.75,5.9; 54 1.25,5.9; 55 0.75,5.9; 56 0.25,5.9; 57 -0.25,5.9; 58 -0.75,5.9; 59 -1.25,5.9; 60 -1.75,5.9; 61 -2.25,5.9; 62 -2.75,5.9; 63 -3.25,5.9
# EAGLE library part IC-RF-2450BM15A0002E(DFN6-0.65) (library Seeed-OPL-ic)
310060009

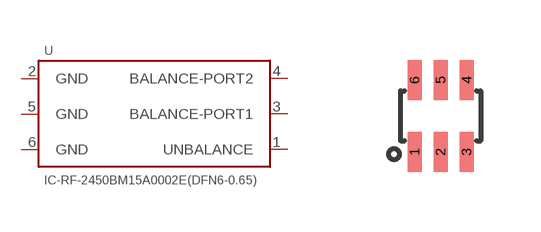
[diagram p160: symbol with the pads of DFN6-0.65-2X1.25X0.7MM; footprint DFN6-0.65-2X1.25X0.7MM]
Designator prefix U

## IC-RF-2450BM15A0002E(DFN6-0.65) (MPN: 2450BM15A0002E; VALUE: 2450BM15A0002E)  [DFN6-0.65-2X1.25X0.7MM]
1  UNBALANCE
2  GND  sup
3  BALANCE-PORT1
4  BALANCE-PORT2
5  GND  sup
6  GND  sup

## Footprint DFN6-0.65-2X1.25X0.7MM (pad centres in mm)
smd 0.35 x 1: 1 -0.65,-0.9; 2 0,-0.9; 3 0.65,-0.9; 4 0.65,0.9; 5 0,0.9; 6 -0.65,0.9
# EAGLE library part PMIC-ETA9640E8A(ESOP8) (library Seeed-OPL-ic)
310030179

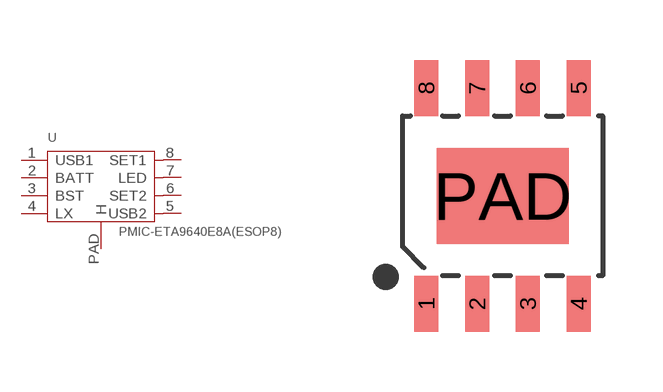
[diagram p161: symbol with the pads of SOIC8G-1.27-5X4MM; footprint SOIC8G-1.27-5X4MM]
Designator prefix U

## PMIC-ETA9640E8A(ESOP8) (MPN: ETA9640E8A; VALUE: ETA9640E8A)  [SOIC8G-1.27-5X4MM]
1  USB1  in
2  BATT
3  BST
4  LX  in
5  USB2
6  SET2
7  LED
8  SET1  in
PAD  H

## Footprint SOIC8G-1.27-5X4MM (pad centres in mm)
smd 0.6 x 1.4: 1 -1.905,-2.7; 2 -0.635,-2.7; 3 0.635,-2.7; 4 1.905,-2.7; 5 1.905,2.7; 6 0.635,2.7; 7 -0.635,2.7; 8 -1.905,2.7
smd 3.3 x 2.4: PAD 0,0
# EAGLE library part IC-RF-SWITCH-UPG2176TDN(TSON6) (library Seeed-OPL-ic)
310990012

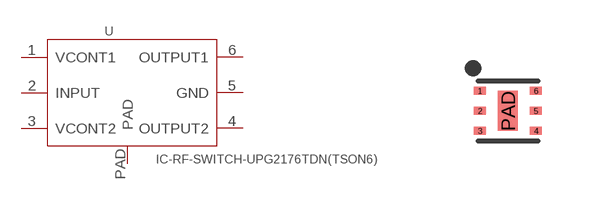
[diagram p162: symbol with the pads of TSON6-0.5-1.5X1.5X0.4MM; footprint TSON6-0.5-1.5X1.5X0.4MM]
Designator prefix U

## IC-RF-SWITCH-UPG2176TDN(TSON6) (MPN: uPG2176T5N; VALUE: uPG2176T5N)  [TSON6-0.5-1.5X1.5X0.4MM]
1  VCONT1  sup
2  INPUT  in
3  VCONT2
4  OUTPUT2
5  GND  sup
6  OUTPUT1
PAD  PAD  sup

## Footprint TSON6-0.5-1.5X1.5X0.4MM (pad centres in mm)
smd 0.3 x 0.2: 1 -0.7,0.5; 2 -0.7,0; 3 -0.7,-0.5; 4 0.7,-0.5; 5 0.7,0; 6 0.7,0.5
smd 0.5 x 1: PAD 0,0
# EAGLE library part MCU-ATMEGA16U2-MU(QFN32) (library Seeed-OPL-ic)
310010018

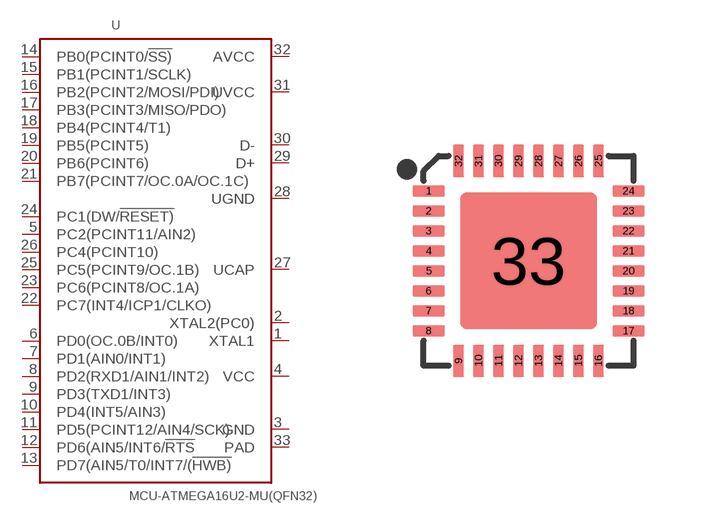
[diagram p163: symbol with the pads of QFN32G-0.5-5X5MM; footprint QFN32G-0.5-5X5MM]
Designator prefix U

## MCU-ATMEGA16U2-MU(QFN32) (MPN: ATMEGA16U2-MU; VALUE: ATMEGA16U2-MU)  [QFN32G-0.5-5X5MM]
1  XTAL1
2  XTAL2(PC0)
3  GND
4  VCC
5  PC2(PCINT11/AIN2)
6  PD0(OC.0B/INT0)
7  PD1(AIN0/INT1)
8  PD2(RXD1/AIN1/INT2)
9  PD3(TXD1/INT3)
10  PD4(INT5/AIN3)
11  PD5(PCINT12/AIN4/SCK)
12  PD6(AIN5/INT6/!RTS
13  PD7(AIN5/T0/INT7/(!HWB)
14  PB0(PCINT0/!SS)
15  PB1(PCINT1/SCLK)
16  PB2(PCINT2/MOSI/PDI)
17  PB3(PCINT3/MISO/PDO)
18  PB4(PCINT4/T1)
19  PB5(PCINT5)
20  PB6(PCINT6)
21  PB7(PCINT7/OC.0A/OC.1C)
22  PC7(INT4/ICP1/CLKO)
23  PC6(PCINT8/OC.1A)
24  PC1(DW/!RESET)
25  PC5(PCINT9/OC.1B)
26  PC4(PCINT10)
27  UCAP
28  UGND
29  D+
30  D-
31  UVCC
32  AVCC
33  PAD

## Footprint QFN32G-0.5-5X5MM (pad centres in mm)
smd 0.813 x 0.279: 1 -2.5,1.75; 2 -2.5,1.25; 3 -2.5,0.75; 4 -2.5,0.25; 5 -2.5,-0.25; 6 -2.5,-0.75; 7 -2.5,-1.25; 8 -2.5,-1.75; 17 2.5,-1.75; 18 2.5,-1.25; 19 2.5,-0.75; 20 2.5,-0.25; 21 2.5,0.25; 22 2.5,0.75; 23 2.5,1.25; 24 2.5,1.75
smd 0.279 x 0.813: 9 -1.75,-2.5; 10 -1.25,-2.5; 11 -0.75,-2.5; 12 -0.25,-2.5; 13 0.25,-2.5; 14 0.75,-2.5; 15 1.25,-2.5; 16 1.75,-2.5; 25 1.75,2.5; 26 1.25,2.5; 27 0.75,2.5; 28 0.25,2.5; 29 -0.25,2.5; 30 -0.75,2.5; 31 -1.25,2.5; 32 -1.75,2.5
smd 3.429 x 3.429: 33 0,0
